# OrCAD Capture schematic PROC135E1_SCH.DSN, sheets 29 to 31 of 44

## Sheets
29 29. JTAG 20 PIN cTI CONNECTOR: size C; title: JTAG 20 PIN cTI CONNECTOR
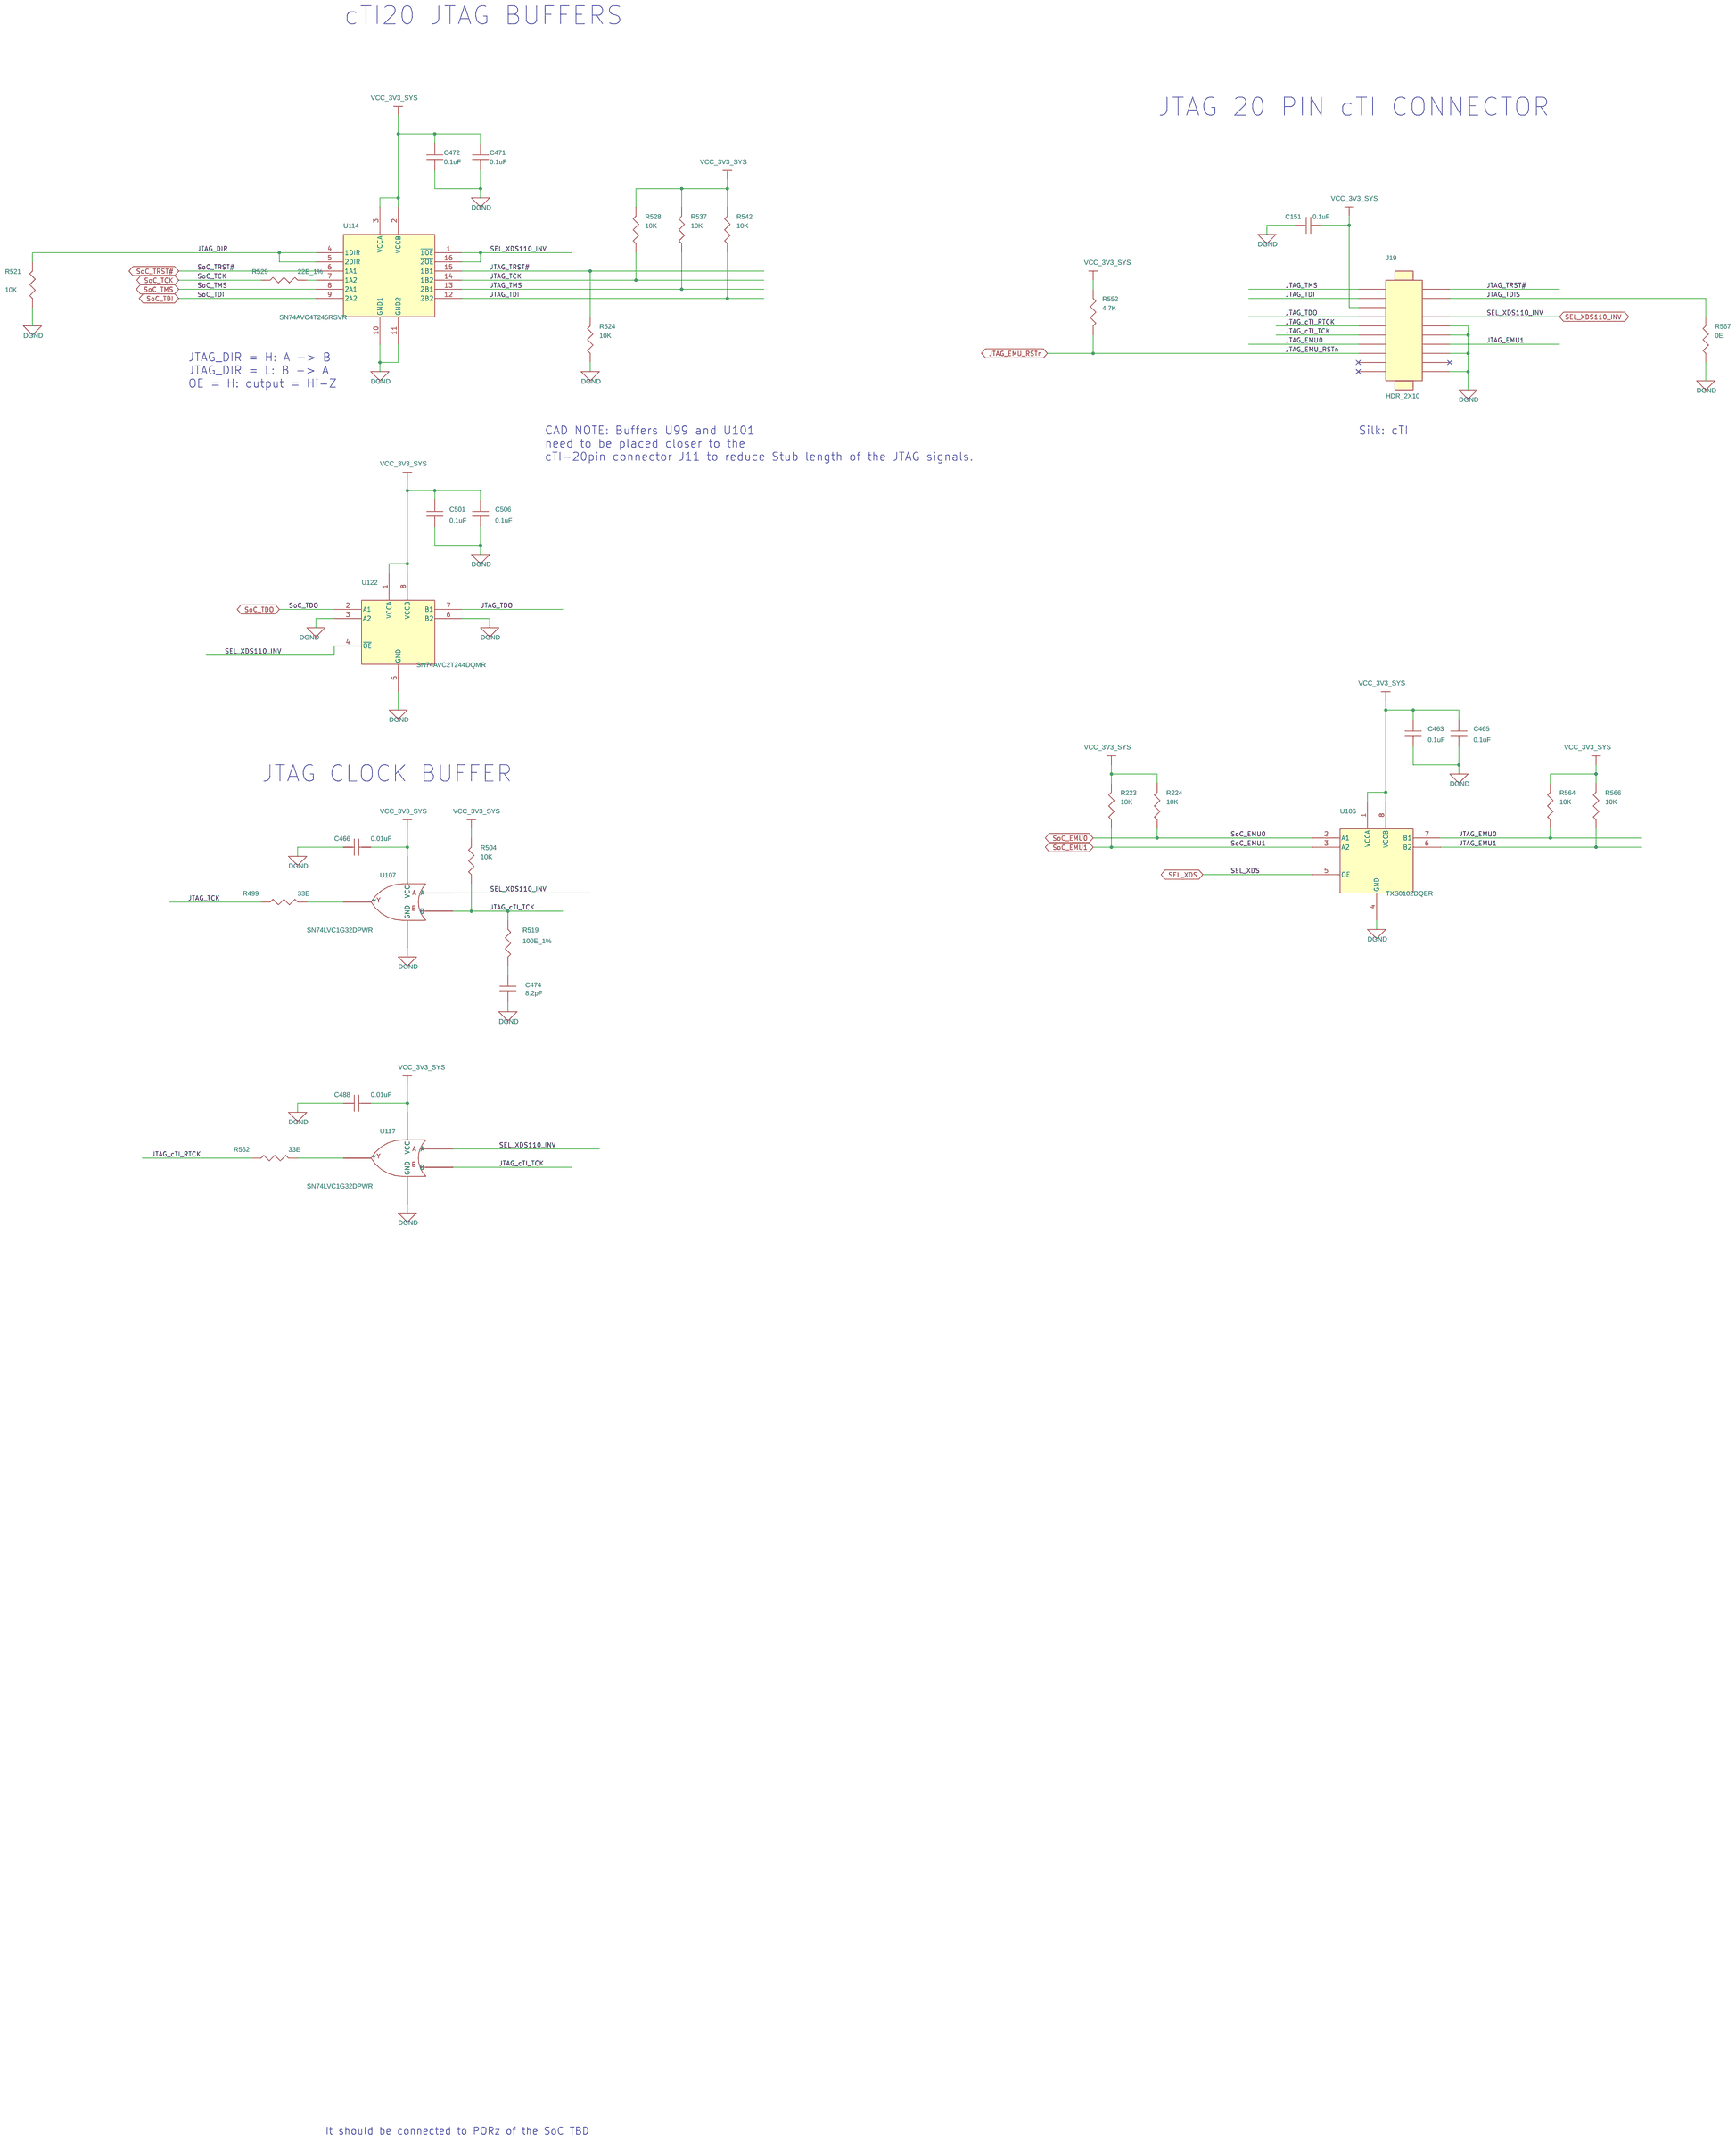
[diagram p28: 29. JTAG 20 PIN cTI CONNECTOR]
30 30. FT4232 UART TO USB BRIDGE: size C; title: FT4232 UART TO USB BRIDGE
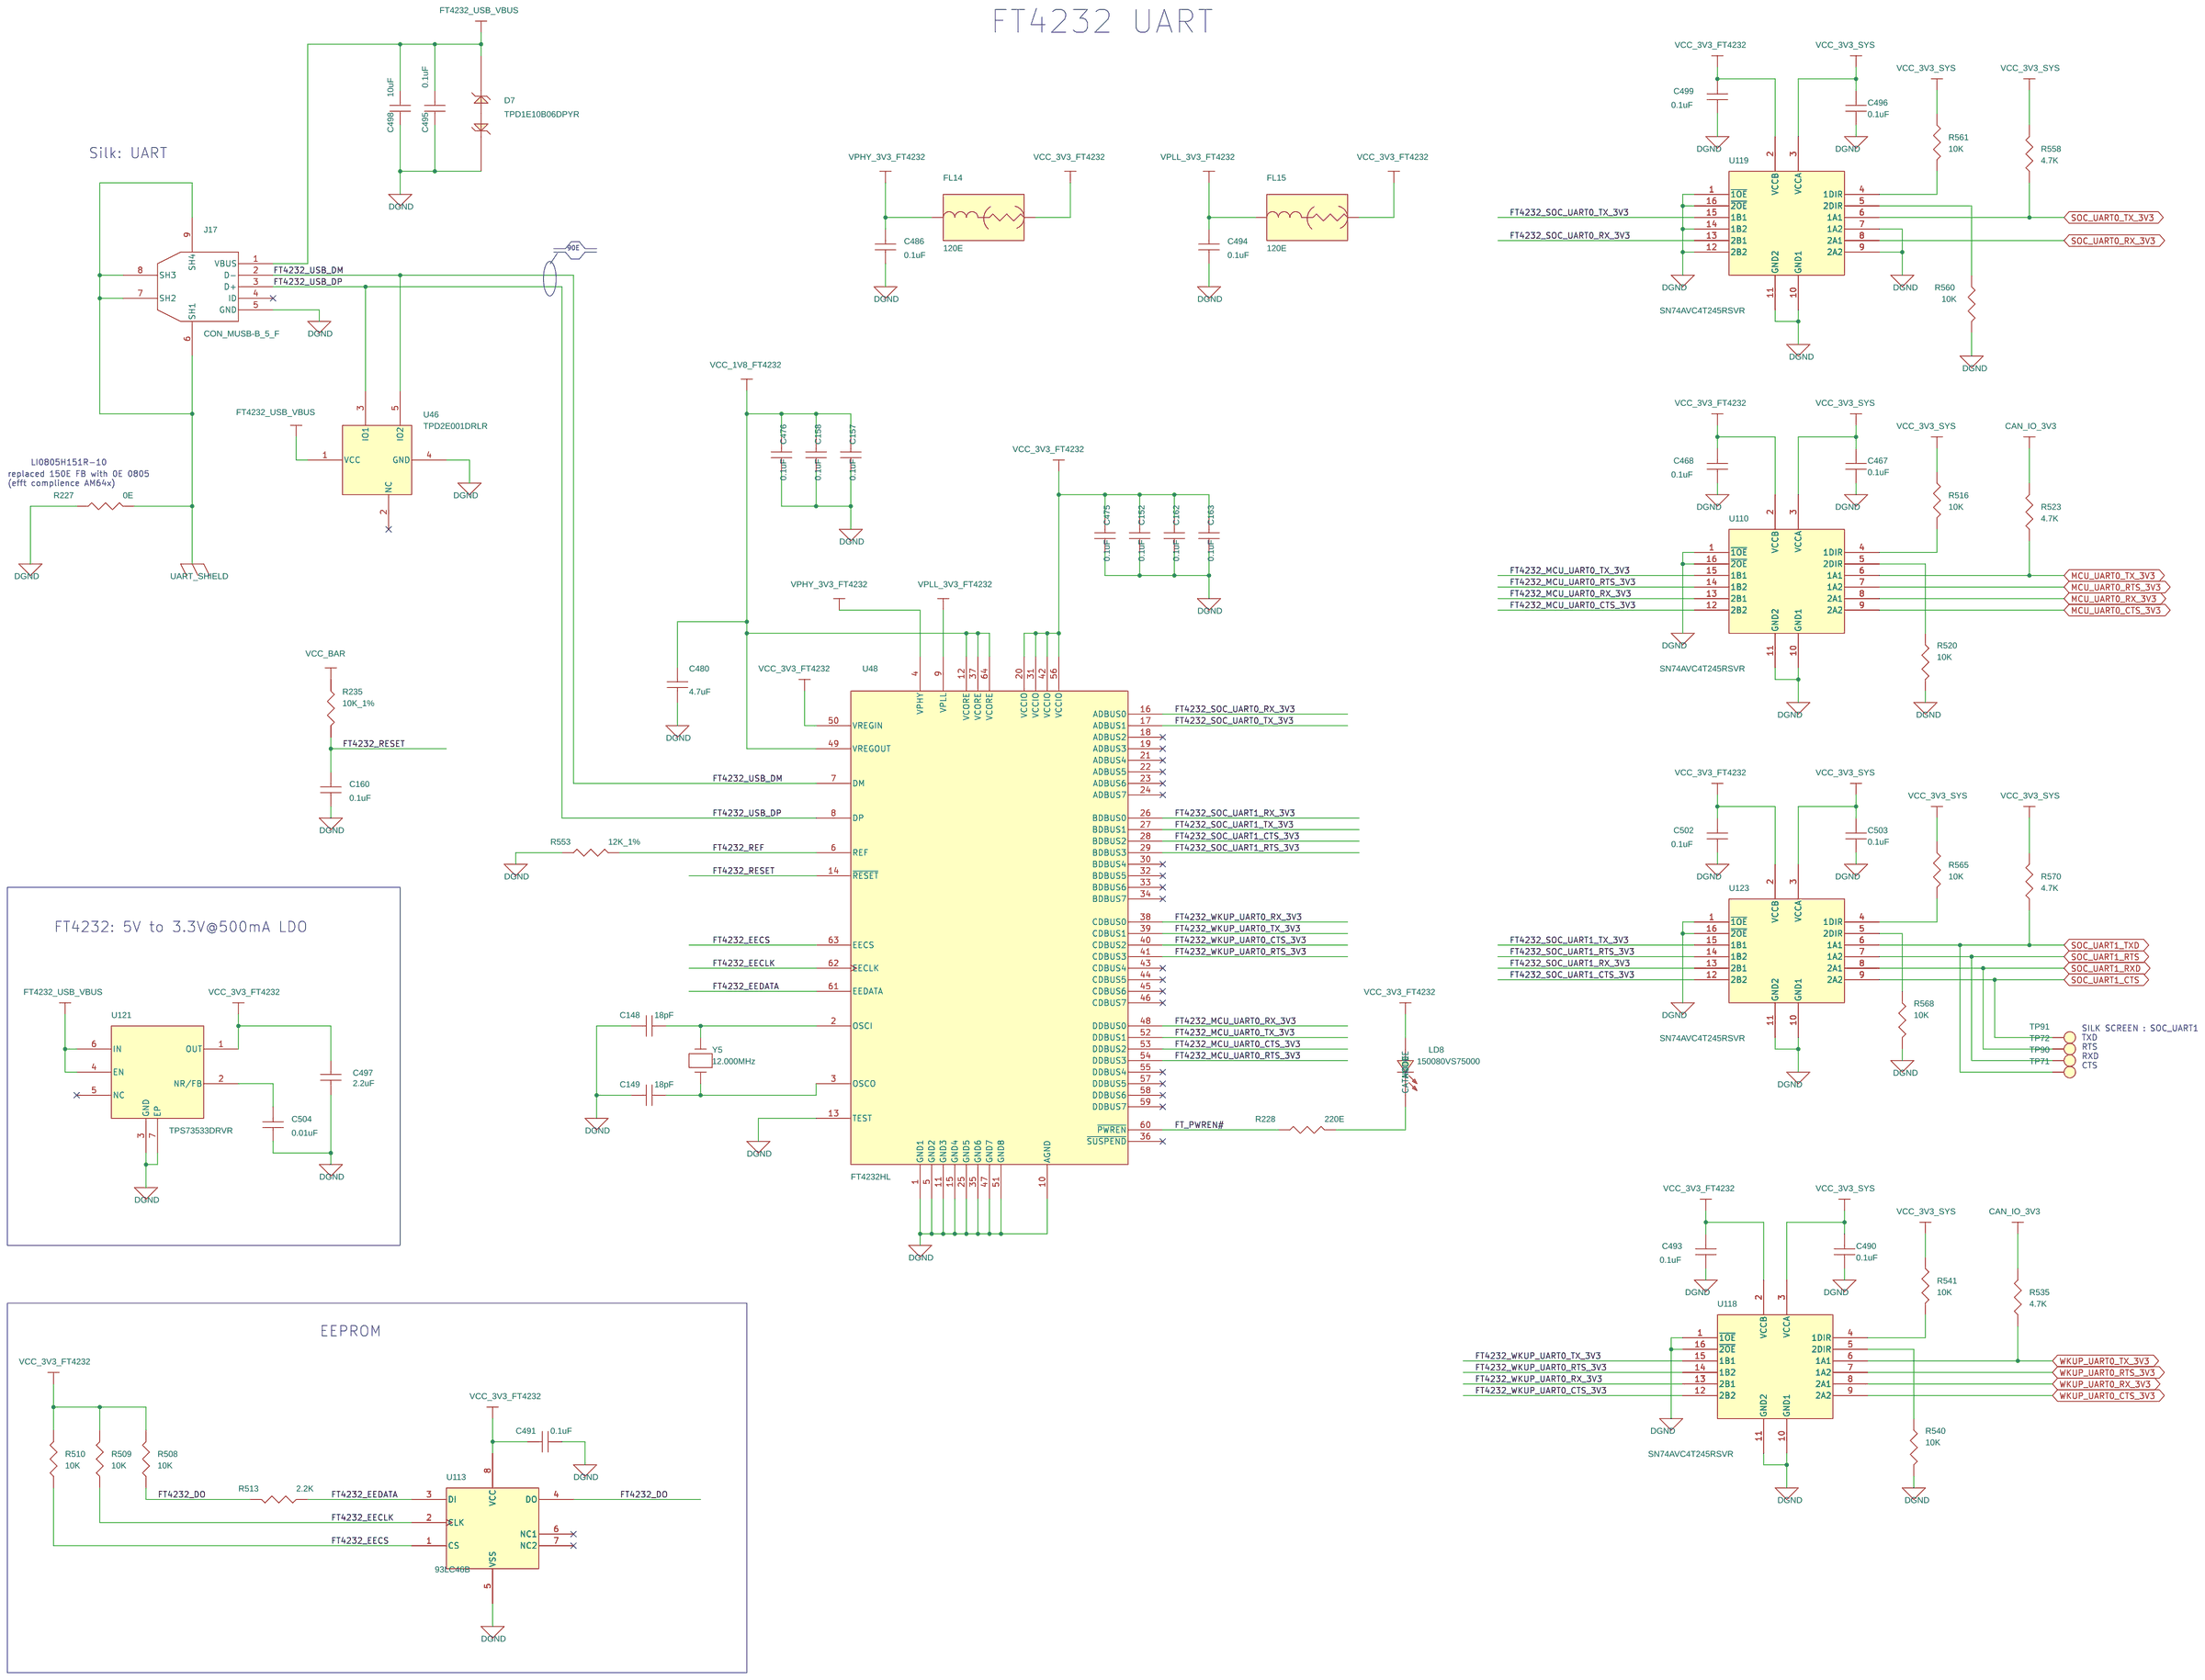
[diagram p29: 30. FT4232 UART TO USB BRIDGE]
31 31. SOC WKUP & GPMC: size C; title: SOC WKUP & GPMC

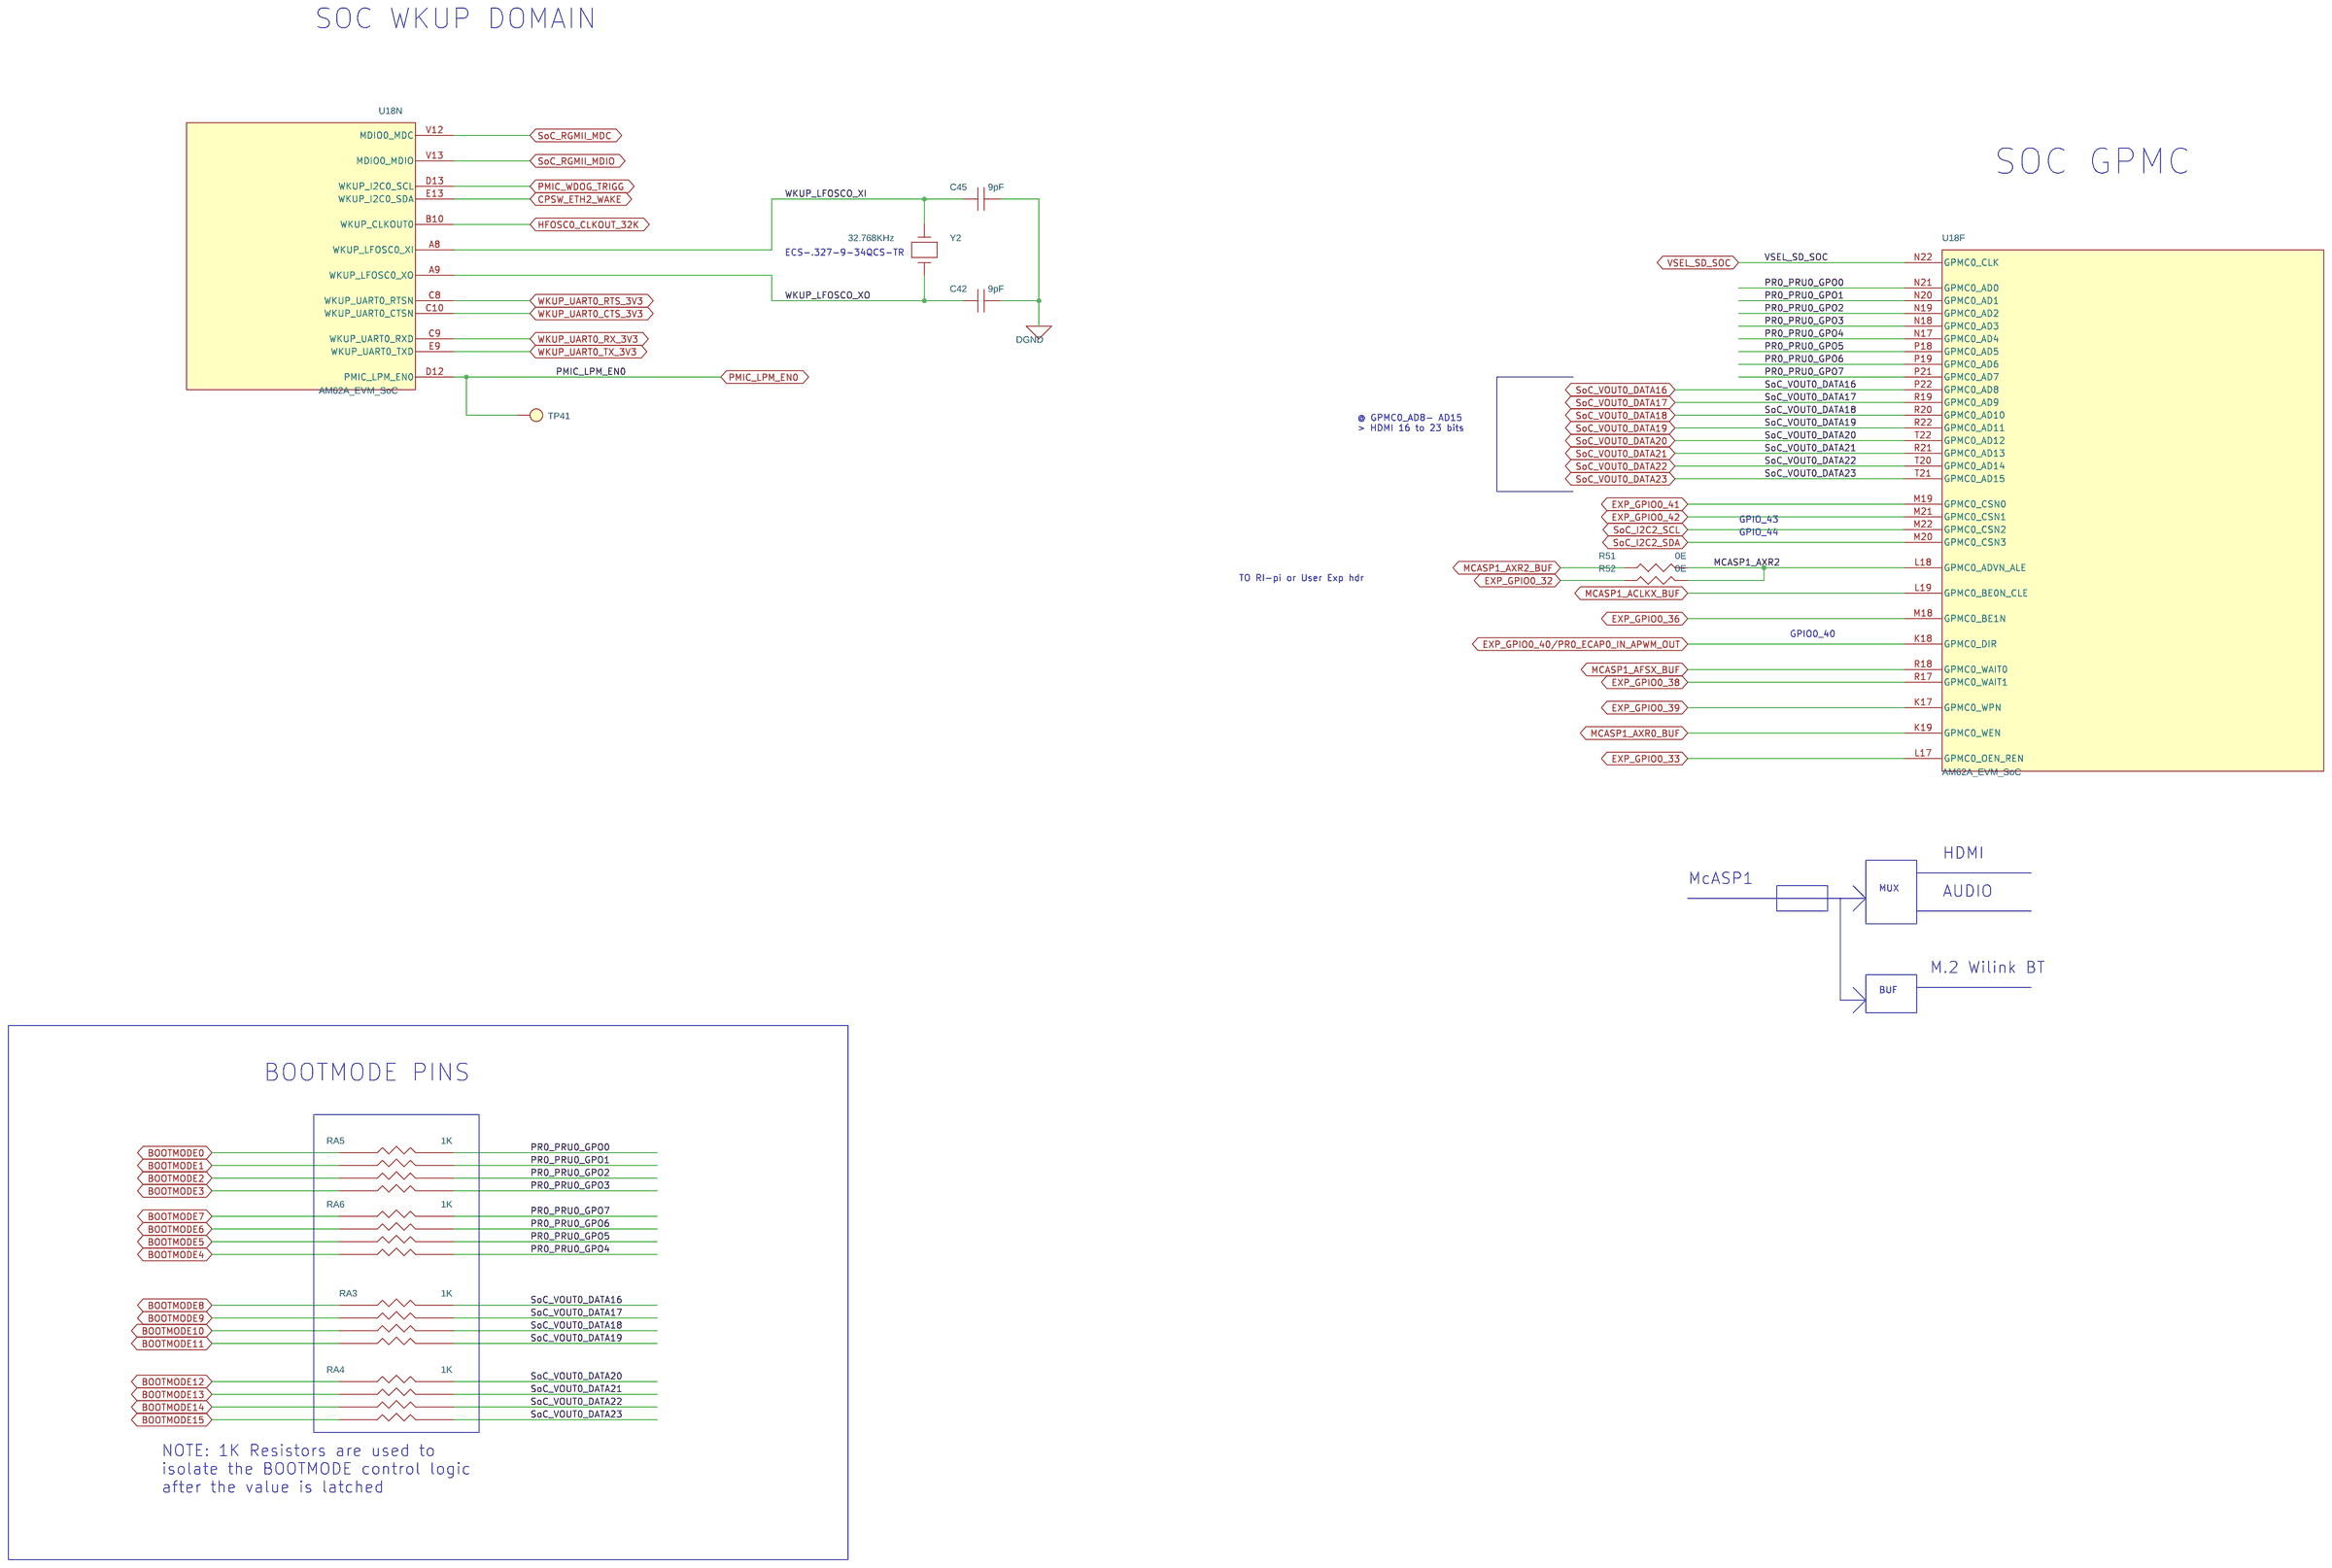
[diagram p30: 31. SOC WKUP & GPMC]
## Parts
sheet 29. JTAG 20 PIN cTI CONNECTOR
C151  0.1uF  [CAP0201_0-5]
C463  0.1uF  [CAP0201_0-5]
C465  0.1uF  [CAP0201_0-5]
C466  0.01uF  [CAP0201_0-5]
C471  0.1uF  [CAP0201_0-5]
C472  0.1uF  [CAP0201_0-5]
C474  8.2pF  [CAP0201_0-5]
C488  0.01uF  [CAP0201_0-5]
C501  0.1uF  [CAP0201_0-5]
C506  0.1uF  [CAP0201_0-5]
J19  HDR_2X10  [HDR_2X10_FTR-110-51-D-06_S_S_8-7]
R223  10K  [RES0201_0-5]
R224  10K  [RES0201_0-5]
R499  33E  [RES0201_0-5]
R504  10K  [RES0201_0-5]
R519  100E_1%  [RES0402_0-5]
R521  10K  [RES0201_0-5]
R524  10K  [RES0201_0-5]
R528  10K  [RES0201_0-5]
R529  22E_1%  [RES0201_0-5]
R537  10K  [RES0201_0-5]
R542  10K  [RES0201_0-5]
R552  4.7K  [RES0201_0-5]
R562  33E  [RES0201_0-5]
R564  10K  [RES0201_0-5]
R566  10K  [RES0201_0-5]
R567  0E  [RES0201_0-5]
U106  TXS0102DQER  [X2SON8_TXS0102_40X60_0-4]
U107  SN74LVC1G32DPWR  [X2SON5_TLV7021_30X30_0-4]
U114  SN74AVC4T245RSVR  [UQFN16_TMUX1574_70X100_0-6]
U117  SN74LVC1G32DPWR  [X2SON5_TLV7021_30X30_0-4]
U122  SN74AVC2T244DQMR  [X2SON8_15-74_70X50]
sheet 30. FT4232 UART TO USB BRIDGE
C148  18pF  [CAP0402_0-75]
C149  18pF  [CAP0402_0-75]
C152  0.1uF  [CAP0402_0-75]
C157  0.1uF  [CAP0402_0-75]
C158  0.1uF  [CAP0402_0-75]
C160  0.1uF  [CAP0201_0-5]
C162  0.1uF  [CAP0402_0-75]
C163  0.1uF  [CAP0402_0-75]
C467  0.1uF  [CAP0201_0-5]
C468  0.1uF  [CAP0201_0-5]
C475  0.1uF  [CAP0402_0-75]
C476  0.1uF  [CAP0402_0-75]
C480  4.7uF  [CAP0402_0-75]
C486  0.1uF  [CAP0402_0-75]
C490  0.1uF  [CAP0201_0-5]
C491  0.1uF  [CAP0402_0-75]
C493  0.1uF  [CAP0201_0-5]
C494  0.1uF  [CAP0402_0-75]
C495  0.1uF  [CAP0402_0-75]
C496  0.1uF  [CAP0201_0-5]
C497  2.2uF  [CAP0402_0-75]
C498  10uF  [CAP0402_0-75]
C499  0.1uF  [CAP0201_0-5]
C502  0.1uF  [CAP0201_0-5]
C503  0.1uF  [CAP0201_0-5]
C504  0.01uF  [CAP0201_0-5]
D7  TPD1E10B06DPYR  [DIO_DFN0402_0-5]
FL14  120E  [EMIFIL_BLM15A_0402_0-6]
FL15  120E  [EMIFIL_BLM15A_0402_0-6]
J17  CON_MUSB-B_5_F  [CON_MUSBB5_629105150521_S_R_S_2-7]
LD8  150080VS75000  [LED_150080VS75000_80X50_SMD_0-8]
R227  0E  [RES0805_0-75]
R228  220E  [RES0402_0-5]
R235  10K_1%  [RES0201_0-5]
R508  10K  [RES0201_0-5]
R509  10K  [RES0201_0-5]
R510  10K  [RES0201_0-5]
R513  2.2K  [RES0201_0-5]
R516  10K  [RES0201_0-5]
R520  10K  [RES0201_0-5]
R523  4.7K  [RES0201_0-5]
R535  4.7K  [RES0201_0-5]
R540  10K  [RES0201_0-5]
R541  10K  [RES0201_0-5]
R553  12K_1%  [RES0402_0-5]
R558  4.7K  [RES0201_0-5]
R560  10K  [RES0201_0-5]
R561  10K  [RES0201_0-5]
R565  10K  [RES0201_0-5]
R568  10K  [RES0201_0-5]
R570  4.7K  [RES0201_0-5]
TP71  TP20_SMD  [TP20_SMD]
TP72  TP20_SMD  [TP20_SMD]
TP90  TP20_SMD  [TP20_SMD]
TP91  TP20_SMD  [TP20_SMD]
U46  TPD2E001DRLR  [SOT553-5_0-6]
U48  FT4232HL  [LQFP64_19-68_390X390_1-6]
U110  SN74AVC4T245RSVR  [UQFN16_TMUX1574_70X100_0-6]
U113  93LC46B  [MSOP8_25-59_125X125_1-1]
U118  SN74AVC4T245RSVR  [UQFN16_TMUX1574_70X100_0-6]
U119  SN74AVC4T245RSVR  [UQFN16_TMUX1574_70X100_0-6]
U121  TPS73533DRVR  [SON6_25-59_85X85]
U123  SN74AVC4T245RSVR  [UQFN16_TMUX1574_70X100_0-6]
Y5  12.000MHz  [XTAL_ABM3_205X130_SMD_1-4]
sheet 31. SOC WKUP & GPMC
C42  9pF  [CAP0402_0-75]
C45  9pF  [CAP0402_0-75]
R51  0E  [RES0201_0-5]
R52  0E  [RES0201_0-5]
RA3  1K  [RESA_EXB_0201-4_0-5]
RA4  1K  [RESA_EXB_0201-4_0-5]
RA5  1K  [RESA_EXB_0201-4_0-5]
RA6  1K  [RESA_EXB_0201-4_0-5]
TP41  TP20_SMD  [TP20_SMD]
Y2  32.768KHz  [XTAL_ECS-32_130X60_SMD_0-9]
sheet 32. USER EXPANSION CONNECTOR
U18  AM62A_EVM_SoC  [FBGA484_31-49_710X710_2-7]  (sections A,B,C,D,E,F,G,H,I,J,K,L,M,N,O,P,Q)

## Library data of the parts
C151 C160 C463 C465 C467 C468 C471 C472 C490 C493 C496 C499 C501-C503 C506 = CAP: CAP CERAMIC 0.1uF 16V 10% X5R 0201; Alt_Mfr_name: YAGEO AMERICA; Alt_Mfr_part_number: CC0402KRX5R8BB104; Chkd/date: MANIRAJA/230118; Crtd /date: MANIRAJA/230118; Custom_Duty: 15%; Customs_HS_Code: 85322990; Distributor_name: DIGIKEY; Distributor_part_number: 490-14305-1-ND; Footprint Path: Y:\MIS_DATABASE\Library\ALTIUM_TOOL\PCB_FOOTPRINTS\Altium_Footprint_Lib.PcbLib; Height: 0.33MM; Library Path: Y:\MIS_DATABASE\Library\ALTIUM_TOOL\SCHEMATICS_PARTS\MS_DISCRETE_Library.schlib; Mfr_name: MURATA; Mfr_part_number: GRM033R61C104KE14D; Mistral Part No: 120009030072-R; Package: 0201; Part_type: CAPACITORS\CERAMIC; Project: TI_MAXIE_CPB; RoHS: RoHS; Temperature: -55°C+85°C; Tolerance: 10%; Voltage: 16V; Wattage: NA; Weight: 0.33mg; Datasheet: Y:\MIS_DATABASE\DATASHEETS\CAPACITORS\GRM033R61C104KE14.PDF
C466 C488 C504 = CAP: CAP CERAMIC 0.01uF 25V 10% X5R 0201; Chkd/date: MANIRAJA/230118; Crtd /date: MANIRAJA/230118; Custom_Duty: 15%; Customs_HS_Code: 85322990; Distributor_name: DIGIKEY; Distributor_part_number: GRM033R61E103KA12J-ND; Footprint Path: Y:\MIS_DATABASE\Library\ALTIUM_TOOL\PCB_FOOTPRINTS\Altium_Footprint_Lib.PcbLib; Height: 0.33MM; Library Path: Y:\MIS_DATABASE\Library\ALTIUM_TOOL\SCHEMATICS_PARTS\MS_DISCRETE_Library.schlib; Mfr_name: MURATA; Mfr_part_number: GRM033R61E103KA12J; Mistral Part No: 120018010007-R; Package: 0201; Part_type: CAPACITORS\CERAMIC; Project: TI_MAXIE_CPB; RoHS: RoHS; Temperature: -55°C+85°C; Tolerance: 10%; Voltage: 25V; Wattage: NA; Weight: 0.33mg; Datasheet: Y:\MIS_DATABASE\DATASHEETS\CAPACITORS\GRM033R61E103KA12.PDF
C474 = CAP: CAP CERAMIC 8.2pF 25V 0.5pF C0G(NP0) 0201; Chkd/date: MANIRAJA/121020; Crtd /date: ALVY/091020; Custom_Duty: 15%; Customs_HS_Code: 85322990; Distributor_name: DIGIKEY; Distributor_part_number: 490-3140-1-ND; Footprint Path: Y:\MIS_DATABASE\Library\ALTIUM_TOOL\PCB_FOOTPRINTS\Altium_Footprint_Lib.PcbLib; Height: 0.33MM; Library Path: Y:\MIS_DATABASE\Library\ALTIUM_TOOL\SCHEMATICS_PARTS\MS_DISCRETE_Library.schlib; Mfr_name: MURATA; Mfr_part_number: GRM0335C1E8R2DA01D; Mistral Part No: 120020100018-R; Package: 0201; Part_type: CAPACITORS\CERAMIC; Project: AM64X_SKEVM; RoHS: RoHS; Temperature: -55°C+125°C; Tolerance: 0.5pF%; Voltage: 25V; Wattage: NA; Weight: 0.33mg; Datasheet: Y:\MIS_DATABASE\DATASHEETS\CAPACITORS\GRM0335C1E8R2DA01.PDF
J19 = HEADER_10X2_FTR-06: CON HDR 2X10 1.27MM PITCH ST SMD; Chkd/date: MANIRAJA/031218; Crtd /date: CHAITHANYA/050811; Custom_Duty: 24%; Customs_HS_Code: 85369090; Distributor_name: DIGIKEY; Distributor_part_number: SAM8792-ND; Footprint Path: Y:\MIS_DATABASE\Library\ALTIUM_TOOL\PCB_FOOTPRINTS\Altium_Footprint_Lib.PcbLib; Height: 8.67MM; Library Path: Y:\MIS_DATABASE\Library\ALTIUM_TOOL\SCHEMATICS_PARTS\MS_CONNECTOR_Library.schlib; Mfr_name: SAMTEC; Mfr_part_number: FTR-110-51-S-D-06; Mistral Part No: 150011090001-R; Package: SMD; Part_type: CONNECTOR\HEADERS; Project: GEMYC; RoHS: RoHS; Temperature: -55°C+125°C; Tolerance: NA; Voltage: NA; Wattage: NA; Weight: NA; Datasheet: Y:\MIS_DATABASE\DATASHEETS\CONNECTORS\FTR-D-SER.PDF
R223 R224 R504 R508-R510 R516 R520 R521 R524 R528 R537 R540-R542 R560 R561 R564-R566 R568 = RESISTOR: RES 10K 1/20W 5% 0201; Chkd/date: MANIRAJA/050517; Crtd /date: MANIRAJA/050517; Custom_Duty: 15%; Customs_HS_Code: 85332119; Distributor_name: DIGIKEY; Distributor_part_number: 311-10KNCT-ND; Footprint Path: Y:\MIS_DATABASE\Library\ALTIUM_TOOL\PCB_FOOTPRINTS\Altium_Footprint_Lib.PcbLib; Height: 0.26MM; Library Path: Y:\MIS_DATABASE\Library\ALTIUM_TOOL\SCHEMATICS_PARTS\MS_DISCRETE_Library.schlib; Mfr_name: YAGEO AMERICA; Mfr_part_number: RC0201JR-0710KL; Mistral Part No: 110010070051-R; Package: 0201; Part_type: RESISTORS\FIXED; Project: GOLDEN-I LITE; RoHS: RoHS; Temperature: -55°C+125°C; Tolerance: 5%; Voltage: NA; Wattage: 1/20W; Weight: 0.17mg; Datasheet: Y:\MIS_DATABASE\DATASHEETS\RESISTORS\RCXXXXL-SER_MAR18.PDF
R499 R562 = RESISTOR: RES 33E 1/20W 5% 0201; Chkd/date: VASANTHA/061216; Crtd /date: MAZHAR/170505; Custom_Duty: 15%; Customs_HS_Code: 85332119; Distributor_name: DIGIKEY; Distributor_part_number: P33AGCT-ND; Footprint Path: Y:\MIS_DATABASE\Library\ALTIUM_TOOL\PCB_FOOTPRINTS\Altium_Footprint_Lib.PcbLib; Height: 0.26MM; Library Path: Y:\MIS_DATABASE\Library\ALTIUM_TOOL\SCHEMATICS_PARTS\MS_DISCRETE_Library.schlib; Mfr_name: PANASONIC-ECG; Mfr_part_number: ERJ-1GEJ330C; Mistral Part No: 110010070052-R; Package: 0201; Part_type: RESISTORS\FIXED; Project: G4SLIM; RoHS: RoHS; Temperature: -55°C+125°C; Tolerance: 5%; Voltage: NA; Wattage: 1/20W; Weight: 0.15mg; Datasheet: Y:\MIS_DATABASE\DATASHEETS\RESISTORS\PAN-ERJXGE-FEB06.PDF
R519 = RESISTOR: RES 100E 1/16W 1% 0402; Chkd/date: MANIRAJA/060318; Crtd /date: NAVEED/220714; Custom_Duty: 15%; Customs_HS_Code: 85332119; Distributor_name: DIGIKEY; Distributor_part_number: 311-100LRCT-ND; Footprint Path: Y:\MIS_DATABASE\Library\ALTIUM_TOOL\PCB_FOOTPRINTS\Altium_Footprint_Lib.PcbLib; Height: 0.40MM; Library Path: Y:\MIS_DATABASE\Library\ALTIUM_TOOL\SCHEMATICS_PARTS\MS_DISCRETE_Library.schlib; Mfr_name: YAGEO AMERICA; Mfr_part_number: RC0402FR-07100RL; Mistral Part No: 110014070015-R; Package: 0402; Part_type: RESISTORS\FIXED; Project: DLRU; RoHS: RoHS; Temperature: -55°C+155°C; Tolerance: 1%; Voltage: NA; Wattage: 1/16W; Weight: 0.65mg; Datasheet: Y:\MIS_DATABASE\DATASHEETS\RESISTORS\RCXXXXL-SER_MAR18.PDF
R529 = RESISTOR: RES 22E 1/20W 1% 0201; Chkd/date: MAZHAR/140709; Crtd /date: MAZHAR/220807; Custom_Duty: 15%; Customs_HS_Code: 85332119; Distributor_name: DIGIKEY; Distributor_part_number: P22.0ABCT-ND; Footprint Path: Y:\MIS_DATABASE\Library\ALTIUM_TOOL\PCB_FOOTPRINTS\Altium_Footprint_Lib.PcbLib; Height: 0.26MM; Library Path: Y:\MIS_DATABASE\Library\ALTIUM_TOOL\SCHEMATICS_PARTS\MS_DISCRETE_Library.schlib; Mfr_name: PANASONIC-ECG; Mfr_part_number: ERJ-1GEF22R0C; Mistral Part No: 110009030522-R; Package: 0201; Part_type: RESISTORS\FIXED; Project: V8TS; RoHS: RoHS; Temperature: -55°C+125°C; Tolerance: 1%; Voltage: NA; Wattage: 1/20W; Weight: 0.15mg; Datasheet: Y:\MIS_DATABASE\DATASHEETS\RESISTORS\PAN-ERJSER_NOV17.PDF
R523 R535 R552 R558 R570 = RESISTOR: RES 4.7K 1/20W 5% 0201; Chkd/date: MANIRAJA/200921; Crtd /date: ALVY/200921; Custom_Duty: 15%; Customs_HS_Code: 85332119; Distributor_name: DIGIKEY; Distributor_part_number: 311-4.7KNCT-ND; Footprint Path: Y:\MIS_DATABASE\Library\ALTIUM_TOOL\PCB_FOOTPRINTS\Altium_Footprint_Lib.PcbLib; Height: 0.26MM; Library Path: Y:\MIS_DATABASE\Library\ALTIUM_TOOL\SCHEMATICS_PARTS\MS_DISCRETE_Library.schlib; Mfr_name: YAGEO AMERICA; Mfr_part_number: RC0201JR-074K7L; Mistral Part No: 110021090007-R; Package: 0201; Part_type: RESISTORS\FIXED; Project: TI_AM62x SKEVM_BRD; RoHS: RoHS; Temperature: -55°C+125°C; Tolerance: 5%; Voltage: NA; Wattage: 1/20W; Weight: 0.17mg; Datasheet: Y:\MIS_DATABASE\DATASHEETS\RESISTORS\RCXXXXL-SER_MAR18.PDF
R51 R52 R567 = RESISTOR: RES 0E 1/20W 5% 0201; Chkd/date: NAVEED/301214; Crtd /date: MUDDU/120710; Custom_Duty: 15%; Customs_HS_Code: 85332119; Distributor_name: DIGIKEY; Distributor_part_number: 311-0.0NCT-ND; Footprint Path: Y:\MIS_DATABASE\Library\ALTIUM_TOOL\PCB_FOOTPRINTS\Altium_Footprint_Lib.PcbLib; Height: 0.26MM; Library Path: Y:\MIS_DATABASE\Library\ALTIUM_TOOL\SCHEMATICS_PARTS\MS_DISCRETE_Library.schlib; Mfr_name: YAGEO AMERICA; Mfr_part_number: RC0201JR-070RL; Mistral Part No: 110010070067-R; Package: 0201; Part_type: RESISTORS\FIXED; Project: PB_BUGBASE; RoHS: RoHS; Temperature: -55°C+125°C; Tolerance: 5%; Voltage: NA; Wattage: 1/20W; Weight: 0.17mg; Datasheet: Y:\MIS_DATABASE\DATASHEETS\RESISTORS\RCXXXXL-SER_MAR18.PDF
U106 = TXS0102DQX_SON8: IC 2-BIT BI-DIR VOLTAGE-LEVEL TRANSLATOR FOR OPEN-DRAIN AND PUSH-PULL X2SON8; Chkd/date: MANIRAJA/010719; Crtd /date: CHAITHANYA230512; Custom_Duty: 15%; Customs_HS_Code: 85423100; Distributor_name: DIGIKEY; Distributor_part_number: 296-28368-1-ND; Footprint Path: Y:\MIS_DATABASE\Library\ALTIUM_TOOL\PCB_FOOTPRINTS\Altium_Footprint_Lib.PcbLib; Height: 0.40MM; Library Path: Y:\MIS_DATABASE\Library\ALTIUM_TOOL\SCHEMATICS_PARTS\MS_MISCINTERFACE_Library.schlib; Mfr_name: TEXAS INSTRUMENTS; Mistral Part No: 141012050010-R; Package: X2SON8; Part_type: ICS\INTERFACE\LEVEL TRANSLATOR; Project: GEN_3-8_DB; RoHS: RoHS; Temperature: -40°C+85°C; Tolerance: NA; Voltage: NA; Wattage: NA; Weight: 1.2mg; Datasheet: Y:\MIS_DATABASE\DATASHEETS\ICS\INTERFACE\TXS0102-SER.PDF
U107 U117 = SN74LVC1G32_X2SON5: IC SINGLE 2-INPUT POSITIVE-OR GATE X2SON5; Chkd/date: MANIRAJA/141020; Crtd /date: ALVY/131020; Custom_Duty: 15%; Customs_HS_Code: 85423100; Distributor_name: DIGIKEY; Distributor_part_number: 296-SN74LVC1G32DPWRCT-ND; Footprint Path: Y:\MIS_DATABASE\Library\ALTIUM_TOOL\PCB_FOOTPRINTS\Altium_Footprint_Lib.PcbLib; Height: 0.40MM; Library Path: Y:\MIS_DATABASE\Library\ALTIUM_TOOL\SCHEMATICS_PARTS\MS_GATE_Library.schlib; Mfr_name: TEXAS INSTRUMENTS; Mistral Part No: 141020100011-R; Package: X2SON5; Part_type: ICS\DIGITAL\GATES; Project: AM64X_SKEVM; RoHS: RoHS; Temperature: -40°C+125°C; Tolerance: NA; Voltage: NA; Wattage: NA; Weight: 0.6mg; Datasheet: Y:\MIS_DATABASE\DATASHEETS\ICS\DIGITAL\GATES\SN74LVC1G32XX.PDF
U110 U114 U118 U119 U123 = SN74AVC4T245RSV_UQFN16: IC 2-BIT BUS TRANSCEIVER WITH CONFIGURABLE VOLTAGE TRANSLATION AND 3 STATE O/P UQFN16; Chkd/date: MANIRAJA/040520; Crtd /date: BAVISH/190411; Custom_Duty: 15%; Customs_HS_Code: 85423100; Distributor_name: DIGIKEY; Distributor_part_number: 296-24366-1-ND; Footprint Path: Y:\MIS_DATABASE\Library\ALTIUM_TOOL\PCB_FOOTPRINTS\Altium_Footprint_Lib.PcbLib; Height: 0.55MM; Library Path: Y:\MIS_DATABASE\Library\ALTIUM_TOOL\SCHEMATICS_PARTS\MS_BUSDRIVERTRANSCEIVER_Library.schlib; Mfr_name: TEXAS INSTRUMENTS; Mistral Part No: 141011040011-R; Package: UQFN16; Part_type: ICS\DIGITAL\BUSTRANSCEIVER; Project: HMC; RoHS: RoHS; Temperature: -40°C+85°C; Tolerance: NA; Voltage: NA; Wattage: NA; Weight: 41mg; Datasheet: Y:\MIS_DATABASE\DATASHEETS\ICS\DIGITAL\BUSTRANSCEIVER\SN74AVC4T245-SER.PDF
U122 = SN74AVC2T244DQMR_X2SON8: IC 2-BIT UNDIRECTIONAL VOLTAGE-LEVEL TRANSLATOR X2SON8; Chkd/date: VASANTHA/060516; Crtd /date: VASANTHA/030316; Customs_HS_Code: 15%; Distributor_name: DIGIKEY; Distributor_part_number: 296-29674-1-ND; Height: 0.40MM; Mfr_name: TEXAS INSTRUMENTS; Mistral Part No: 141016030002-R; Package: X2SON8; Part_type: ICS\INTERFACE\LEVEL TRANSLATOR; Pb-Free: 85423100; Project: OCTASIC_3600; RoHS: RoHS; Temperature: -40°C+85°C; Tolerance: NA; Voltage: NA; Wattage: NA; Weight: NA; Datasheet: Y:\MIS_DATABASE\DATASHEETS\ICS\INTERFACE\SN74AVC2T244.PDF
C148 C149 = CAP: CAP CERAMIC 18pF 50V 5% HI-Q C0G(NP0) 0402; Chkd/date: VASANTHA/030315; Crtd /date: NAVEED/271014; Custom_Duty: 15%; Customs_HS_Code: 85322990; Distributor_name: DIGIKEY; Distributor_part_number: 490-3119-1-ND; Footprint Path: Y:\MIS_DATABASE\Library\ALTIUM_TOOL\PCB_FOOTPRINTS\Altium_Footprint_Lib.PcbLib; Height: 0.55MM; Library Path: Y:\MIS_DATABASE\Library\ALTIUM_TOOL\SCHEMATICS_PARTS\MS_DISCRETE_Library.schlib; Mfr_name: MURATA; Mfr_part_number: GJM1555C1H180JB01D; Mistral Part No: 120014100019-R; Package: 0402; Part_type: CAPACITORS\CERAMIC; Project: DC_MIST_RDC; RoHS: RoHS; Temperature: -55°C+125°C; Tolerance: 5%; Voltage: 50V; Wattage: NA; Weight: 6mg; Datasheet: Y:\MIS_DATABASE\DATASHEETS\CAPACITORS\MURATA-GXX-SER_NOV17.PDF
C152 C157 C158 C162 C163 C475 C476 C486 C491 C494 C495 = CAP: CAP CERAMIC 0.1uF 50V 10% X7R 0402; Alt_Mfr_name: YAGEO AMERICA; Alt_Mfr_part_number: CC0402KRX5R8BB104; Chkd/date: MANIRAJA/261020; Crtd /date: ALVY/211020; Custom_Duty: 15%; Customs_HS_Code: 85322990; Distributor_name: DIGIKEY; Distributor_part_number: 490-10700-1-ND; Footprint Path: Y:\MIS_DATABASE\Library\ALTIUM_TOOL\PCB_FOOTPRINTS\Altium_Footprint_Lib.PcbLib; Height: 0.55MM; Library Path: Y:\MIS_DATABASE\Library\ALTIUM_TOOL\SCHEMATICS_PARTS\MS_DISCRETE_Library.schlib; Mfr_name: MURATA; Mfr_part_number: GRM155R71H104KE14D; Mistral Part No: 120011100014-R; Package: 0402; Part_type: CAPACITORS\CERAMIC; Project: J7_CP; RoHS: RoHS; Temperature: -55°C+125°C; Tolerance: 10%; Voltage: 50V; Wattage: NA; Weight: 3.1mg; Datasheet: Y:\MIS_DATABASE\DATASHEETS\CAPACITORS\GRM155R71H104KE14.PDF
C480 = CAP: CAP CERAMIC 4.7uF 10V 20% X5R 0402; Chkd/date: MANIRAJA/110718; Crtd /date: ALVY/110718; Custom_Duty: 15%; Customs_HS_Code: 85322990; Distributor_name: DIGIKEY; Distributor_part_number: 490-14306-1-ND; Footprint Path: Y:\MIS_DATABASE\Library\ALTIUM_TOOL\PCB_FOOTPRINTS\Altium_Footprint_Lib.PcbLib; Height: 0.65MM; Library Path: Y:\MIS_DATABASE\Library\ALTIUM_TOOL\SCHEMATICS_PARTS\MS_DISCRETE_Library.schlib; Mfr_name: MURATA; Mfr_part_number: GRM155R61A475MEAAD; Mistral Part No: 120012060002-R; Package: 0402; Part_type: CAPACITORS\CERAMIC; Project: TI_J7SVB_PCIE_ADD-ON-CARD; RoHS: RoHS; Temperature: -55°C+85°C; Tolerance: 20%; Voltage: 10V; Wattage: NA; Weight: 14mg; Datasheet: Y:\MIS_DATABASE\DATASHEETS\CAPACITORS\GRM155R61A475MEAAD.PDF
C497 = CAP: CAP CERAMIC 2.2uF 25V 10% X5R 0402; Chkd/date: ALVY/010721; Crtd /date: MANIRAJA/010721; Custom_Duty: 15%; Customs_HS_Code: 85322990; Distributor_name: DIGIKEY; Distributor_part_number: 490-12703-1-ND; Footprint Path: Y:\MIS_DATABASE\Library\ALTIUM_TOOL\PCB_FOOTPRINTS\Altium_Footprint_Lib.PcbLib; Height: 0.70MM; Library Path: Y:\MIS_DATABASE\Library\ALTIUM_TOOL\SCHEMATICS_PARTS\MS_DISCRETE_Library.schlib; Mfr_name: MURATA; Mfr_part_number: GRM155R61E225KE11D; Mistral Part No: 120015120001-R; Package: 0402; Part_type: CAPACITORS\CERAMIC; Project: TI_AM263X_CC; RoHS: RoHS; Temperature: -55°C+85°C; Tolerance: 10%; Voltage: 25V; Wattage: NA; Weight: 1.5mg; Datasheet: Y:\MIS_DATABASE\DATASHEETS\CAPACITORS\GRM155R61E225KE11.PDF
C498 = CAP: CAP CERAMIC 10uF 10V 20% X5R 0402; Chkd/date: MANIRAJA/300520; Crtd /date: ALVY/260520; Custom_Duty: 15%; Customs_HS_Code: 85322990; Distributor_name: DIGIKEY; Distributor_part_number: 490-GRM155R61A106ME11DTR-ND; Footprint Path: Y:\MIS_DATABASE\Library\ALTIUM_TOOL\PCB_FOOTPRINTS\Altium_Footprint_Lib.PcbLib; Height: 0.55MM; Library Path: Y:\MIS_DATABASE\Library\ALTIUM_TOOL\SCHEMATICS_PARTS\MS_DISCRETE_Library.schlib; Mfr_name: MURATA; Mfr_part_number: GRM155R61A106ME11D; Mistral Part No: 120013110019-R; Package: 0402; Part_type: CAPACITORS\CERAMIC; Project: QCS610_NANOSOM; RoHS: RoHS; Temperature: -55°C+85°C; Tolerance: 20%; Voltage: 10V; Wattage: NA; Weight: 3.1mg; Datasheet: Y:\MIS_DATABASE\DATASHEETS\CAPACITORS\MURATA-GXX-SER_NOV17.PDF
D7 = DIODE_SOD323: DIODE 1CH ESD PROTECTION X1SON2; Chkd/date: MANIRAJA/040420; Crtd /date: VASANTHA/181114; Custom_Duty: 15%; Customs_HS_Code: 85423100; Distributor_name: DIGIKEY; Distributor_part_number: 296-30406-1-ND; Footprint Path: Y:\MIS_DATABASE\Library\ALTIUM_TOOL\PCB_FOOTPRINTS\Altium_Footprint_Lib.PcbLib; Height: 0.45MM; Library Path: Y:\MIS_DATABASE\Library\ALTIUM_TOOL\SCHEMATICS_PARTS\MS_DISCRETE_Library.schlib; Mfr_name: TEXAS INSTRUMENTS; Mistral Part No: 130014110022-R; Package: X1SON2; Part_type: DIODE; Project: GALILEO_EVM; RoHS: RoHS; Temperature: -40°C+125°C; Tolerance: NA; Voltage: NA; Wattage: NA; Weight: 1mg; Datasheet: Y:\MIS_DATABASE\DATASHEETS\ICS\INTERFACE\TPD1E10B06-SER.PDF
FL14 FL15 = EMIFILTER_IND: IND FERRITE BEAD CHIP 120E 2A 0402; Chkd/date: NAVEED/241114; Crtd /date: USMAN/170613; Custom_Duty: 24%; Customs_HS_Code: 85369090; Distributor_name: DIGIKEY; Distributor_part_number: 490-9656-1-ND; Footprint Path: Y:\MIS_DATABASE\Library\ALTIUM_TOOL\PCB_FOOTPRINTS\Altium_Footprint_Lib.PcbLib; Height: 0.55MM; Library Path: Y:\MIS_DATABASE\Library\ALTIUM_TOOL\SCHEMATICS_PARTS\MS_FILTER_Library.schlib; Mfr_name: MURATA; Mfr_part_number: BLM15PX121SN1D; Mistral Part No: 130013060022-R; Package: 0402; Part_type: INDUCTOR; Project: GEN_3-8; RoHS: RoHS; Temperature: -55°C+125°C; Tolerance: 25%; Voltage: NA; Wattage: NA; Weight: 1mg; Datasheet: Y:\MIS_DATABASE\DATASHEETS\DISCRETES\INDUCTORS\BLM15-SN1-SER.PDF
J17 = CON_USB_MINI-B: CON MICRO USB TYPE B 5POS FEMALE RT SMD; Chkd/date: MANIRAJA/150519; Crtd /date: ALVY/150519; Custom_Duty: 24%; Customs_HS_Code: 85369090; Distributor_name: DIGIKEY; Distributor_part_number: 732-5960-1-ND; Footprint Path: Y:\MIS_DATABASE\Library\ALTIUM_TOOL\PCB_FOOTPRINTS\Altium_Footprint_Lib.PcbLib; Height: 2.66MM; Library Path: Y:\MIS_DATABASE\Library\ALTIUM_TOOL\SCHEMATICS_PARTS\MS_CONNECTOR_Library.schlib; Mfr_name: WURTH ELECTRONICS; Mfr_part_number: 629105150521; Mistral Part No: 150019050015-R; Package: SMD; Part_type: CONNECTOR\USB; Project: NEXTNAV_ALT-STATION_ATE_BRD; RoHS: RoHS; Temperature: -40°C+85°C; Tolerance: NA; Voltage: NA; Wattage: NA; Weight: 360mg; Datasheet: Y:\MIS_DATABASE\DATASHEETS\CONNECTORS\629105150521.PDF
LD8 = DIODE_LED: DIODE LED BRIGHT GREEN SMD; Chkd/date: MANIRAJA/180820; Crtd /date: ALVY/180820; Custom_Duty: 24%; Customs_HS_Code: 85439000; Distributor_name: DIGIKEY; Distributor_part_number: 732-4986-1-ND; Footprint Path: Y:\MIS_DATABASE\Library\ALTIUM_TOOL\PCB_FOOTPRINTS\Altium_Footprint_Lib.PcbLib; Height: 0.80MM; Library Path: Y:\MIS_DATABASE\Library\ALTIUM_TOOL\SCHEMATICS_PARTS\MS_OPTO_Library.schlib; Mfr_name: WURTH ELECTRONICS; Mistral Part No: 130020080012-R; Package: SMD; Part_type: OPTO\LED; Project: AM64x_EVM_BRD; RoHS: RoHS; Temperature: -40°C+85°C; Tolerance: NA; Voltage: NA; Wattage: NA; Weight: 10mg; Datasheet: Y:\MIS_DATABASE\DATASHEETS\DISCRETES\LEDS\150080VS75000.PDF
R227 = RESISTOR: RES 0E 1/8W 5% 0805; Chkd/date: VASANTHA/130416; Crtd /date: JEBRAN/020316; Custom_Duty: 15%; Customs_HS_Code: 85332119; Distributor_name: DIGIKEY; Distributor_part_number: 311-0.0ARCT-ND; Footprint Path: Y:\MIS_DATABASE\Library\ALTIUM_TOOL\PCB_FOOTPRINTS\Altium_Footprint_Lib.PcbLib; Height: 0.60MM; Library Path: Y:\MIS_DATABASE\Library\ALTIUM_TOOL\SCHEMATICS_PARTS\MS_DISCRETE_Library.schlib; Mfr_name: YAGEO AMERICA; Mfr_part_number: RC0805JR-070RL; Mistral Part No: 110009030074-R; Package: 0805; Part_type: RESISTORS\FIXED; Project: ZK_BIOMETRIC; RoHS: RoHS; Temperature: -55°C+155°C; Tolerance: 5%; Voltage: NA; Wattage: 1/8W; Weight: 5.5mg; Datasheet: Y:\MIS_DATABASE\DATASHEETS\RESISTORS\RCXXXXL-SER_MAR18.PDF
R228 = RESISTOR: RES 220E 1/10W 5% 0402; Chkd/date: VASANTHA/291216; Crtd /date: GEETHA/260406; Custom_Duty: 15%; Customs_HS_Code: 85332119; Distributor_name: DIGIKEY; Distributor_part_number: P220JCT-ND; Footprint Path: Y:\MIS_DATABASE\Library\ALTIUM_TOOL\PCB_FOOTPRINTS\Altium_Footprint_Lib.PcbLib; Height: 0.40MM; Library Path: Y:\MIS_DATABASE\Library\ALTIUM_TOOL\SCHEMATICS_PARTS\MS_DISCRETE_Library.schlib; Mfr_name: PANASONIC-ECG; Mfr_part_number: ERJ-2GEJ221X; Mistral Part No: 110009030506-R; Package: 0402; Part_type: RESISTORS\FIXED; Project: RED EYE; RoHS: RoHS; Temperature: -55°C+155°C; Tolerance: 5%; Voltage: NA; Wattage: 1/10W; Weight: 0.8mg; Datasheet: Y:\MIS_DATABASE\DATASHEETS\RESISTORS\PAN-ERJSER_NOV17.PDF
R235 = RESISTOR: RES 10K 1/20W 1% 0201; Chkd/date: VASANTHA/270117; Crtd /date: MANIRAJA/270117; Custom_Duty: 15%; Customs_HS_Code: 85332119; Distributor_name: DIGIKEY; Distributor_part_number: 311-10.0KMCT-ND; Footprint Path: Y:\MIS_DATABASE\Library\ALTIUM_TOOL\PCB_FOOTPRINTS\Altium_Footprint_Lib.PcbLib; Height: 0.26MM; Library Path: Y:\MIS_DATABASE\Library\ALTIUM_TOOL\SCHEMATICS_PARTS\MS_DISCRETE_Library.schlib; Mfr_name: YAGEO AMERICA; Mfr_part_number: RC0201FR-0710KL; Mistral Part No: 110011040018-R; Package: 0201; Part_type: RESISTORS\FIXED; Project: GOLDEN-I LITE; RoHS: RoHS; Temperature: -55°C+125°C; Tolerance: 1%; Voltage: NA; Wattage: 1/20W; Weight: 0.17mg; Datasheet: Y:\MIS_DATABASE\DATASHEETS\RESISTORS\RCXXXXL-SER_MAR18.PDF
R513 = RESISTOR: RES 2.2K 1/20W 5% 0201; Chkd/date: VASANTHA/010117; Crtd /date: MAZHAR/010605; Custom_Duty: 15%; Customs_HS_Code: 85332119; Distributor_name: DIGIKEY; Distributor_part_number: P2.2KAGCT-ND; Footprint Path: Y:\MIS_DATABASE\Library\ALTIUM_TOOL\PCB_FOOTPRINTS\Altium_Footprint_Lib.PcbLib; Height: 0.26MM; Library Path: Y:\MIS_DATABASE\Library\ALTIUM_TOOL\SCHEMATICS_PARTS\MS_DISCRETE_Library.schlib; Mfr_name: PANASONIC-ECG; Mfr_part_number: ERJ-1GEJ222C; Mistral Part No: 110009030427-R; Package: 0201; Part_type: RESISTORS\FIXED; Project: G4SLIM; RoHS: RoHS; Temperature: -55°C+125°C; Tolerance: 5%; Voltage: NA; Wattage: 1/20W; Weight: 0.15mg; Datasheet: Y:\MIS_DATABASE\DATASHEETS\RESISTORS\PAN-ERJXGE-FEB06.PDF
R553 = RESISTOR: RES 12K 1/10W 1% 0402; Chkd/date: VASANTHA/041215; Crtd /date: VASANTHA/041215; Custom_Duty: 15%; Customs_HS_Code: 85332119; Distributor_name: DIGIKEY; Distributor_part_number: P12.0KLCT-ND; Footprint Path: Y:\MIS_DATABASE\Library\ALTIUM_TOOL\PCB_FOOTPRINTS\Altium_Footprint_Lib.PcbLib; Height: 0.40MM; Library Path: Y:\MIS_DATABASE\Library\ALTIUM_TOOL\SCHEMATICS_PARTS\MS_DISCRETE_Library.schlib; Mfr_name: PANASONIC-ECG; Mfr_part_number: ERJ-2RKF1202X; Mistral Part No: 110019040053-R; Package: 0402; Part_type: RESISTORS\FIXED; Project: TI_C5545; RoHS: RoHS; Temperature: -55°C+155°C; Tolerance: 1%; Voltage: NA; Wattage: 1/10W; Weight: 0.8mg; Datasheet: Y:\MIS_DATABASE\DATASHEETS\RESISTORS\PAN-ERJSER_NOV17.PDF
TP41 TP71 TP72 TP90 TP91 = TESTPOINT: TESTPOINT CIR 20 SMD; Chkd/date: SHREESHAIL/171006; Crtd /date: MAZHAR/171006; Custom_Duty: NA; Customs_HS_Code: NA; Distributor_name: NA; Distributor_part_number: NA; Footprint Path: Y:\MIS_DATABASE\Library\ALTIUM_TOOL\PCB_FOOTPRINTS\Altium_Footprint_Lib.PcbLib; Height: NA; Library Path: Y:\MIS_DATABASE\Library\ALTIUM_TOOL\SCHEMATICS_PARTS\MS_DISCRETE_Library.schlib; MECHANICAL 3D STEP FILE: NA; Mfr_name: LOCAL; Mistral Part No: NA; Package: SMD; Project: BT MODULE_CSRBC04; RoHS: NA; Temperature: NA; Tolerance: NA; Voltage: NA; Wattage: NA; Weight: NA; Datasheet: NA
U46 = TPD2E001DRLR_SOT-5: IC ESD-PROTECTION DIODE ARRAYS SOT-5; Chkd/date: NAVEED/150714; Crtd /date: MUDDU/250510; Custom_Duty: 15%; Customs_HS_Code: 85423100; Distributor_name: DIGIKEY; Distributor_part_number: 296-21883-1-ND; Footprint Path: Y:\MIS_DATABASE\Library\ALTIUM_TOOL\PCB_FOOTPRINTS\Altium_Footprint_Lib.PcbLib; Height: 0.60MM; Library Path: Y:\MIS_DATABASE\Library\ALTIUM_TOOL\SCHEMATICS_PARTS\MS_FILTER_Library.schlib; Mfr_name: TEXAS INSTRUMENTS; Mistral Part No: 140110060007-R; Package: SOT-5; Part_type: ICS\ANALOG\ACTIVE FILTER; Project: CENTAURUS; RoHS: RoHS; Temperature: -40°C+85°C; Tolerance: NA; Voltage: NA; Wattage: NA; Weight: 2.8mg; Datasheet: Y:\MIS_DATABASE\DATASHEETS\ICS\MISC\TPD2E001DRLR.PDF
U48 = FT4232H_LQFP64: IC HIGH SPEED QUAD USB UART LQFP64; Chkd/date: MANIRAJA/110917; Crtd /date: VIJAYALAKSHMI/120813; Custom_Duty: 15%; Customs_HS_Code: 85423100; Distributor_name: DIGIKEY; Distributor_part_number: 768-1026-1-ND; Footprint Path: Y:\MIS_DATABASE\Library\ALTIUM_TOOL\PCB_FOOTPRINTS\Altium_Footprint_Lib.PcbLib; Height: 1.60MM; Library Path: Y:\MIS_DATABASE\Library\ALTIUM_TOOL\SCHEMATICS_PARTS\MS_COMBINATIONAL_Library.schlib; Mfr_name: FTDI; Mfr_part_number: FT4232HL-REEL; Mistral Part No: 141013080006-R; Package: LQFP64; Part_type: ICS\DIGITAL\PERIPHERAL; Project: DM37XX; RoHS: RoHS; Temperature: -40°C+85°C; Tolerance: NA; Voltage: NA; Wattage: NA; Weight: 342.7mg; Datasheet: Y:\MIS_DATABASE\DATASHEETS\ICS\DIGITAL\PERIPHERAL\FT4232HX.PDF
U113 = 93LC46B_MSOP8: IC 1K MICROWIRE COMPATIBLE SERIAL EEPROM MSOP8; Chkd/date: MANIRAJA/150218; Crtd /date: ALVY/150218; Custom_Duty: 15%; Customs_HS_Code: 85423100; Distributor_name: DIGIKEY; Distributor_part_number: 93LC46B-I/MS-ND; Footprint Path: Y:\MIS_DATABASE\Library\ALTIUM_TOOL\PCB_FOOTPRINTS\Altium_Footprint_Lib.PcbLib; Height: 1.10MM; Library Path: Y:\MIS_DATABASE\Library\ALTIUM_TOOL\SCHEMATICS_PARTS\MS_MISCMEMORY_Library.schlib; Mfr_name: MICROCHIP; Mfr_part_number: 93LC46B-I/MS; Mistral Part No: 141118020002-R; Package: MSOP8; Part_type: ICS\DIGITAL\MEMORY; Project: TI_MAXIE_CPB; RoHS: RoHS; Temperature: -40°C+85°C; Tolerance: NA; Voltage: NA; Wattage: NA; Weight: 140mg; Datasheet: Y:\MIS_DATABASE\DATASHEETS\ICS\MEMORY\93LC46B.PDF
U121 = TPS73501DRVR_SON6: IC 500mA LOW DROPOUT REGULATOR SON6; Chkd/date: VASANTHA/280915; Crtd /date: NAVEED/011014; Custom_Duty: 15%; Customs_HS_Code: 85423100; Distributor_name: DIGIKEY; Distributor_part_number: TPS73533DRVR-ND; Height: 0.80MM; Mfr_name: TEXAS INSTRUMENTS; Mistral Part No: 142014100001-R; Package: SON6; Part_type: ICS\POWER\VOLTAGE REGULATOR; Project: BLUETOOTH_WATCH; RoHS: RoHS; Temperature: -40°C+125°C; Tolerance: NA; Voltage: NA; Wattage: NA; Weight: NA; Datasheet: Y:\MIS_DATABASE\DATASHEETS\ICS\POWER\TPS735.PDF
Y5 = CRY: CRY 12.000MHz 18pF SMD; Chkd/date: MANIRAJA/310818; Crtd /date: MANIRAJA/310818; Custom_Duty: 24%; Customs_HS_Code: 85439000; Distributor_name: DIGIKEY; Distributor_part_number: CTX1170CT-ND; Footprint Path: Y:\MIS_DATABASE\Library\ALTIUM_TOOL\PCB_FOOTPRINTS\Altium_Footprint_Lib.PcbLib; Height: 1.35MM; Library Path: Y:\MIS_DATABASE\Library\ALTIUM_TOOL\SCHEMATICS_PARTS\MS_DISCRETE_Library.schlib; Mfr_name: CTS; Mfr_part_number: 445I23D12M00000; Mistral Part No: 130018080040-R; Package: SMD; Part_type: CRYSTAL; Project: TI_MAXIE_CPB; RoHS: RoHS; Temperature: -40°C+85°C; Tolerance: NA; Voltage: NA; Wattage: NA; Weight: 50mg; Datasheet: Y:\MIS_DATABASE\DATASHEETS\MISC\CRY_OSC\445.PDF
C42 C45 = CAP: CAP CERAMIC 9pF 50V 0.5pF HI-Q C0G(NP0) 0402; Chkd/date: MANIRAJA/160921; Crtd /date: ALVY/150921; Custom_Duty: 15%; Customs_HS_Code: 85322990; Distributor_name: DIGIKEY; Distributor_part_number: 490-14793-1-ND; Footprint Path: Y:\MIS_DATABASE\Library\ALTIUM_TOOL\PCB_FOOTPRINTS\Altium_Footprint_Lib.PcbLib; Height: 0.55MM; Library Path: Y:\MIS_DATABASE\Library\ALTIUM_TOOL\SCHEMATICS_PARTS\MS_DISCRETE_Library.schlib; Mfr_name: MURATA; Mfr_part_number: GJM1555C1H9R0DB01D; Mistral Part No: 120021090005-R; Package: 0402; Part_type: CAPACITORS\CERAMIC; Project: TI_AM62x SKEVM_BRD; RoHS: RoHS; Temperature: -55°C+125°C; Tolerance: 0.5pF%; Voltage: 50V; Wattage: NA; Weight: 1.5mg; Datasheet: Y:\MIS_DATABASE\DATASHEETS\CAPACITORS\GJM1555C1H9R0DB01.PDF
RA3-RA6 = RESARR_ISO4: RES ARRAY 1K 31mW 5% 0201-4; Chkd/date: NAVEED/110515; Crtd /date: VASANTHA/080515; Custom_Duty: 15%; Customs_HS_Code: 85332119; Distributor_name: DIGIKEY; Distributor_part_number: Y6102CT-ND; Footprint Path: Y:\MIS_DATABASE\Library\ALTIUM_TOOL\PCB_FOOTPRINTS\Altium_Footprint_Lib.PcbLib; Height: 0.45MM; Library Path: Y:\MIS_DATABASE\Library\ALTIUM_TOOL\SCHEMATICS_PARTS\MS_DISCRETE_Library.schlib; Mfr_name: PANASONIC-ECG; Mfr_part_number: EXB-18V102JX; Mistral Part No: 110015050003-R; Package: 0201-4; Part_type: RESISTORS\ARRAY; Project: FREE SCALE NANO; RoHS: RoHS; Temperature: -55°C+125°C; Tolerance: 5%; Voltage: NA; Wattage: 31mW; Weight: 1mg; Datasheet: Y:\MIS_DATABASE\DATASHEETS\RESISTORS\EXB-18V.PDF
Y2 = CRY: CRY 32.768KHz 9pF SMD; Chkd/date: VASANTHA/090419; Crtd /date: ALVY/090419; Custom_Duty: 24%; Customs_HS_Code: 85439000; Distributor_name: DIGIKEY; Distributor_part_number: XC2160CT-ND; Footprint Path: Y:\MIS_DATABASE\Library\ALTIUM_TOOL\PCB_FOOTPRINTS\Altium_Footprint_Lib.PcbLib; Height: 0.90MM; Library Path: Y:\MIS_DATABASE\Library\ALTIUM_TOOL\SCHEMATICS_PARTS\MS_DISCRETE_Library.schlib; Mfr_name: ECS INC; Mfr_part_number: ECS-.327-9-34QCS-TR; Mistral Part No: 130019040003-R; Package: SMD; Part_type: CRYSTAL; Project: J7ES_SOM_DUAL-LEO_PMIC; RoHS: RoHS; Temperature: -40°C+125°C; Tolerance: NA; Voltage: NA; Wattage: NA; Weight: 16mg; Datasheet: Y:\MIS_DATABASE\DATASHEETS\MISC\CRY_OSC\ECS-34Q.PDF
U18 = AM62A-EVM_SOC_FCBGA484: IC AM62A SK EVM SoC MICROPROCESSOR FCBGA484; Chkd/date: ALVY/060422; Crtd /date: ALVY/060422; Custom_Duty: 15%; Customs_HS_Code: 85423100; Distributor_name: NA; Distributor_part_number: NA; Footprint Path: Y:\MIS_DATABASE\Library\ALTIUM_TOOL\PCB_FOOTPRINTS\Altium_Footprint_Lib.PcbLib; Height: 2.65MM; Library Ref: AM62A-EVM_SoC_FCBGA484; Mfr_name: TEXAS INSTRUMENTS; Mfr_part_number: AM62A_SK_EVM_SoC; Mistral Part No: 141222040002; Package: FCBGA484; Part_type: ICS\DIGITAL\MICROPROCESSOR; Project: TI_AM62A_SK_EVM; RoHS: NA; Temperature: NA; Tolerance: NA; Voltage: NA; Wattage: NA; Weight: NA; Datasheet: Y:\MIS_DATABASE\DATASHEETS\ICS\DIGITAL\MICROCONTROLLER\AM62A_SK_EVM.PDF

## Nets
DGND: C42.2 C45.2 C148.2 C149.2 C151.2 C152.1 C157.1 C158.1 C160.1 C162.1 C163.1 C463.1 C465.1 C466.1 C467.1 C468.1 C471.1 C472.1 C474.2 C475.1 C476.1 C480.2 C486.1 C488.1 C490.1 C491.1 C493.1 C494.1 C495.1 C496.1 C497.2 C498.1 C499.1 C501.1 C502.1 C503.1 C504.1 C506.1 D7.1 J17.5(GND) J19.10 J19.12 J19.16 J19.20 R227.1 R520.1 R521.1 R524.1 R540.1 R553.1 R560.1 R567.1 R568.1 U46.4(GND) U48.1(GND1) U48.5(GND2) U48.10(AGND) U48.11(GND3) U48.13(TEST) U48.15(GND4) U48.25(GND5) U48.35(GND6) U48.47(GND7) U48.51(GND8) U106.4(GND) U107.3(GND) U110.1(~{1OE}) U110.10(GND1) U110.11(GND2) U110.16(~{2OE}) U113.5(VSS) U114.10(GND1) U114.11(GND2) U117.3(GND) U118.1(~{1OE}) U118.10(GND1) U118.11(GND2) U118.16(~{2OE}) U119.1(~{1OE}) U119.7(1A2) U119.9(2A2) U119.10(GND1) U119.11(GND2) U119.12(2B2) U119.14(1B2) U119.16(~{2OE}) U121.3(GND) U121.7(EP) U122.3(A2) U122.5(GND) U122.6(B2) U123.1(~{1OE}) U123.10(GND1) U123.11(GND2) U123.16(~{2OE}) ; also on sheet 9 10 11 12 13 14 15 16 17 18 19 20 21 22 23 24 25 26 27 28 32 33 34 35 36 37 38 39 40 41 42 43
VCC_1V8_FT4232: C157.2 C158.2 C476.2 C480.1 U48.12(VCORE) U48.37(VCORE) U48.49(VREGOUT) U48.64(VCORE)
VCC_3V3_FT4232: C152.2 C162.2 C163.2 C468.2 C475.2 C491.2 C493.2 C497.1 C499.2 C502.2 FL14.2 FL15.2 LD8.2(ANODE) R508.2 R509.2 R510.2 U48.20(VCCIO) U48.31(VCCIO) U48.42(VCCIO) U48.50(VREGIN) U48.56(VCCIO) U110.2(VCCB) U113.8(VCC) U118.2(VCCB) U119.2(VCCB) U121.1(OUT) U123.2(VCCB)
VCC_3V3_SYS: C151.1 C463.2 C465.2 C466.2 C467.2 C471.2 C472.2 C488.2 C490.2 C496.2 C501.2 C503.2 C506.2 J19.5 R223.1 R224.1 R504.2 R516.2 R528.2 R537.2 R541.2 R542.2 R552.1 R558.1 R561.2 R564.1 R565.2 R566.1 R570.1 U106.1(VCCA) U106.8(VCCB) U107.5(VCC) U110.3(VCCA) U114.2(VCCB) U114.3(VCCA) U117.5(VCC) U118.3(VCCA) U119.3(VCCA) U122.1(VCCA) U122.8(VCCB) U123.3(VCCA) ; also on sheet 9 10 12 13 17 18 19 21 22 23 25 26 28 32 33 34 35 36 37 38 39 40 41 42
BOOTMODE0: RA5.1 ; also on sheet 26
BOOTMODE1: RA5.2 ; also on sheet 26
BOOTMODE2: RA5.3 ; also on sheet 26
BOOTMODE3: RA5.4 ; also on sheet 26
BOOTMODE4: RA6.4 ; also on sheet 26
BOOTMODE5: RA6.3 ; also on sheet 26
BOOTMODE6: RA6.2 ; also on sheet 26
BOOTMODE7: RA6.1 ; also on sheet 26
BOOTMODE8: RA3.1 ; also on sheet 26
BOOTMODE9: RA3.2 ; also on sheet 26
BOOTMODE10: RA3.3 ; also on sheet 26
BOOTMODE11: RA3.4 ; also on sheet 26
BOOTMODE12: RA4.1 ; also on sheet 26
BOOTMODE13: RA4.2 ; also on sheet 26
BOOTMODE14: RA4.3 ; also on sheet 26
BOOTMODE15: RA4.4 ; also on sheet 26
CAN_IO_3V3: R523.1 R535.1 ; also on sheet 12 14 33 43
CPSW_ETH2_WAKE: U18.E13(WKUP_I2C0_SDA) ; also on sheet 23
EXP_GPIO0_32: R52.1 ; also on sheet 32
EXP_GPIO0_33: U18.L17(GPMC0_OEN_REN) ; also on sheet 32
EXP_GPIO0_36: U18.M18(GPMC0_BE1N) ; also on sheet 32
EXP_GPIO0_38: U18.R17(GPMC0_WAIT1) ; also on sheet 32
EXP_GPIO0_39: U18.K17(GPMC0_WPN) ; also on sheet 32
EXP_GPIO0_40/PR0_ECAP0_IN_APWM_OUT: U18.K18(GPMC0_DIR) ; also on sheet 32
EXP_GPIO0_41: U18.M19(GPMC0_CSN0) ; also on sheet 32
EXP_GPIO0_42: U18.M21(GPMC0_CSN1) ; also on sheet 32
FT4232_DO: R508.1 R513.2 U113.4(DO)
FT4232_EECLK: R509.1 U48.62(EECLK) U113.2(CLK)
FT4232_EECS: R510.1 U48.63(EECS) U113.1(CS)
FT4232_EEDATA: R513.1 U48.61(EEDATA) U113.3(DI)
FT4232_MCU_UART0_CTS_3V3: U48.53(DDBUS2) U110.12(2B2)
FT4232_MCU_UART0_RTS_3V3: U48.54(DDBUS3) U110.14(1B2)
FT4232_MCU_UART0_RX_3V3: U48.48(DDBUS0) U110.13(2B1)
FT4232_MCU_UART0_TX_3V3: U48.52(DDBUS1) U110.15(1B1)
FT4232_REF: R553.2 U48.6(REF)
FT4232_RESET: C160.2 R235.1 U48.14(~{RESET})
FT4232_SOC_UART0_RX_3V3: U48.16(ADBUS0) U119.13(2B1)
FT4232_SOC_UART0_TX_3V3: U48.17(ADBUS1) U119.15(1B1)
FT4232_SOC_UART1_CTS_3V3: U48.28(BDBUS2) U123.12(2B2)
FT4232_SOC_UART1_RTS_3V3: U48.29(BDBUS3) U123.14(1B2)
FT4232_SOC_UART1_RX_3V3: U48.26(BDBUS0) U123.13(2B1)
FT4232_SOC_UART1_TX_3V3: U48.27(BDBUS1) U123.15(1B1)
FT4232_USB_DM: J17.2(D-) U46.5(IO2) U48.7(DM)
FT4232_USB_DP: J17.3(D+) U46.3(IO1) U48.8(DP)
FT4232_USB_VBUS: C495.2 C498.2 D7.2 J17.1(VBUS) U46.1(VCC) U121.4(EN) U121.6(IN)
FT4232_WKUP_UART0_CTS_3V3: U48.40(CDBUS2) U118.12(2B2)
FT4232_WKUP_UART0_RTS_3V3: U48.41(CDBUS3) U118.14(1B2)
FT4232_WKUP_UART0_RX_3V3: U48.38(CDBUS0) U118.13(2B1)
FT4232_WKUP_UART0_TX_3V3: U48.39(CDBUS1) U118.15(1B1)
FT_PWREN#: R228.1 U48.60(~{PWREN})
HFOSC0_CLKOUT_32K: U18.B10(WKUP_CLKOUT0) ; also on sheet 17
JTAG_cTI_RTCK: J19.9 R562.1
JTAG_cTI_TCK: J19.11 R504.1 R519.1 U107.1(B) U117.1(B)
JTAG_DIR: R521.2 U114.4(1DIR) U114.5(2DIR)
JTAG_EMU0: J19.13 R564.2 U106.7(B1)
JTAG_EMU1: J19.14 R566.2 U106.6(B2)
JTAG_EMU_RSTn: J19.15 R552.2 ; also on sheet 41
JTAG_TCK: R499.1 R528.1 U114.14(1B2)
JTAG_TDI: J19.3 R542.1 U114.12(2B2)
JTAG_TDIS: J19.4 R567.2
JTAG_TDO: J19.7 U122.7(B1)
JTAG_TMS: J19.1 R537.1 U114.13(2B1)
JTAG_TRST#: J19.2 R524.2 U114.15(1B1)
MCASP1_ACLKX_BUF: U18.L19(GPMC0_BE0N_CLE) ; also on sheet 39
MCASP1_AFSX_BUF: U18.R18(GPMC0_WAIT0) ; also on sheet 39
MCASP1_AXR0_BUF: U18.K19(GPMC0_WEN) ; also on sheet 39
MCASP1_AXR2: R51.2 R52.2 U18.L18(GPMC0_ADVN_ALE)
MCASP1_AXR2_BUF: R51.1 ; also on sheet 39
MCU_UART0_CTS_3V3: U110.9(2A2) ; also on sheet 33
MCU_UART0_RTS_3V3: U110.7(1A2) ; also on sheet 33
MCU_UART0_RX_3V3: U110.8(2A1) ; also on sheet 33
MCU_UART0_TX_3V3: R523.2 U110.6(1A1) ; also on sheet 33
PMIC_LPM_EN0: TP41.1(TP) U18.D12(PMIC_LPM_EN0) ; also on sheet 12
PMIC_WDOG_TRIGG: U18.D13(WKUP_I2C0_SCL) ; also on sheet 12
PR0_PRU0_GPO0: RA5.8 U18.N21(GPMC0_AD0)
PR0_PRU0_GPO1: RA5.7 U18.N20(GPMC0_AD1)
PR0_PRU0_GPO2: RA5.6 U18.N19(GPMC0_AD2)
PR0_PRU0_GPO3: RA5.5 U18.N18(GPMC0_AD3)
PR0_PRU0_GPO4: RA6.5 U18.N17(GPMC0_AD4)
PR0_PRU0_GPO5: RA6.6 U18.P18(GPMC0_AD5)
PR0_PRU0_GPO6: RA6.7 U18.P19(GPMC0_AD6)
PR0_PRU0_GPO7: RA6.8 U18.P21(GPMC0_AD7)
SEL_XDS: U106.5(OE) ; also on sheet 28
SEL_XDS110_INV: J19.8 U107.2(A) U114.1(~{1OE}) U114.16(~{2OE}) U117.2(A) U122.4(~{OE}) ; also on sheet 28
SoC_EMU0: R224.2 U106.2(A1) ; also on sheet 28
SoC_EMU1: R223.2 U106.3(A2) ; also on sheet 28
SoC_I2C2_SCL: U18.M22(GPMC0_CSN2) ; also on sheet 37
SoC_I2C2_SDA: U18.M20(GPMC0_CSN3) ; also on sheet 37
SoC_RGMII_MDC: U18.V12(MDIO0_MDC) ; also on sheet 22 23
SoC_RGMII_MDIO: U18.V13(MDIO0_MDIO) ; also on sheet 22 23
SoC_TCK: R529.1 ; also on sheet 28
SoC_TDI: U114.9(2A2) ; also on sheet 28
SoC_TDO: U122.2(A1) ; also on sheet 28
SoC_TMS: U114.8(2A1) ; also on sheet 28
SoC_TRST#: U114.6(1A1) ; also on sheet 28
SOC_UART0_RX_3V3: U119.8(2A1) ; also on sheet 41
SOC_UART0_TX_3V3: R558.2 U119.6(1A1) ; also on sheet 41
SOC_UART1_CTS: TP91.1(TP) U123.9(2A2) ; also on sheet 36
SOC_UART1_RTS: TP90.1(TP) U123.7(1A2) ; also on sheet 36
SOC_UART1_RXD: TP72.1(TP) U123.8(2A1) ; also on sheet 36
SOC_UART1_TXD: R570.2 TP71.1(TP) U123.6(1A1) ; also on sheet 36
SoC_VOUT0_DATA16: RA3.8 U18.P22(GPMC0_AD8) ; also on sheet 40
SoC_VOUT0_DATA17: RA3.7 U18.R19(GPMC0_AD9) ; also on sheet 40
SoC_VOUT0_DATA18: RA3.6 U18.R20(GPMC0_AD10) ; also on sheet 40
SoC_VOUT0_DATA19: RA3.5 U18.R22(GPMC0_AD11) ; also on sheet 40
SoC_VOUT0_DATA20: RA4.8 U18.T22(GPMC0_AD12) ; also on sheet 40
SoC_VOUT0_DATA21: RA4.7 U18.R21(GPMC0_AD13) ; also on sheet 40
SoC_VOUT0_DATA22: RA4.6 U18.T20(GPMC0_AD14) ; also on sheet 40
SoC_VOUT0_DATA23: RA4.5 U18.T21(GPMC0_AD15) ; also on sheet 40
UART_SHIELD: J17.6(SH1) J17.7(SH2) J17.8(SH3) J17.9(SH4) R227.2
VPHY_3V3_FT4232: C486.2 FL14.1 U48.4(VPHY)
VPLL_3V3_FT4232: C494.2 FL15.1 R235.2 U48.9(VPLL)
VSEL_SD_SOC: U18.N22(GPMC0_CLK) ; also on sheet 12
WKUP_LFOSCO_XI: C45.1 U18.A8(WKUP_LFOSC0_XI) Y2.1
WKUP_LFOSCO_XO: C42.1 U18.A9(WKUP_LFOSC0_XO) Y2.2
WKUP_UART0_CTS_3V3: U18.C10(WKUP_UART0_CTSN) U118.9(2A2)
WKUP_UART0_RTS_3V3: U18.C8(WKUP_UART0_RTSN) U118.7(1A2)
WKUP_UART0_RX_3V3: U18.C9(WKUP_UART0_RXD) U118.8(2A1)
WKUP_UART0_TX_3V3: R535.2 U18.E9(WKUP_UART0_TXD) U118.6(1A1)
N16856152: C149.1 U48.3(OSCO) Y5.2
N16856224: C148.1 U48.2(OSCI) Y5.1
N16857368: C504.2 U121.2(NR/FB)
N16878333: R560.2 U119.5(2DIR)
N16878339: R561.1 U119.4(1DIR)
N16893179: R520.2 U110.5(2DIR)
N16893185: R516.1 U110.4(1DIR)
N16894003: R540.2 U118.5(2DIR)
N16894009: R541.1 U118.4(1DIR)
N16994873: R499.2 U107.4(Y)
N16994875: R562.2 U117.4(Y)
N16995245: C474.1 R519.2
N17378539: LD8.1(CATHODE) R228.2
N18571509: R568.2 U123.5(2DIR)
N18571515: R565.1 U123.4(1DIR)
N19806973: R529.2 U114.7(1A2)

Not connected (* = marked no-connect by the designer): J17 4(ID)*; J19 17* 18* 19*; U46 2(NC)*; U48 18(ADBUS2)* 19(ADBUS3)* 21(ADBUS4)* 22(ADBUS5)* 23(ADBUS6)* 24(ADBUS7)* 30(BDBUS4)* 32(BDBUS5)* 33(BDBUS6)* 34(BDBUS7)* 36(~{SUSPEND})* 43(CDBUS4)* 44(CDBUS5)* 45(CDBUS6)* 46(CDBUS7)* 55(DDBUS4)* 57(DDBUS5)* 58(DDBUS6)* 59(DDBUS7)*; U113 6(NC1)* 7(NC2)*; U121 5(NC)*

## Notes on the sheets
sheet 29
- cTI20 JTAG BUFFERS
- JTAG 20 PIN cTI CONNECTOR
- JTAG_DIR = H: A -> B
  JTAG_DIR = L: B -> A
  OE = H: output = Hi-Z
- CAD NOTE: Buffers U99 and U101
  need to be placed closer to the
  cTI-20pin connector J11 to reduce Stub length of the JTAG signals.
- Silk: cTI
- JTAG CLOCK BUFFER
- It should be connected to PORz of the SoC TBD
sheet 30
- FT4232 UART
- Silk: UART
- 90E
- LI0805H151R-10
- replaced 150E FB with 0E 0805
  (efft complience AM64x)
- FT4232: 5V to 3.3V@500mA LDO
- SILK SCREEN : SOC_UART1
  TXD
  RTS
  RXD
  CTS
- EEPROM
sheet 31
- SOC WKUP DOMAIN
- SOC GPMC
- ECS-.327-9-34QCS-TR
- @ GPMC0_AD8- AD15
  > HDMI 16 to 23 bits
- GPIO_43
- GPIO_44
- TO RI-pi or User Exp hdr
- GPIO0_40
- HDMI
- McASP1
- MUX
- AUDIO
- M.2 Wilink BT
- BUF
- BOOTMODE PINS
- NOTE: 1K Resistors are used to
  isolate the BOOTMODE control logic
  after the value is latched
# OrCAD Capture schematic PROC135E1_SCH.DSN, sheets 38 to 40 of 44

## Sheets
38 38. AUDIO CODEC: size C; title: AUDIO CODEC
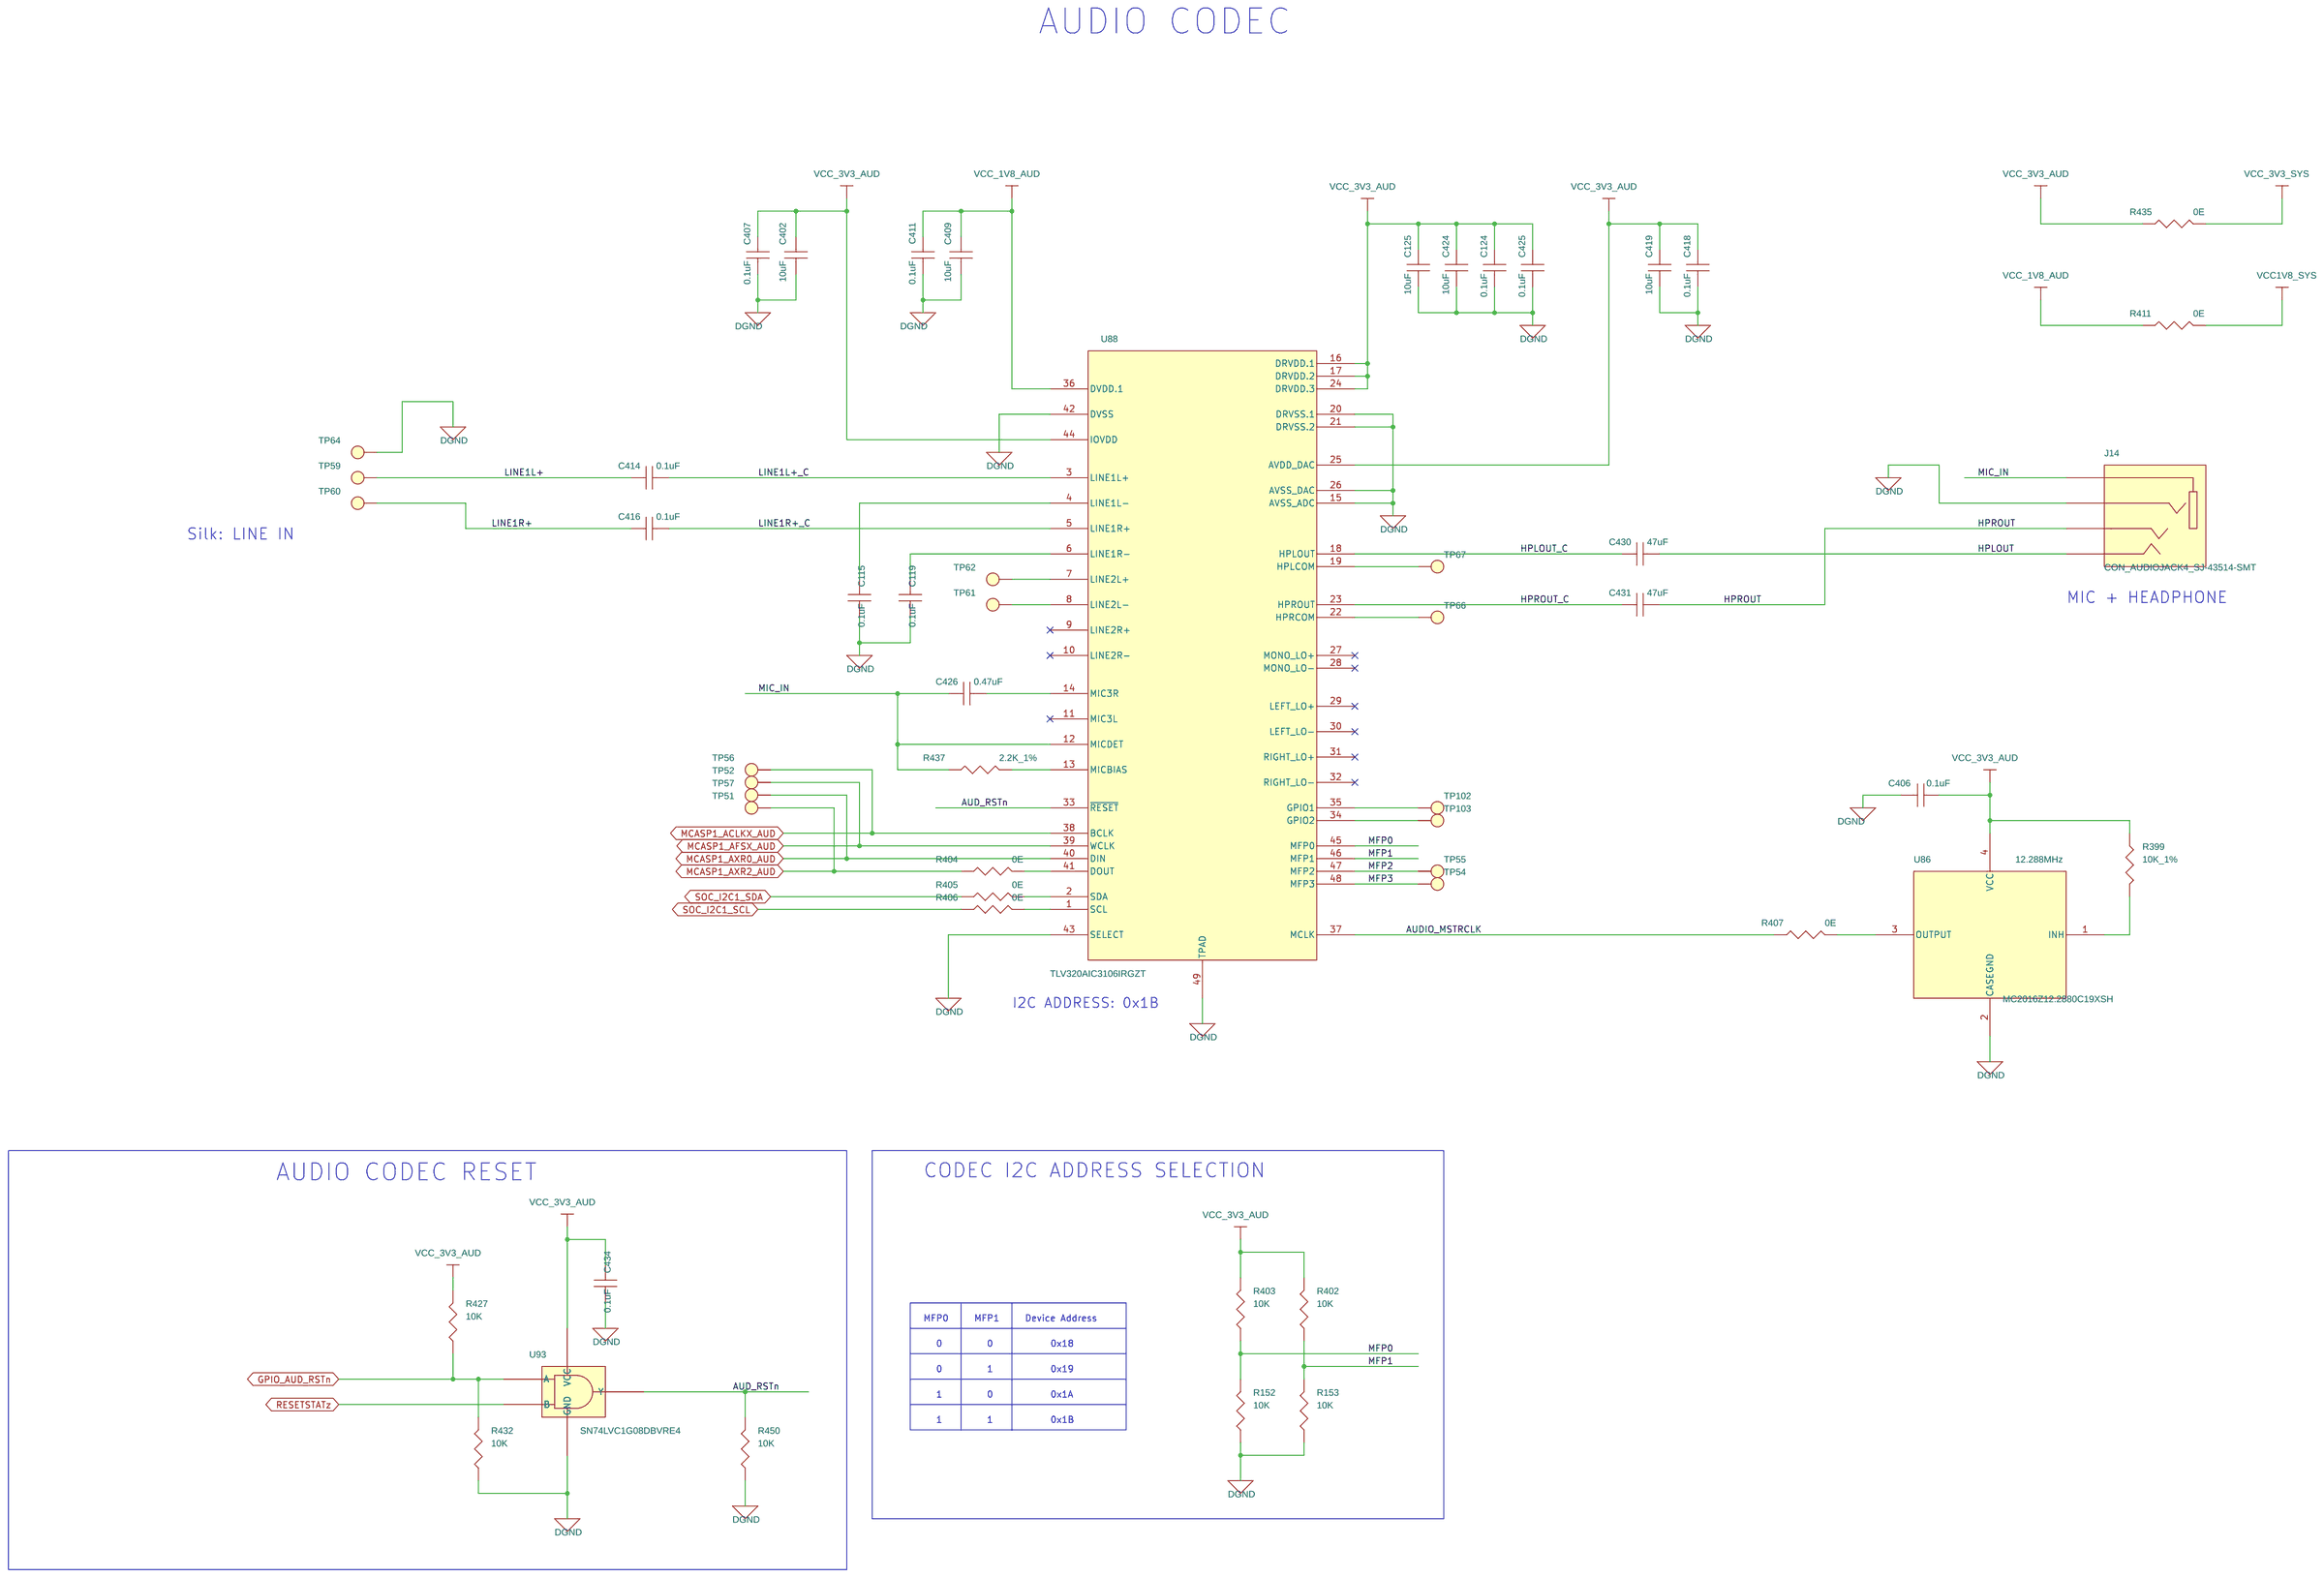
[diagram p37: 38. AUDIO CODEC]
39 39. IO EXPANDER: size C; title: IO EXPANDER
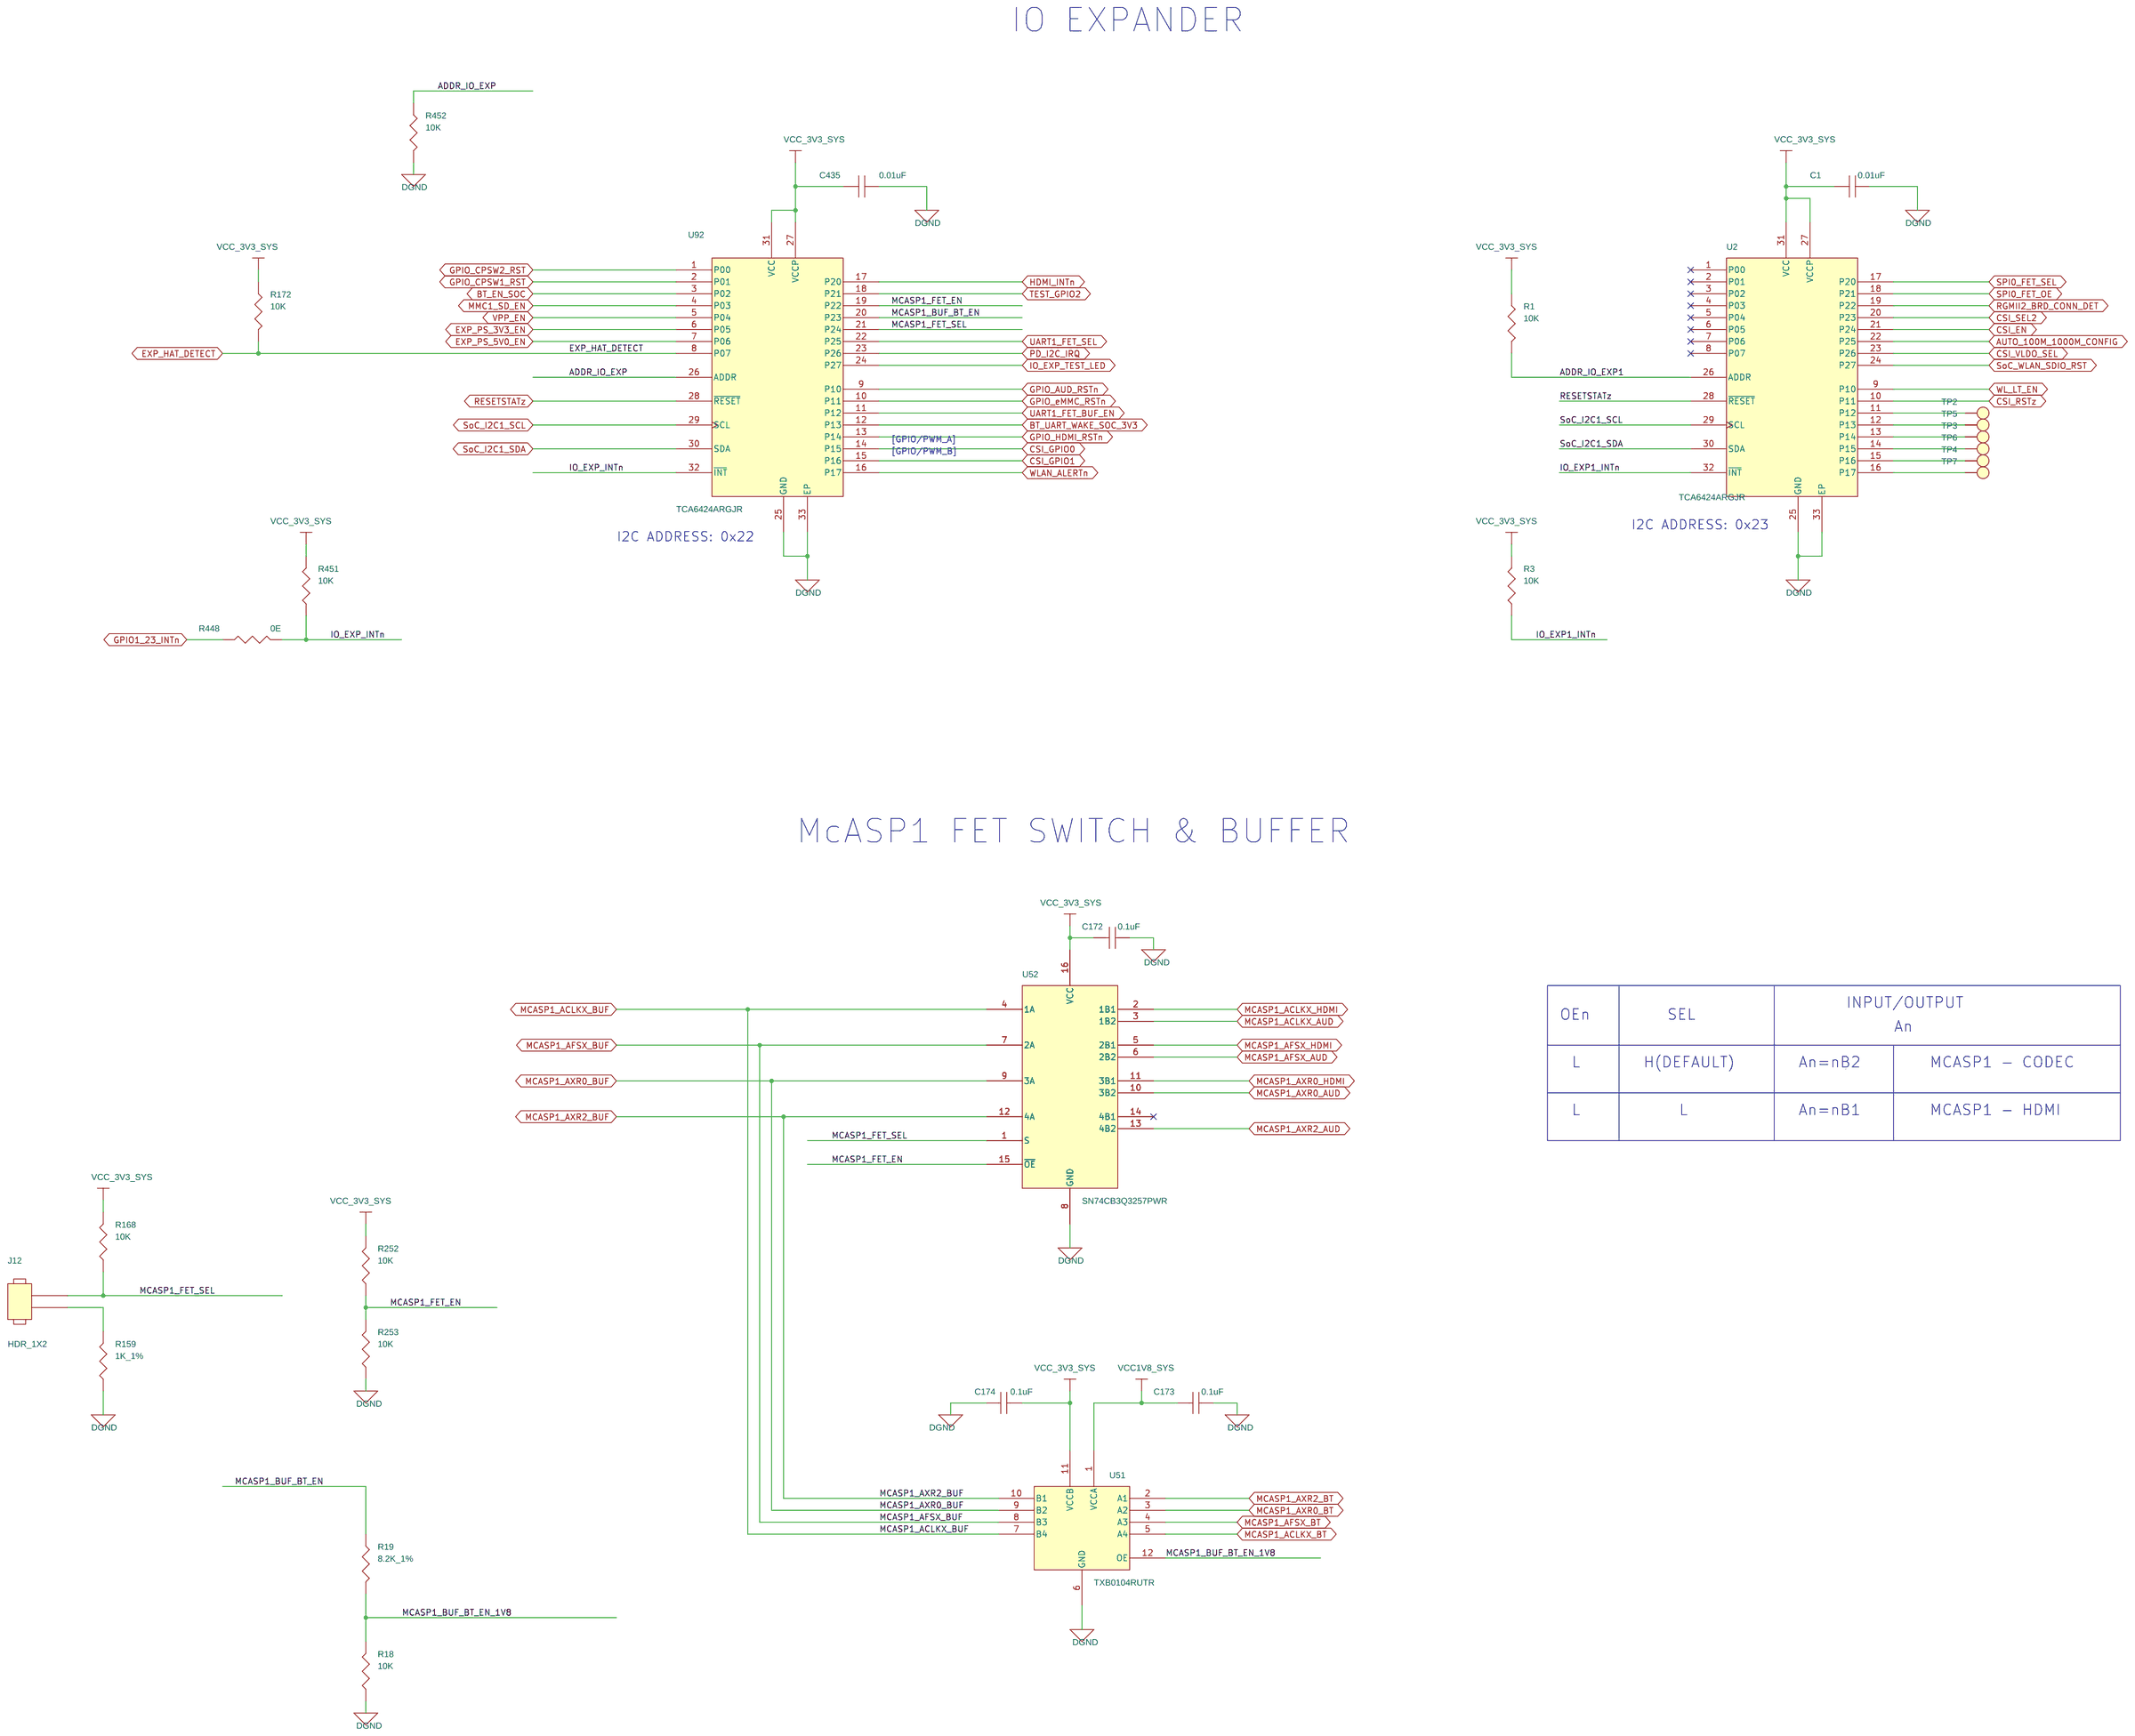
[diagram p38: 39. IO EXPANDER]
40 40. HDMI INTERFACE: size C; title: HDMI INTERFACE

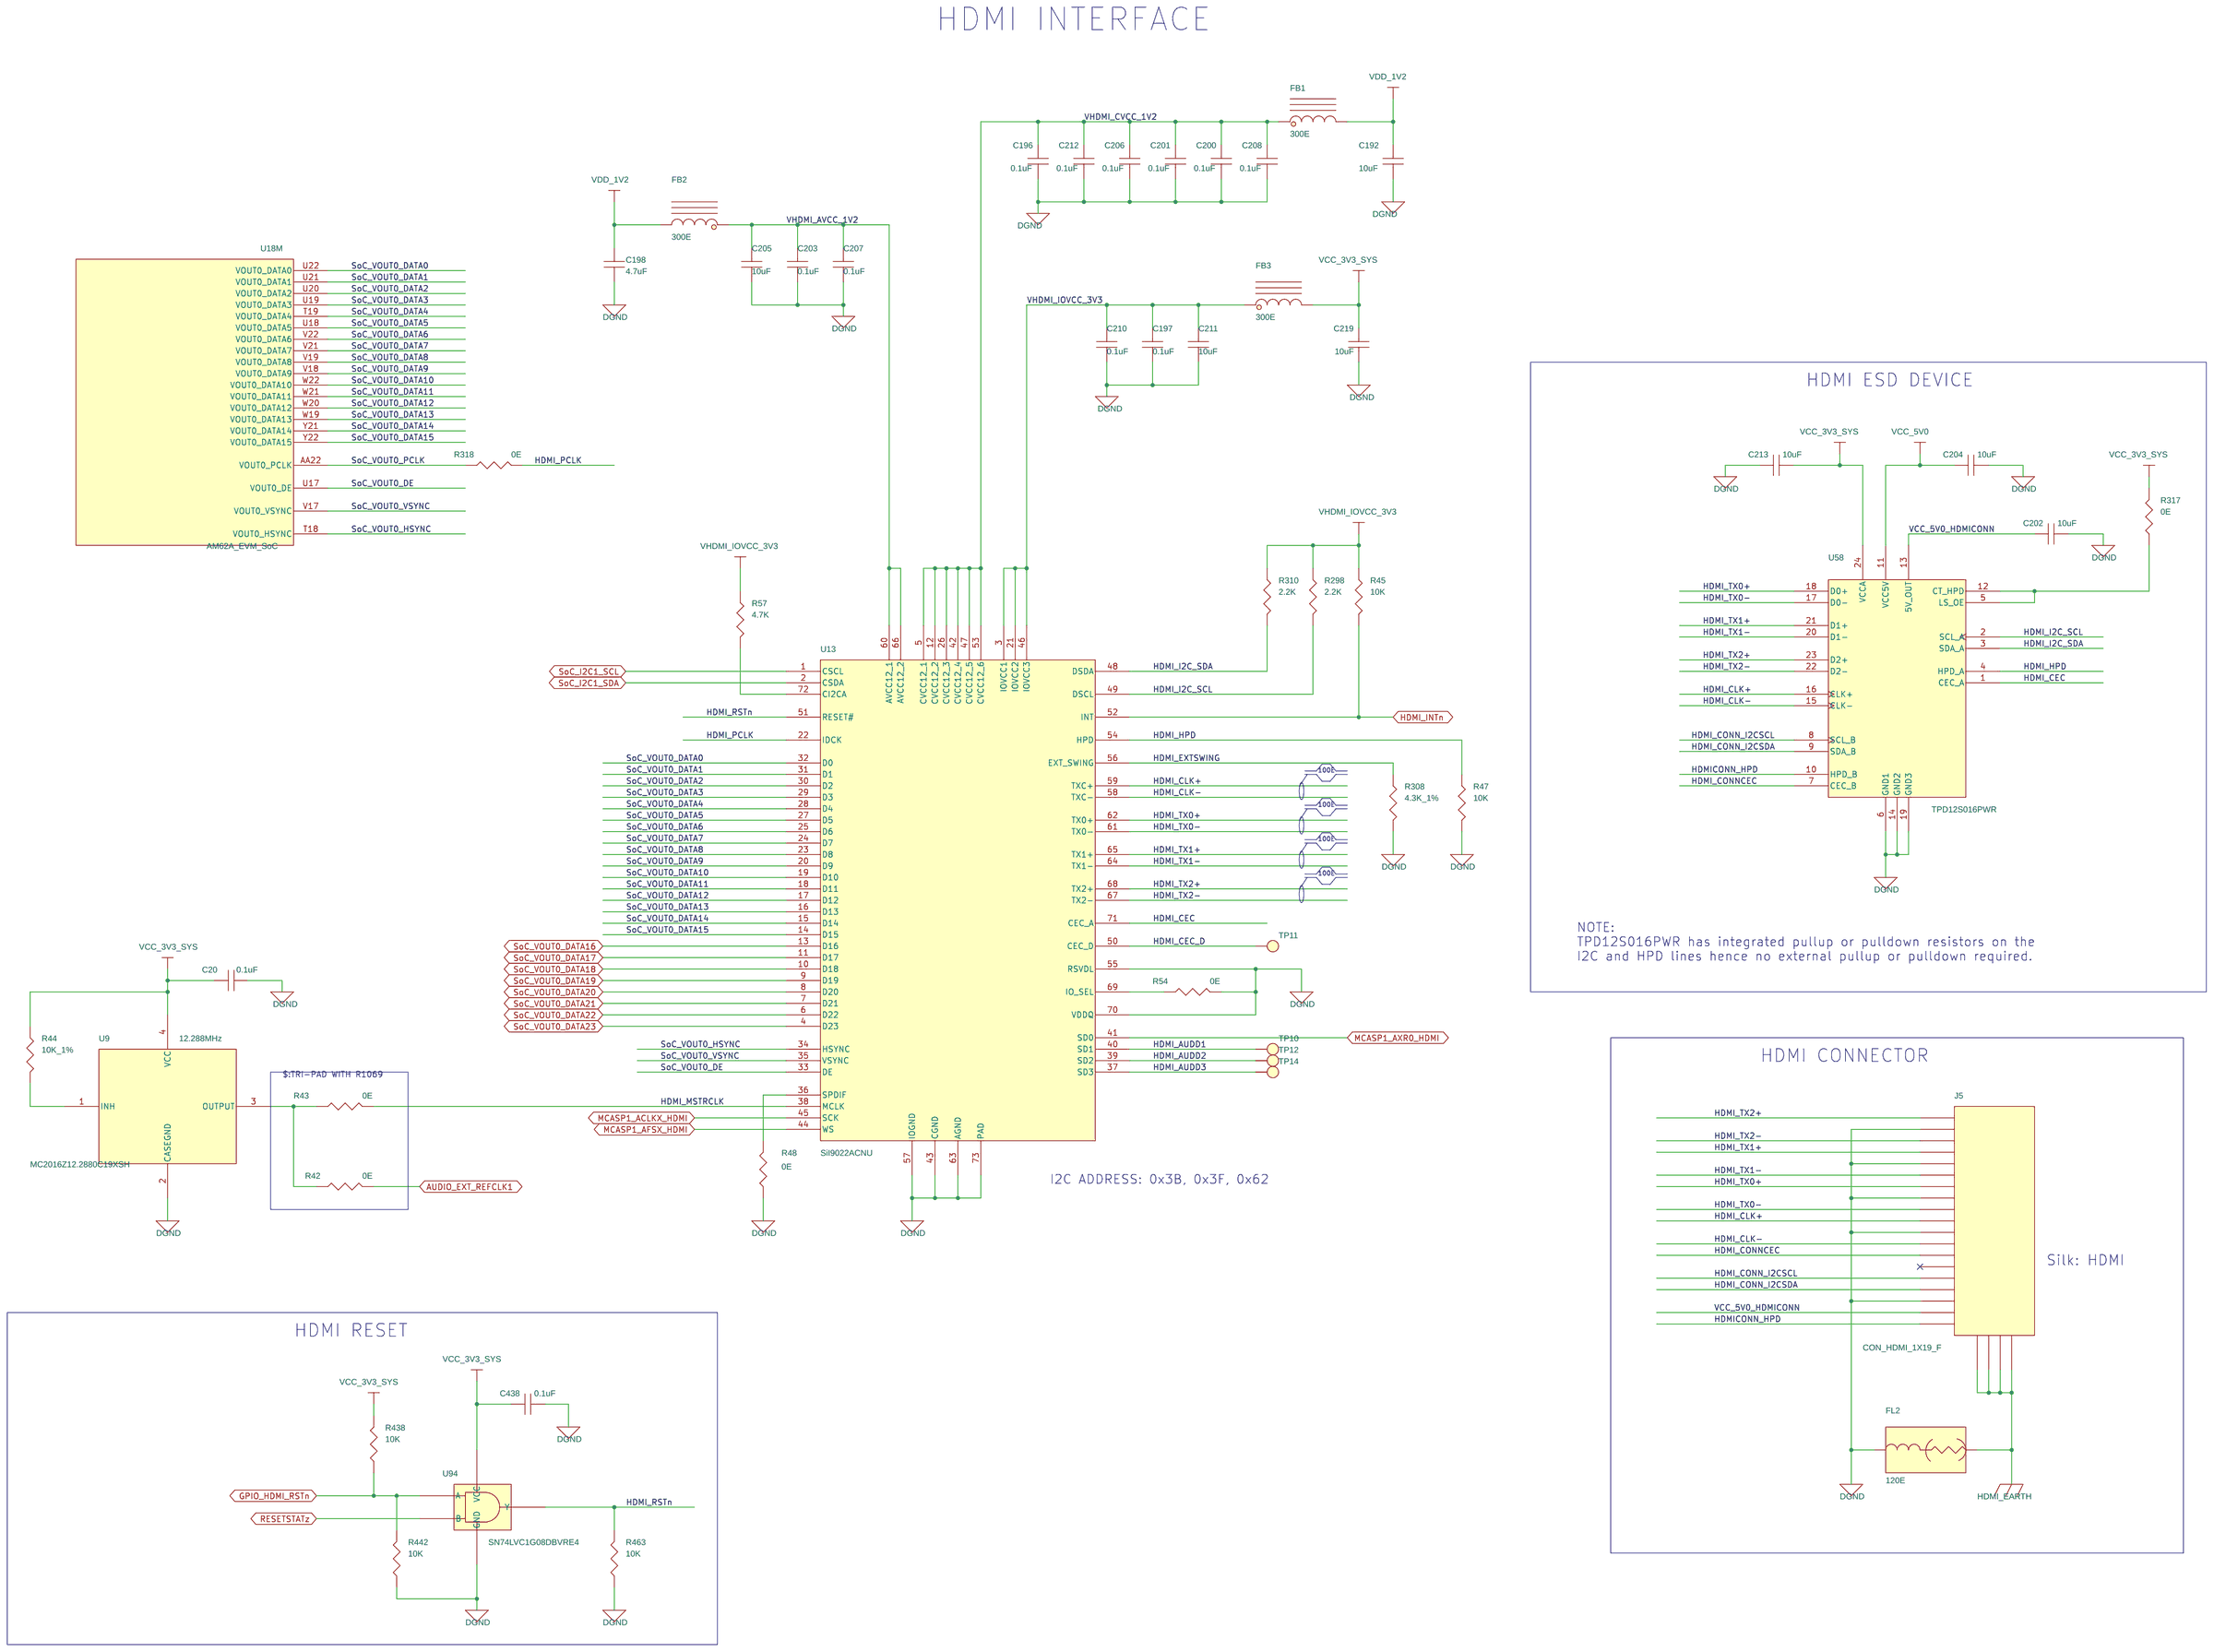
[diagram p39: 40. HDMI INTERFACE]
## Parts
sheet 32. USER EXPANSION CONNECTOR
U18  AM62A_EVM_SoC  [FBGA484_31-49_710X710_2-7]  (sections A,B,C,D,E,F,G,H,I,J,K,L,M,N,O,P,Q)
sheet 38. AUDIO CODEC
C115  0.1uF  [CAP0201_0-5]
C119  0.1uF  [CAP0201_0-5]
C124  0.1uF  [CAP0201_0-5]
C125  10uF  [CAP0402_0-75]
C402  10uF  [CAP0402_0-75]
C406  0.1uF  [CAP0201_0-5]
C407  0.1uF  [CAP0201_0-5]
C409  10uF  [CAP0402_0-75]
C411  0.1uF  [CAP0201_0-5]
C414  0.1uF  [CAP0402_0-75]
C416  0.1uF  [CAP0402_0-75]
C418  0.1uF  [CAP0201_0-5]
C419  10uF  [CAP0402_0-75]
C424  10uF  [CAP0402_0-75]
C425  0.1uF  [CAP0201_0-5]
C426  0.47uF  [CAP0402_0-75]
C430  47uF  [CAP1206_2]
C431  47uF  [CAP1206_2]
C434  0.1uF  [CAP0402_0-75]
J14  CON_AUDIOJACK4_SJ-43514-SMT  [CON_AV4_SJ-43514-SMT_S_R_S_5-1]
R152  10K  [RES0201_0-5]
R153  10K  [RES0201_0-5]
R399  10K_1%  [RES0201_0-5]
R402  10K  [RES0201_0-5]
R403  10K  [RES0201_0-5]
R404  0E  [RES0201_0-5]
R405  0E  [RES0201_0-5]
R406  0E  [RES0201_0-5]
R407  0E  [RES0201_0-5]
R411  0E  [RES0402_0-5]
R427  10K  [RES0201_0-5]
R432  10K  [RES0201_0-5]
R435  0E  [RES0402_0-5]
R437  2.2K_1%  [RES0201_0-5]
R450  10K  [RES0201_0-5]
TP51  TP20_SMD  [TP20_SMD]
TP52  TP20_SMD  [TP20_SMD]
TP54  TP20_SMD  [TP20_SMD]
TP55  TP20_SMD  [TP20_SMD]
TP56  TP20_SMD  [TP20_SMD]
TP57  TP20_SMD  [TP20_SMD]
TP59  THRU HOLE  [TP_40X65]
TP60  THRU HOLE  [TP_40X65]
TP61  TP20_SMD  [TP20_SMD]
TP62  TP20_SMD  [TP20_SMD]
TP64  THRU HOLE  [TP_40X65]
TP66  TP20_SMD  [TP20_SMD]
TP67  TP20_SMD  [TP20_SMD]
TP102  TP20_SMD  [TP20_SMD]
TP103  TP20_SMD  [TP20_SMD]
U86  12.288MHz  [OSC4_KC2016K_80X60_SMD_0-8]
U88  TLV320AIC3106IRGZT  [VQFN48_19-68_285X285]
U93  SN74LVC1G08DBVRE4  [SOT23-5]
sheet 39. IO EXPANDER
C1  0.01uF  [CAP0201_0-5]
C172  0.1uF  [CAP0201_0-5]
C173  0.1uF  [CAP0201_0-5]
C174  0.1uF  [CAP0201_0-5]
C435  0.01uF  [CAP0201_0-5]
J12  HDR_1X2  [HDR_1X2_90120-0122_S_T_5-6]
R1  10K  [RES0201_0-5]
R3  10K  [RES0201_0-5]
R18  10K  [RES0201_0-5]
R19  8.2K_1%  [RES0201_0-5]
R159  1K_1%  [RES0402_0-5]
R168  10K  [RES0201_0-5]
R172  10K  [RES0201_0-5]
R252  10K  [RES0201_0-5]
R253  10K  [RES0201_0-5]
R448  0E  [RES0201_0-5]
R451  10K  [RES0201_0-5]
R452  10K  [RES0201_0-5]
TP2  TP20_SMD  [TP20_SMD]
TP3  TP20_SMD  [TP20_SMD]
TP4  TP20_SMD  [TP20_SMD]
TP5  TP20_SMD  [TP20_SMD]
TP6  TP20_SMD  [TP20_SMD]
TP7  TP20_SMD  [TP20_SMD]
U2  TCA6424ARGJR  [QFN32_19-68_200X200]
U51  TXB0104RUTR  [UQFN12_TXB0104RUT_70X80_0-6]
U52  SN74CB3Q3257PWR  [TSSOP16_25-59_205X180]
U92  TCA6424ARGJR  [QFN32_19-68_200X200]
sheet 40. HDMI INTERFACE
C20  0.1uF  [CAP0201_0-5]
C192  10uF  [CAP0402_0-75]
C196  0.1uF  [CAP0201_0-5]
C197  0.1uF  [CAP0201_0-5]
C198  4.7uF  [CAP0402_0-75]
C200  0.1uF  [CAP0201_0-5]
C201  0.1uF  [CAP0201_0-5]
C202  10uF  [CAP0402_0-75]
C203  0.1uF  [CAP0201_0-5]
C204  10uF  [CAP0402_0-75]
C205  10uF  [CAP0402_0-75]
C206  0.1uF  [CAP0201_0-5]
C207  0.1uF  [CAP0201_0-5]
C208  0.1uF  [CAP0201_0-5]
C210  0.1uF  [CAP0201_0-5]
C211  10uF  [CAP0402_0-75]
C212  0.1uF  [CAP0201_0-5]
C213  10uF  [CAP0402_0-75]
C219  10uF  [CAP0402_0-75]
C438  0.1uF  [CAP0402_0-75]
FB1  300E  [IND0603]
FB2  300E  [IND0603]
FB3  300E  [IND0603]
FL2  120E  [EMIFIL_BLM15A_0402_0-6]
J5  CON_HDMI_1X19_F  [CON_19X1_10029449-001RLF_S_R_S_6-3]
R42  0E  [RES0201_0-5]
R43  0E  [RES0201_0-5]
R44  10K_1%  [RES0201_0-5]
R45  10K  [RES0201_0-5]
R47  10K  [RES0201_0-5]
R48  0E  [RES0201_0-5]
R54  0E  [RES0201_0-5]
R57  4.7K  [RES0201_0-5]
R298  2.2K  [RES0402_0-5]
R308  4.3K_1%  [RES0402_0-5]
R310  2.2K  [RES0402_0-5]
R317  0E  [RES0201_0-5]
R318  0E  [RES0201_0-5]
R438  10K  [RES0201_0-5]
R442  10K  [RES0201_0-5]
R463  10K  [RES0201_0-5]
TP10  TP20_SMD  [TP20_SMD]
TP11  TP20_SMD  [TP20_SMD]
TP12  TP20_SMD  [TP20_SMD]
TP14  TP20_SMD  [TP20_SMD]
U9  12.288MHz  [OSC4_KC2016K_80X60_SMD_0-8]
U13  SiI9022ACNU  [QFN72_19-68_390X390_0-9]
U58  TPD12S016PWR  [TSSOP24_25-59_315X180_1-2]
U94  SN74LVC1G08DBVRE4  [SOT23-5]

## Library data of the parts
U18 = AM62A-EVM_SOC_FCBGA484: IC AM62A SK EVM SoC MICROPROCESSOR FCBGA484; Chkd/date: ALVY/060422; Crtd /date: ALVY/060422; Custom_Duty: 15%; Customs_HS_Code: 85423100; Distributor_name: NA; Distributor_part_number: NA; Footprint Path: Y:\MIS_DATABASE\Library\ALTIUM_TOOL\PCB_FOOTPRINTS\Altium_Footprint_Lib.PcbLib; Height: 2.65MM; Library Ref: AM62A-EVM_SoC_FCBGA484; Mfr_name: TEXAS INSTRUMENTS; Mfr_part_number: AM62A_SK_EVM_SoC; Mistral Part No: 141222040002; Package: FCBGA484; Part_type: ICS\DIGITAL\MICROPROCESSOR; Project: TI_AM62A_SK_EVM; RoHS: NA; Temperature: NA; Tolerance: NA; Voltage: NA; Wattage: NA; Weight: NA; Datasheet: Y:\MIS_DATABASE\DATASHEETS\ICS\DIGITAL\MICROCONTROLLER\AM62A_SK_EVM.PDF
C115 C119 C124 C196 C197 C200 C201 C203 C206-C208 C210 C212 C406 C407 C411 C418 C425 = CAP: CAP CERAMIC 0.1uF 16V 10% X5R 0201; Chkd/date: MANIRAJA/230118; Crtd /date: MANIRAJA/230118; Custom_Duty: 15%; Customs_HS_Code: 85322990; Distributor_name: DIGIKEY; Distributor_part_number: 490-14305-1-ND; Footprint Path: Y:\MIS_DATABASE\Library\ALTIUM_TOOL\PCB_FOOTPRINTS\Altium_Footprint_Lib.PcbLib; Height: 0.33MM; Library Path: Y:\MIS_DATABASE\Library\ALTIUM_TOOL\SCHEMATICS_PARTS\MS_DISCRETE_Library.schlib; Mfr_name: MURATA; Mfr_part_number: GRM033R61C104KE14D; Mistral Part No: 120009030072-R; Package: 0201; Part_type: CAPACITORS\CERAMIC; Project: TI_MAXIE_CPB; RoHS: RoHS; Temperature: -55°C+85°C; Tolerance: 10%; Voltage: 16V; Wattage: NA; Weight: 0.33mg; Datasheet: Y:\MIS_DATABASE\DATASHEETS\CAPACITORS\GRM033R61C104KE14.PDF
C125 C192 C202 C204 C205 C211 C213 C219 C402 C409 C419 C424 = CAP: CAP CERAMIC 10uF 10V 20% X5R 0402; Chkd/date: MANIRAJA/300520; Crtd /date: ALVY/260520; Custom_Duty: 15%; Customs_HS_Code: 85322990; Distributor_name: DIGIKEY; Distributor_part_number: 490-GRM155R61A106ME11DTR-ND; Footprint Path: Y:\MIS_DATABASE\Library\ALTIUM_TOOL\PCB_FOOTPRINTS\Altium_Footprint_Lib.PcbLib; Height: 0.55MM; Library Path: Y:\MIS_DATABASE\Library\ALTIUM_TOOL\SCHEMATICS_PARTS\MS_DISCRETE_Library.schlib; Mfr_name: MURATA; Mfr_part_number: GRM155R61A106ME11D; Mistral Part No: 120013110019-R; Package: 0402; Part_type: CAPACITORS\CERAMIC; Project: QCS610_NANOSOM; RoHS: RoHS; Temperature: -55°C+85°C; Tolerance: 20%; Voltage: 10V; Wattage: NA; Weight: 3.1mg; Datasheet: Y:\MIS_DATABASE\DATASHEETS\CAPACITORS\MURATA-GXX-SER_NOV17.PDF
C414 C416 C434 = CAP: CAP CERAMIC 0.1uF 50V 10% X7R 0402; Chkd/date: MANIRAJA/261020; Crtd /date: ALVY/211020; Custom_Duty: 15%; Customs_HS_Code: 85322990; Distributor_name: DIGIKEY; Distributor_part_number: 490-10700-1-ND; Footprint Path: Y:\MIS_DATABASE\Library\ALTIUM_TOOL\PCB_FOOTPRINTS\Altium_Footprint_Lib.PcbLib; Height: 0.55MM; Library Path: Y:\MIS_DATABASE\Library\ALTIUM_TOOL\SCHEMATICS_PARTS\MS_DISCRETE_Library.schlib; Mfr_name: MURATA; Mfr_part_number: GRM155R71H104KE14D; Mistral Part No: 120011100014-R; Package: 0402; Part_type: CAPACITORS\CERAMIC; Project: J7_CP; RoHS: RoHS; Temperature: -55°C+125°C; Tolerance: 10%; Voltage: 50V; Wattage: NA; Weight: 3.1mg; Datasheet: Y:\MIS_DATABASE\DATASHEETS\CAPACITORS\GRM155R71H104KE14.PDF
C426 = CAP: CAP CERAMIC 0.47uF 10V 10% X7R 0402; Chkd/date: MANIRAJA/310821; Crtd /date: ALVY/310821; Custom_Duty: 15%; Customs_HS_Code: 85322990; Distributor_name: DIGIKEY; Distributor_part_number: 490-14366-1-ND; Footprint Path: Y:\MIS_DATABASE\Library\ALTIUM_TOOL\PCB_FOOTPRINTS\Altium_Footprint_Lib.PcbLib; Height: 0.55MM; Library Path: Y:\MIS_DATABASE\Library\ALTIUM_TOOL\SCHEMATICS_PARTS\MS_DISCRETE_Library.schlib; Mfr_name: MURATA; Mfr_part_number: GRM155R71A474KE01D; Mistral Part No: 120021060019-R; Package: 0402; Part_type: CAPACITORS\CERAMIC; Project: TI_AM335x SK_BRD; RoHS: RoHS; Temperature: -55°C+125°C; Tolerance: 10%; Voltage: 10V; Wattage: NA; Weight: 1.5mg; Datasheet: Y:\MIS_DATABASE\DATASHEETS\CAPACITORS\GRM155R71A474KE01.PDF
C430 C431 = CAP: CAP CERAMIC 47uF 10V 20% X5R 1206; Chkd/date: USMAN/121213; Crtd /date: USMAN/121213; Custom_Duty: 15%; Customs_HS_Code: 85322990; Distributor_name: DIGIKEY; Distributor_part_number: 490-5528-1-ND; Footprint Path: Y:\MIS_DATABASE\Library\ALTIUM_TOOL\PCB_FOOTPRINTS\Altium_Footprint_Lib.PcbLib; Height: 1.80MM; Library Path: Y:\MIS_DATABASE\Library\ALTIUM_TOOL\SCHEMATICS_PARTS\MS_DISCRETE_Library.schlib; Mfr_name: MURATA; Mfr_part_number: GRM31CR61A476ME15L; Mistral Part No: 120013120015-R; Package: 1206; Part_type: CAPACITORS\CERAMIC; Project: DMP; RoHS: RoHS; Temperature: -55°C+85°C; Tolerance: 20%; Voltage: 10V; Wattage: NA; Weight: 40mg; Datasheet: Y:\MIS_DATABASE\DATASHEETS\CAPACITORS\MURATA-GXX-SER_NOV17.PDF
J14 = CON_AUDIOJACK4_SJ-43514-SMT: CON AUDIO JACK 4POS FEMALE RT SMD; Chkd/date: MAZHAR/230211; Crtd /date: MUDDU/300610; Custom_Duty: 24%; Customs_HS_Code: 85369090; Distributor_name: DIGIKEY; Distributor_part_number: CP-43514SJCT-ND; Footprint Path: Y:\MIS_DATABASE\Library\ALTIUM_TOOL\PCB_FOOTPRINTS\Altium_Footprint_Lib.PcbLib; Height: 5.10MM; Library Path: Y:\MIS_DATABASE\Library\ALTIUM_TOOL\SCHEMATICS_PARTS\MS_CONNECTOR_Library.schlib; Mfr_name: CUI INC; Mfr_part_number: SJ-43514-SMT-TR; Mistral Part No: 150010060028-R; Package: SMD; Part_type: CONNECTOR\JACK; Project: PB_BUGBASE; RoHS: RoHS; Temperature: -25°C+85°C; Tolerance: NA; Voltage: NA; Wattage: NA; Weight: 1100mg; Datasheet: Y:\MIS_DATABASE\DATASHEETS\CONNECTORS\SJ-4351X-SMT.PDF
R1 R3 R18 R45 R47 R152 R153 R168 R172 R252 R253 R402 R403 R427 R432 R438 R442 R450-R452 R463 = RESISTOR: RES 10K 1/20W 5% 0201; Chkd/date: MANIRAJA/050517; Crtd /date: MANIRAJA/050517; Custom_Duty: 15%; Customs_HS_Code: 85332119; Distributor_name: DIGIKEY; Distributor_part_number: 311-10KNCT-ND; Footprint Path: Y:\MIS_DATABASE\Library\ALTIUM_TOOL\PCB_FOOTPRINTS\Altium_Footprint_Lib.PcbLib; Height: 0.26MM; Library Path: Y:\MIS_DATABASE\Library\ALTIUM_TOOL\SCHEMATICS_PARTS\MS_DISCRETE_Library.schlib; Mfr_name: YAGEO AMERICA; Mfr_part_number: RC0201JR-0710KL; Mistral Part No: 110010070051-R; Package: 0201; Part_type: RESISTORS\FIXED; Project: GOLDEN-I LITE; RoHS: RoHS; Temperature: -55°C+125°C; Tolerance: 5%; Voltage: NA; Wattage: 1/20W; Weight: 0.17mg; Datasheet: Y:\MIS_DATABASE\DATASHEETS\RESISTORS\RCXXXXL-SER_MAR18.PDF
R44 R399 = RESISTOR: RES 10K 1/20W 1% 0201; Chkd/date: VASANTHA/270117; Crtd /date: MANIRAJA/270117; Custom_Duty: 15%; Customs_HS_Code: 85332119; Distributor_name: DIGIKEY; Distributor_part_number: 311-10.0KMCT-ND; Footprint Path: Y:\MIS_DATABASE\Library\ALTIUM_TOOL\PCB_FOOTPRINTS\Altium_Footprint_Lib.PcbLib; Height: 0.26MM; Library Path: Y:\MIS_DATABASE\Library\ALTIUM_TOOL\SCHEMATICS_PARTS\MS_DISCRETE_Library.schlib; Mfr_name: YAGEO AMERICA; Mfr_part_number: RC0201FR-0710KL; Mistral Part No: 110011040018-R; Package: 0201; Part_type: RESISTORS\FIXED; Project: GOLDEN-I LITE; RoHS: RoHS; Temperature: -55°C+125°C; Tolerance: 1%; Voltage: NA; Wattage: 1/20W; Weight: 0.17mg; Datasheet: Y:\MIS_DATABASE\DATASHEETS\RESISTORS\RCXXXXL-SER_MAR18.PDF
R42 R43 R48 R54 R317 R404-R407 R448 = RESISTOR: RES 0E 1/20W 5% 0201; Chkd/date: NAVEED/301214; Crtd /date: MUDDU/120710; Custom_Duty: 15%; Customs_HS_Code: 85332119; Distributor_name: DIGIKEY; Distributor_part_number: 311-0.0NCT-ND; Footprint Path: Y:\MIS_DATABASE\Library\ALTIUM_TOOL\PCB_FOOTPRINTS\Altium_Footprint_Lib.PcbLib; Height: 0.26MM; Library Path: Y:\MIS_DATABASE\Library\ALTIUM_TOOL\SCHEMATICS_PARTS\MS_DISCRETE_Library.schlib; Mfr_name: YAGEO AMERICA; Mfr_part_number: RC0201JR-070RL; Mistral Part No: 110010070067-R; Package: 0201; Part_type: RESISTORS\FIXED; Project: PB_BUGBASE; RoHS: RoHS; Temperature: -55°C+125°C; Tolerance: 5%; Voltage: NA; Wattage: 1/20W; Weight: 0.17mg; Datasheet: Y:\MIS_DATABASE\DATASHEETS\RESISTORS\RCXXXXL-SER_MAR18.PDF
R411 R435 = RESISTOR: RES 0E 1/16W JUMPER 0402; Chkd/date: VASANTHA/201216; Crtd /date: MUDDU/190810; Custom_Duty: 15%; Customs_HS_Code: 85332119; Distributor_name: DIGIKEY; Distributor_part_number: 541-0.0JCT-ND; Footprint Path: Y:\MIS_DATABASE\Library\ALTIUM_TOOL\PCB_FOOTPRINTS\Altium_Footprint_Lib.PcbLib; Height: 0.40MM; Library Path: Y:\MIS_DATABASE\Library\ALTIUM_TOOL\SCHEMATICS_PARTS\MS_DISCRETE_Library.schlib; Mfr_name: VISHAY; Mfr_part_number: CRCW04020000Z0ED; Mistral Part No: 110010080019-R; Package: 0402; Part_type: RESISTORS\FIXED; Project: PB_BUGBASE; RoHS: RoHS; Temperature: -55°C+155°C; Tolerance: NA; Voltage: NA; Wattage: 1/16W; Weight: 0.65mg; Datasheet: Y:\MIS_DATABASE\DATASHEETS\RESISTORS\CRCW0603.PDF
R437 = RESISTOR: RES 2.2K 1/20W 1% 0201; Chkd/date: VASANTHA/270117; Crtd /date: MANIRAJA/270117; Custom_Duty: 15%; Customs_HS_Code: 85332119; Distributor_name: DIGIKEY; Distributor_part_number: YAG2572CT-ND; Footprint Path: Y:\MIS_DATABASE\Library\ALTIUM_TOOL\PCB_FOOTPRINTS\Altium_Footprint_Lib.PcbLib; Height: 0.26MM; Library Path: Y:\MIS_DATABASE\Library\ALTIUM_TOOL\SCHEMATICS_PARTS\MS_DISCRETE_Library.schlib; Mfr_name: YAGEO AMERICA; Mfr_part_number: RC0201FR-072K2L; Mistral Part No: 110017010016-R; Package: 0201; Part_type: RESISTORS\FIXED; Project: GOLDEN-I LITE; RoHS: RoHS; Temperature: -55°C+125°C; Tolerance: 1%; Voltage: NA; Wattage: 1/20W; Weight: 0.17mg; Datasheet: Y:\MIS_DATABASE\DATASHEETS\RESISTORS\RCXXXXL-SER_MAR18.PDF
TP10-TP12 TP14 TP51 TP52 TP54-TP57 TP61 TP62 TP66 TP67 TP102 TP103 = TESTPOINT: TESTPOINT CIR 20 SMD; Chkd/date: SHREESHAIL/171006; Crtd /date: MAZHAR/171006; Custom_Duty: NA; Customs_HS_Code: NA; Distributor_name: NA; Distributor_part_number: NA; Footprint Path: Y:\MIS_DATABASE\Library\ALTIUM_TOOL\PCB_FOOTPRINTS\Altium_Footprint_Lib.PcbLib; Height: NA; Library Path: Y:\MIS_DATABASE\Library\ALTIUM_TOOL\SCHEMATICS_PARTS\MS_DISCRETE_Library.schlib; MECHANICAL 3D STEP FILE: NA; Mfr_name: LOCAL; Mistral Part No: NA; Package: SMD; Project: BT MODULE_CSRBC04; RoHS: NA; Temperature: NA; Tolerance: NA; Voltage: NA; Wattage: NA; Weight: NA; Datasheet: NA
TP59 TP60 TP64 = TESTPOINT: TESTPOINT 1.0MM DRILL PTH; Chkd/date: MAZHAR/271211; Crtd /date: SHREESHAIL/041005; Distributor_name: NA; Distributor_part_number: NA; Height: NA; Mfr_name: LOCAL; Mistral Part No: 130009030938; Package: THRU-HOLE; Project: HSE; Datasheet: NA
U9 U86 = OSC4_KC7050K: OSC 12.288MHz CMOS AUTO SMD; Chkd/date: ALVY/310521; Crtd /date: TAMILARASU/310522; Custom_Duty: 24%; Customs_HS_Code: 85437099; Distributor_name: DIGIKEY; Distributor_part_number: 478-MC2016Z12.2880C19XSHCT-ND; Footprint Path: Y:\MIS_DATABASE\Library\ALTIUM_TOOL\PCB_FOOTPRINTS\Altium_Footprint_Lib.PcbLib; Height: 0.80MM; Library Path: Y:\MIS_DATABASE\Library\ALTIUM_TOOL\SCHEMATICS_PARTS\MS_DISCRETE_Library.schlib; Mfr_name: KYOCERA; Mfr_part_number: MC2016Z12.2880C19XSH; Mistral Part No: 130022050049-R; Package: SMD; Part_type: OSCILLATORS; Project: TI_AM62A_SK_EVM; RoHS: RoHS; Temperature: -40°C+125°C; Tolerance: NA; Voltage: NA; Wattage: NA; Weight: NA; Datasheet: Y:\MIS_DATABASE\DATASHEETS\MISC\CRY_OSC\MC-Z-SER.PDF
U88 = TLV320AIC3106IRGZT_VQFN48: IC LOW-POWER STEREO AUDIO CODEC VQFN48; Chkd/date: SUHAS/261010; Crtd /date: MUDDU/150610; Custom_Duty: 15%; Customs_HS_Code: 85423100; Distributor_name: DIGIKEY; Distributor_part_number: TLV320AIC3106IRGZT-ND; Height: 1.00MM; Mfr_name: TEXAS INSTRUMENTS; Mistral Part No: 143010060003-R; Package: VQFN48; Part_type: ICS\TELECOM\CODEC; Project: CENTAURUS; RoHS: Sb/ Br FREE; Temperature: -40°C+85°C; Weight: NA; Datasheet: Y:\MIS_DATABASE\DATASHEETS\ICS\TELECOM\TLV320AIC3106IRGZT.PDF
U93 U94 = SN74LVC1G08DBVRE4_SOT23-5: IC SINGLE 2-INPUT POSITIVE AND GATE SOT23-5; Chkd/date: SUHAS/221010; Crtd /date: USMAN/151008; Custom_Duty: 15%; Customs_HS_Code: 85423100; Distributor_name: DIGIKEY; Distributor_part_number: SN74LVC1G08DBVRE4-ND; Height: 1.45MM; Mfr_name: TEXAS INSTRUMENTS; Mistral Part No: 141009060026-R; Part_type: ICS\DIGITAL\GATES; Project: KHAN_MAIN; RoHS: Sb/ Br FREE; Temperature: -40°C+85°C; Datasheet: Y:\MIS_DATABASE\DATASHEETS\ICS\DIGITAL\GATES\SN74LVC1G08.PDF
C1 C435 = CAP: CAP CERAMIC 0.01uF 25V 10% X5R 0201; Chkd/date: MANIRAJA/230118; Crtd /date: MANIRAJA/230118; Custom_Duty: 15%; Customs_HS_Code: 85322990; Distributor_name: DIGIKEY; Distributor_part_number: GRM033R61E103KA12J-ND; Footprint Path: Y:\MIS_DATABASE\Library\ALTIUM_TOOL\PCB_FOOTPRINTS\Altium_Footprint_Lib.PcbLib; Height: 0.33MM; Library Path: Y:\MIS_DATABASE\Library\ALTIUM_TOOL\SCHEMATICS_PARTS\MS_DISCRETE_Library.schlib; Mfr_name: MURATA; Mfr_part_number: GRM033R61E103KA12J; Mistral Part No: 120018010007-R; Package: 0201; Part_type: CAPACITORS\CERAMIC; Project: TI_MAXIE_CPB; RoHS: RoHS; Temperature: -55°C+85°C; Tolerance: 10%; Voltage: 25V; Wattage: NA; Weight: 0.33mg; Datasheet: Y:\MIS_DATABASE\DATASHEETS\CAPACITORS\GRM033R61E103KA12.PDF
C20 C172-C174 = CAP: CAP CERAMIC 0.1uF 16V 10% X5R 0201; Alt_Mfr_name: YAGEO AMERICA; Alt_Mfr_part_number: CC0402KRX5R8BB104; Chkd/date: MANIRAJA/230118; Crtd /date: MANIRAJA/230118; Custom_Duty: 15%; Customs_HS_Code: 85322990; Distributor_name: DIGIKEY; Distributor_part_number: 490-14305-1-ND; Footprint Path: Y:\MIS_DATABASE\Library\ALTIUM_TOOL\PCB_FOOTPRINTS\Altium_Footprint_Lib.PcbLib; Height: 0.33MM; Library Path: Y:\MIS_DATABASE\Library\ALTIUM_TOOL\SCHEMATICS_PARTS\MS_DISCRETE_Library.schlib; Mfr_name: MURATA; Mfr_part_number: GRM033R61C104KE14D; Mistral Part No: 120009030072-R; Package: 0201; Part_type: CAPACITORS\CERAMIC; Project: TI_MAXIE_CPB; RoHS: RoHS; Temperature: -55°C+85°C; Tolerance: 10%; Voltage: 16V; Wattage: NA; Weight: 0.33mg; Datasheet: Y:\MIS_DATABASE\DATASHEETS\CAPACITORS\GRM033R61C104KE14.PDF
J12 = HEADER_2X1: CON HDR 1X2 2.54MM PITCH ST TH; Chkd/date: NAVEED/210714; Crtd /date: USMAN/031012; Custom_Duty: 24%; Customs_HS_Code: 85369090; Distributor_name: DIGIKEY; Distributor_part_number: WM8072-ND; Footprint Path: Y:\MIS_DATABASE\Library\ALTIUM_TOOL\PCB_FOOTPRINTS\Altium_Footprint_Lib.PcbLib; Height: 5.60MM; Library Path: Y:\MIS_DATABASE\Library\ALTIUM_TOOL\SCHEMATICS_PARTS\MS_CONNECTOR_Library.schlib; Mfr_name: MOLEX; Mfr_part_number: 90120-0122; Mistral Part No: 150012100005-R; Package: THRU-HOLE; Part_type: CONNECTOR\HEADERS; Project: NPOL_FEP; RoHS: RoHS; Temperature: -55°C+125°C; Tolerance: NA; Voltage: NA; Wattage: NA; Weight: 122mg; Datasheet: Y:\MIS_DATABASE\DATASHEETS\CONNECTORS\90120-XX.PDF
R19 = RESISTOR: RES 8.2K 1/20W 1% 0201; Chkd/date: SUHAS/230910; Crtd /date: MUDDU/060710; Custom_Duty: 15%; Customs_HS_Code: 85332119; Distributor_name: DIGIKEY; Distributor_part_number: 541-8.20KAABCT-ND; Footprint Path: Y:\MIS_DATABASE\Library\ALTIUM_TOOL\PCB_FOOTPRINTS\Altium_Footprint_Lib.PcbLib; Height: 0.28MM; Library Path: Y:\MIS_DATABASE\Library\ALTIUM_TOOL\SCHEMATICS_PARTS\MS_DISCRETE_Library.schlib; Mfr_name: VISHAY; Mfr_part_number: CRCW02018K20FKED; Mistral Part No: 110010070001-R; Package: 0201; Part_type: RESISTORS\FIXED; Project: PB_BUGBASE; RoHS: RoHS; Temperature: -55°C+155°C; Tolerance: 1%; Voltage: NA; Wattage: 1/20W; Weight: 0.17mg; Datasheet: Y:\MIS_DATABASE\DATASHEETS\RESISTORS\CRCW0201.PDF
R159 = RESISTOR: RES 1K 1/10W 1% 0402; Chkd/date: VASANTHA/281216; Crtd /date: MAZHAR/150506; Custom_Duty: 15%; Customs_HS_Code: 85332119; Distributor_name: DIGIKEY; Distributor_part_number: P1.00KLCT-ND; Footprint Path: Y:\MIS_DATABASE\Library\ALTIUM_TOOL\PCB_FOOTPRINTS\Altium_Footprint_Lib.PcbLib; Height: 0.40MM; Library Path: Y:\MIS_DATABASE\Library\ALTIUM_TOOL\SCHEMATICS_PARTS\MS_DISCRETE_Library.schlib; Mfr_name: PANASONIC-ECG; Mfr_part_number: ERJ-2RKF1001X; Mistral Part No: 110009030411-R; Package: 0402; Part_type: RESISTORS\FIXED; Project: VOCERA; RoHS: RoHS; Temperature: -55°C+155°C; Tolerance: 1%; Voltage: NA; Wattage: 1/10W; Weight: 0.8mg; Datasheet: Y:\MIS_DATABASE\DATASHEETS\RESISTORS\PAN-ERJSER_NOV17.PDF
TP2-TP7 = TESTPOINT: TESTPOINT CIR 20 SMD; Chkd/date: SHREESHAIL/171006; Crtd /date: MAZHAR/171006; Custom_Duty: NA; Customs_HS_Code: NA; Distributor_name: NA; Distributor_part_number: NA; Footprint Path: Y:\MIS_DATABASE\Library\ALTIUM_TOOL\PCB_FOOTPRINTS\Altium_Footprint_Lib.PcbLib; Height: NA; Library Path: Y:\MIS_DATABASE\Library\ALTIUM_TOOL\SCHEMATICS_PARTS\MS_DISCRETE_Library.schlib; MECHANICAL 3D STEP FILE: NA; Manufacturer: LOCAL; Mfr_name: LOCAL; Mistral Part No: NA; Package: SMD; Project: BT MODULE_CSRBC04; RoHS: NA; Temperature: NA; Tolerance: NA; Voltage: NA; Wattage: NA; Weight: NA; Datasheet: NA
U2 U92 = TCA6424ARGJR_QFN32: IC I2C I/O EXPANDER 24B UQFN32; Chkd/date: NAVEED/100715; Crtd /date: NAVEED/100914; Custom_Duty: 15%; Customs_HS_Code: 85423100; Distributor_name: DIGIKEY; Distributor_part_number: 296-27844-1-ND; Height: 0.60MM; Mfr_name: TEXAS INSTRUMENTS; Mistral Part No: 141014090009-R; Package: UQFN32; Part_type: ICS\DIGITAL\BUSTRANSCEIVER; Project: ZK_BIOMETRIC; RoHS: RoHS; Temperature: -40°C+85°C; Weight: NA; Datasheet: Y:\MIS_DATABASE\DATASHEETS\ICS\DIGITAL\BUSTRANSCEIVER\TCA6424AR.PDF
U51 = TXB0104RUTR_UQFN12: IC 4-BIT BIDIRECTIONAL VOLTAGE-LEVEL TRANSLATOR UQFN12; Chkd/date: MANIRAJA/281117; Crtd /date: ALVY/271117; Custom_Duty: 15%; Customs_HS_Code: 85423100; Distributor_name: DIGIKEY; Distributor_part_number: 296-25888-1-ND; Height: 0.55MM; Manufacturer: TEXAS INSTRUMENTS; Mfr_name: TEXAS INSTRUMENTS; Mistral Part No: 141017110007-R; Package: UQFN12; Part_type: ICS\INTERFACE\LEVEL TRANSLATOR; Project: RSAPR_TYPE-II_3U-SBC; RoHS: RoHS; Temperature: -40°C+85°C; Tolerance: NA; Voltage: NA; Wattage: NA; Weight: 4.70mg; Datasheet: Y:\MIS_DATABASE\DATASHEETS\ICS\INTERFACE\TXB0104.PDF
U52 = SN74CB3Q3257PWR_TSSOP16: IC 4BIT 1-OF-2 FET MULTIPLEXER/DEMULTIPLEXER TSSOP16; Chkd/date: SUHAS/251010; Crtd /date: USMAN/060109; Custom_Duty: 15%; Customs_HS_Code: 85423100; Distributor_name: DIGIKEY; Distributor_part_number: 296-19138-1-ND; Height: 1.20MM; Manufacturer: TEXAS INSTRUMENTS; Mfr_name: TEXAS INSTRUMENTS; Mistral Part No: 141009030117-R; Package: TSSOP16; Part_type: ICS\DIGITAL\COMBINATIONAL; Project: OMAP_EVM; RoHS: Sb/ Br FREE; Temperature: -40°C+85°C; Datasheet: Y:\MIS_DATABASE\DATASHEETS\ICS\DIGITAL\COMBINATIONAL\SN74CB3Q3257.PDF
C198 = CAP: CAP CERAMIC 4.7uF 10V 20% X5R 0402; Chkd/date: MANIRAJA/110718; Crtd /date: ALVY/110718; Custom_Duty: 15%; Customs_HS_Code: 85322990; Distributor_name: DIGIKEY; Distributor_part_number: 490-14306-1-ND; Footprint Path: Y:\MIS_DATABASE\Library\ALTIUM_TOOL\PCB_FOOTPRINTS\Altium_Footprint_Lib.PcbLib; Height: 0.65MM; Library Path: Y:\MIS_DATABASE\Library\ALTIUM_TOOL\SCHEMATICS_PARTS\MS_DISCRETE_Library.schlib; Mfr_name: MURATA; Mfr_part_number: GRM155R61A475MEAAD; Mistral Part No: 120012060002-R; Package: 0402; Part_type: CAPACITORS\CERAMIC; Project: TI_J7SVB_PCIE_ADD-ON-CARD; RoHS: RoHS; Temperature: -55°C+85°C; Tolerance: 20%; Voltage: 10V; Wattage: NA; Weight: 14mg; Datasheet: Y:\MIS_DATABASE\DATASHEETS\CAPACITORS\GRM155R61A475MEAAD.PDF
C438 = CAP: CAP CERAMIC 0.1uF 50V 10% X7R 0402; Alt_Mfr_name: YAGEO AMERICA; Alt_Mfr_part_number: CC0402KRX5R8BB104; Chkd/date: MANIRAJA/261020; Crtd /date: ALVY/211020; Custom_Duty: 15%; Customs_HS_Code: 85322990; Distributor_name: DIGIKEY; Distributor_part_number: 490-10700-1-ND; Footprint Path: Y:\MIS_DATABASE\Library\ALTIUM_TOOL\PCB_FOOTPRINTS\Altium_Footprint_Lib.PcbLib; Height: 0.55MM; Library Path: Y:\MIS_DATABASE\Library\ALTIUM_TOOL\SCHEMATICS_PARTS\MS_DISCRETE_Library.schlib; Mfr_name: MURATA; Mfr_part_number: GRM155R71H104KE14D; Mistral Part No: 120011100014-R; Package: 0402; Part_type: CAPACITORS\CERAMIC; Project: J7_CP; RoHS: RoHS; Temperature: -55°C+125°C; Tolerance: 10%; Voltage: 50V; Wattage: NA; Weight: 3.1mg; Datasheet: Y:\MIS_DATABASE\DATASHEETS\CAPACITORS\GRM155R71H104KE14.PDF
FB1-FB3 = INDUCTOR_FERRITE: IND FERRITE CHIP 300E 500mA 0603; Alternate_mfr_name_A: TDK CORPORATION; Alternate_mfr_part_number_A: MMZ1608R301ATA00; Chkd/date: VASANTHA/190614; Crtd /date: NAVEED/160614; Custom_Duty: 24%; Customs_HS_Code: 85437099; Distributor_name: DIGIKEY; Distributor_name_A: DIGIKEY; Distributor_part_number: 445-2171-1-ND; Distributor_part_number_A: 445-2171-1-ND; Height: 0.75MM; Mfr_name: TDK CORPORATION; Mfr_part_number: MMZ1608R301A; Mistral Part No: 130014060028-R; Package: 0603; Part_type: INDUCTOR; Project: AEGIS_POM; RoHS: RoHS; Temperature: -55°C+125°C; Tolerance: NA; Voltage: NA; Wattage: NA; Weight: NA; Datasheet: Y:\MIS_DATABASE\DATASHEETS\DISCRETES\INDUCTORS\MMZSER.PDF
FL2 = EMIFILTER_IND: IND FERRITE BEAD CHIP 120E 2A 0402; Chkd/date: NAVEED/241114; Crtd /date: USMAN/170613; Custom_Duty: 24%; Customs_HS_Code: 85369090; Distributor_name: DIGIKEY; Distributor_part_number: 490-9656-1-ND; Footprint Path: Y:\MIS_DATABASE\Library\ALTIUM_TOOL\PCB_FOOTPRINTS\Altium_Footprint_Lib.PcbLib; Height: 0.55MM; Library Path: Y:\MIS_DATABASE\Library\ALTIUM_TOOL\SCHEMATICS_PARTS\MS_FILTER_Library.schlib; Mfr_name: MURATA; Mfr_part_number: BLM15PX121SN1D; Mistral Part No: 130013060022-R; Package: 0402; Part_type: INDUCTOR; Project: GEN_3-8; RoHS: RoHS; Temperature: -55°C+125°C; Tolerance: 25%; Voltage: NA; Wattage: NA; Weight: 1mg; Datasheet: Y:\MIS_DATABASE\DATASHEETS\DISCRETES\INDUCTORS\BLM15-SN1-SER.PDF
J5 = CON_HDMI_19X1: CON HDMI-A TYPE 1X19 0.50MM PITCH FEMALE RT SMD; Chkd/date: VASANTHA/060117; Crtd /date: MUDDU/060510; Custom_Duty: 24%; Customs_HS_Code: 85369090; Distributor_name: DIGIKEY; Distributor_part_number: 609-1010-1-ND; Footprint Path: Y:\MIS_DATABASE\Library\ALTIUM_TOOL\PCB_FOOTPRINTS\Altium_Footprint_Lib.PcbLib; Height: 6.30MM; Library Path: Y:\MIS_DATABASE\Library\ALTIUM_TOOL\SCHEMATICS_PARTS\MS_CONNECTOR_Library.schlib; Mfr_name: FCI; Mfr_part_number: 10029449-001RLF; Mistral Part No: 150010050001-R; Package: SMD; Part_type: CONNECTOR\HDMI; Project: SHIVA; RoHS: RoHS; Temperature: -20°C+85°C; Tolerance: NA; Voltage: NA; Wattage: NA; Weight: 2700mg; Datasheet: Y:\MIS_DATABASE\DATASHEETS\CONNECTORS\10029449-001RLF.PDF
R57 = RESISTOR: RES 4.7K 1/20W 5% 0201; Chkd/date: MANIRAJA/200921; Crtd /date: ALVY/200921; Custom_Duty: 15%; Customs_HS_Code: 85332119; Distributor_name: DIGIKEY; Distributor_part_number: 311-4.7KNCT-ND; Footprint Path: Y:\MIS_DATABASE\Library\ALTIUM_TOOL\PCB_FOOTPRINTS\Altium_Footprint_Lib.PcbLib; Height: 0.26MM; Library Path: Y:\MIS_DATABASE\Library\ALTIUM_TOOL\SCHEMATICS_PARTS\MS_DISCRETE_Library.schlib; Mfr_name: YAGEO AMERICA; Mfr_part_number: RC0201JR-074K7L; Mistral Part No: 110021090007-R; Package: 0201; Part_type: RESISTORS\FIXED; Project: TI_AM62x SKEVM_BRD; RoHS: RoHS; Temperature: -55°C+125°C; Tolerance: 5%; Voltage: NA; Wattage: 1/20W; Weight: 0.17mg; Datasheet: Y:\MIS_DATABASE\DATASHEETS\RESISTORS\RCXXXXL-SER_MAR18.PDF
R298 R310 = RESISTOR: RES 2.2K 1/16W 5% 0402; Chkd/date: VASANTHA/061216; Crtd /date: BAVISH/021210; Custom_Duty: 15%; Customs_HS_Code: 85332119; Distributor_name: DIGIKEY; Distributor_part_number: 311-2.2KJRCT-ND; Footprint Path: Y:\MIS_DATABASE\Library\ALTIUM_TOOL\PCB_FOOTPRINTS\Altium_Footprint_Lib.PcbLib; Height: 0.40MM; Library Path: Y:\MIS_DATABASE\Library\ALTIUM_TOOL\SCHEMATICS_PARTS\MS_DISCRETE_Library.schlib; Mfr_name: YAGEO AMERICA; Mfr_part_number: RC0402JR-072K2L; Mistral Part No: 110010120018-R; Package: 0402; Part_type: RESISTORS\FIXED; Project: TE4; RoHS: RoHS; Temperature: -55°C+155°C; Tolerance: 5%; Voltage: NA; Wattage: 1/16W; Weight: 0.65mg; Datasheet: Y:\MIS_DATABASE\DATASHEETS\RESISTORS\RCXXXXL-SER_MAR18.PDF
R308 = RESISTOR: RES 4.3K 1/16W 1% 0402; Chkd/date: VASANTHA/140616; Crtd /date: VASANTHA/140616; Custom_Duty: 15%; Customs_HS_Code: 85332119; Distributor_name: DIGIKEY; Distributor_part_number: 311-4.30KLRCT-ND; Footprint Path: Y:\MIS_DATABASE\Library\ALTIUM_TOOL\PCB_FOOTPRINTS\Altium_Footprint_Lib.PcbLib; Height: 0.40MM; Library Path: Y:\MIS_DATABASE\Library\ALTIUM_TOOL\SCHEMATICS_PARTS\MS_DISCRETE_Library.schlib; Mfr_name: YAGEO AMERICA; Mfr_part_number: RC0402FR-074K3L; Mistral Part No: 110016060004-R; Package: 0402; Part_type: RESISTORS\FIXED; Project: TMDXCSKCC; RoHS: RoHS; Temperature: -55°C+155°C; Tolerance: 1%; Voltage: NA; Wattage: 1/16W; Weight: 0.65mg; Datasheet: Y:\MIS_DATABASE\DATASHEETS\RESISTORS\RCXXXXL-SER_MAR18.PDF
R318 = RESISTOR: RES 0E 1/20W 5% 0201; Chkd/date: NAVEED/301214; Crtd /date: MUDDU/120710; Custom_Duty: 15%; Customs_HS_Code: 85332119; Distributor_name: DIGIKEY; Distributor_part_number: 311-0.0NCT-ND; Footprint Path: Y:\MIS_DATABASE\Library\ALTIUM_TOOL\PCB_FOOTPRINTS\Altium_Footprint_Lib.PcbLib; Height: 0.26MM; Library Path: Y:\MIS_DATABASE\Library\ALTIUM_TOOL\SCHEMATICS_PARTS\MS_DISCRETE_Library.schlib; Mfr_name: YAGEO AMERICA; Mfr_part_number: RC0201JR-070RL; Mistral Part No: 110010070067-R; Package: 0201; Part_type: RESISTORS\FIXED; Project: PB_BUGBASE; RoHS: RoHS; SIGNAL_MODEL: RESISTOR_RES0201_0-5_0E_0E; Temperature: -55°C+125°C; Tolerance: 5%; Voltage: NA; Wattage: 1/20W; Weight: 0.17mg; Datasheet: Y:\MIS_DATABASE\DATASHEETS\RESISTORS\RCXXXXL-SER_MAR18.PDF
U13 = SII9022ACNU_QFN72: IC HDMI TRANSMITTER QFN72; Chkd/date: MANIRAJA/270818; Crtd /date: MUDDU/310510; Custom_Duty: 15%; Customs_HS_Code: 85423100; Distributor_name: NA; Distributor_part_number: NA; Footprint Path: Y:\MIS_DATABASE\Library\ALTIUM_TOOL\PCB_FOOTPRINTS\Altium_Footprint_Lib.PcbLib; Height: 0.90MM; Library Path: Y:\MIS_DATABASE\Library\ALTIUM_TOOL\SCHEMATICS_PARTS\MS_COMBINATIONAL_Library.schlib; Library Ref: SiI9022ACNU_QFN72; Mfr_name: SILICON IMAGE; Mistral Part No: 141010060001; Package: QFN72; Part_type: ICS\DIGITAL\PERIPHERAL; Project: CENTAURUS; RoHS: NA; Temperature: -20°C+85°C; Tolerance: NA; Voltage: NA; Wattage: NA; Weight: NA; Datasheet: Y:\MIS_DATABASE\DATASHEETS\ICS\DIGITAL\PERIPHERAL\SiI9022.PDF
U58 = TPD12S016PW_TSSOP24: IC HDMI COMPANION CHIP WITH I2C LEVEL SHIFTING,12-CH ESD TSSOP24; Chkd/date: MANIRAJA/110917; Crtd /date: BAVISH/180811; Custom_Duty: 15%; Customs_HS_Code: 85423100; Distributor_name: DIGIKEY; Distributor_part_number: 296-29690-1-ND; Height: 1.20MM; Mfr_name: TEXAS INSTRUMENTS; Mistral Part No: 141011080021-R; Package: TSSOP24; Part_type: ICS\INTERFACE; Project: DM385EVM_BASE-BOARD; RoHS: RoHS; Temperature: -40°C+85°C; Tolerance: NA; Voltage: NA; Wattage: NA; Weight: 212mg; Datasheet: Y:\MIS_DATABASE\DATASHEETS\ICS\INTERFACE\TPD12S016.PDF

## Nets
DGND: C1.1 C20.1 C115.2 C119.2 C124.2 C125.2 C172.1 C173.1 C174.1 C192.2 C196.2 C197.2 C198.2 C200.2 C201.2 C202.2 C203.2 C204.2 C205.2 C206.2 C207.2 C208.2 C210.2 C211.2 C212.2 C213.1 C219.2 C402.2 C406.2 C407.2 C409.2 C411.2 C418.2 C419.2 C424.2 C425.2 C434.2 C435.1 C438.2 FL2.1 J5.2 J5.5 J5.8 J5.11 J5.17 J14.4 R18.1 R47.2 R48.1 R54.2 R152.2 R153.2 R159.1 R253.1 R308.2 R432.1 R442.1 R450.1 R452.1 R463.1 TP64.1(TP) U2.25(GND) U2.33(EP) U9.2(CASEGND) U13.43(CGND) U13.55(RSVDL) U13.57(IOGND) U13.63(AGND) U13.70(VDDQ) U13.73(PAD) U51.6(GND) U52.8(GND) U58.6(GND1) U58.14(GND2) U58.19(GND3) U86.2(CASEGND) U88.15(AVSS_ADC) U88.20(DRVSS.1) U88.21(DRVSS.2) U88.26(AVSS_DAC) U88.42(DVSS) U88.43(SELECT) U88.49(TPAD) U92.25(GND) U92.33(EP) U93.3(GND) U94.3(GND) ; also on sheet 9 10 11 12 13 14 15 16 17 18 19 20 21 22 23 24 25 26 27 28 29 30 31 32 33 34 35 36 37 41 42 43
VCC1V8_SYS: C173.2 R411.2 U51.1(VCCA) ; also on sheet 12 13 17 18 20 24 33 36 41
VCC_1V8_AUD: C409.1 C411.1 R411.1 U88.36(DVDD.1)
VCC_3V3_AUD: C124.1 C125.1 C402.1 C406.1 C407.1 C418.1 C419.1 C424.1 C425.1 C434.1 R399.1 R402.1 R403.1 R427.2 R435.1 U86.4(VCC) U88.16(DRVDD.1) U88.17(DRVDD.2) U88.24(DRVDD.3) U88.25(AVDD_DAC) U88.44(IOVDD) U93.5(VCC)
VCC_3V3_SYS: C1.2 C20.2 C172.2 C174.2 C213.2 C219.1 C435.2 C438.1 FB3.2 R1.2 R3.2 R44.2 R168.2 R172.2 R252.2 R317.2 R435.2 R438.2 R451.2 U2.27(VCCP) U2.31(VCC) U9.4(VCC) U51.11(VCCB) U52.16(VCC) U58.24(VCCA) U92.27(VCCP) U92.31(VCC) U94.5(VCC) ; also on sheet 9 10 12 13 17 18 19 21 22 23 25 26 28 29 30 32 33 34 35 36 37 41 42
VCC_5V0: C204.1 U58.11(VCC5V) ; also on sheet 9 10 23 32 34 37
VCC_5V0_HDMICONN: C202.1 J5.18 U58.13(5V_OUT)
VDD_1V2: C192.1 C198.1 FB1.2 FB2.2 ; also on sheet 10
ADDR_IO_EXP: R452.2 U92.26(ADDR)
ADDR_IO_EXP1: R1.1 U2.26(ADDR)
AUD_RSTn: R450.2 U88.33(~{RESET}) U93.4(Y)
AUDIO_EXT_REFCLK1: R42.2 ; also on sheet 32
AUDIO_MSTRCLK: R407.1 U88.37(MCLK)
AUTO_100M_1000M_CONFIG: U2.22(P25) ; also on sheet 23
BT_EN_SOC: U92.3(P02) ; also on sheet 17
BT_UART_WAKE_SOC_3V3: U92.12(P13) ; also on sheet 17
CSI_EN: U2.21(P24) ; also on sheet 37
CSI_GPIO0: U92.14(P15) ; also on sheet 36 37
CSI_GPIO1: U92.15(P16) ; also on sheet 36 37
CSI_RSTz: U2.10(P11) ; also on sheet 36
CSI_SEL2: U2.20(P23) ; also on sheet 37
CSI_VLDO_SEL: U2.23(P26) ; also on sheet 37
EXP_HAT_DETECT: R172.1 U92.8(P07) ; also on sheet 32
EXP_PS_3V3_EN: U92.6(P05) ; also on sheet 32
EXP_PS_5V0_EN: U92.7(P06) ; also on sheet 32
GPIO1_23_INTn: R448.1 ; also on sheet 41 42
GPIO_AUD_RSTn: R427.1 R432.2 U92.9(P10) U93.1(A)
GPIO_CPSW1_RST: U92.2(P01) ; also on sheet 22
GPIO_CPSW2_RST: U92.1(P00) ; also on sheet 23
GPIO_eMMC_RSTn: U92.10(P11) ; also on sheet 18
GPIO_HDMI_RSTn: R438.1 R442.2 U92.13(P14) U94.1(A)
HDMI_AUDD1: TP10.1(TP) U13.40(SD1)
HDMI_AUDD2: TP12.1(TP) U13.39(SD2)
HDMI_AUDD3: TP14.1(TP) U13.37(SD3)
HDMI_CEC: U13.71(CEC_A) U58.1(CEC_A)
HDMI_CEC_D: TP11.1(TP) U13.50(CEC_D)
HDMI_CLK+: J5.10 U13.59(TXC+) U58.16(CLK+)
HDMI_CLK-: J5.12 U13.58(TXC-) U58.15(CLK-)
HDMI_CONN_I2CSCL: J5.15 U58.8(SCL_B)
HDMI_CONN_I2CSDA: J5.16 U58.9(SDA_B)
HDMI_CONNCEC: J5.13 U58.7(CEC_B)
HDMI_EARTH: FL2.2 J5.20 J5.21 J5.22 J5.23
HDMI_EXTSWING: R308.1 U13.56(EXT_SWING)
HDMI_HPD: R47.1 U13.54(HPD) U58.4(HPD_A)
HDMI_I2C_SCL: R298.2 U13.49(DSCL) U58.2(SCL_A)
HDMI_I2C_SDA: R310.2 U13.48(DSDA) U58.3(SDA_A)
HDMI_INTn: R45.2 U13.52(INT) U92.17(P20)
HDMI_MSTRCLK: R43.2 U13.38(MCLK)
HDMI_PCLK: R318.2 U13.22(IDCK)
HDMI_RSTn: R463.2 U13.51(RESET#) U94.4(Y)
HDMI_TX0+: J5.7 U13.62(TX0+) U58.18(D0+)
HDMI_TX0-: J5.9 U13.61(TX0-) U58.17(D0-)
HDMI_TX1+: J5.4 U13.65(TX1+) U58.21(D1+)
HDMI_TX1-: J5.6 U13.64(TX1-) U58.20(D1-)
HDMI_TX2+: J5.1 U13.68(TX2+) U58.23(D2+)
HDMI_TX2-: J5.3 U13.67(TX2-) U58.22(D2-)
HDMICONN_HPD: J5.19 U58.10(HPD_B)
HPLOUT: C430.2 J14.2
HPLOUT_C: C430.1 U88.18(HPLOUT)
HPROUT: C431.2 J14.3
HPROUT_C: C431.1 U88.23(HPROUT)
IO_EXP1_INTn: R3.1 U2.32(~{INT})
IO_EXP_INTn: R448.2 R451.1 U92.32(~{INT})
IO_EXP_TEST_LED: U92.24(P27) ; also on sheet 35
LINE1L+: C414.1 TP59.1(TP)
LINE1L+_C: C414.2 U88.3(LINE1L+)
LINE1R+: C416.1 TP60.1(TP)
LINE1R+_C: C416.2 U88.5(LINE1R+)
MCASP1_ACLKX_AUD: TP56.1(TP) U52.3(1B2) U88.38(BCLK)
MCASP1_ACLKX_BT: U51.5(A4) ; also on sheet 17
MCASP1_ACLKX_BUF: U51.7(B4) U52.4(1A) ; also on sheet 31
MCASP1_ACLKX_HDMI: U13.45(SCK) U52.2(1B1)
MCASP1_AFSX_AUD: TP52.1(TP) U52.6(2B2) U88.39(WCLK)
MCASP1_AFSX_BT: U51.4(A3) ; also on sheet 17
MCASP1_AFSX_BUF: U51.8(B3) U52.7(2A) ; also on sheet 31
MCASP1_AFSX_HDMI: U13.44(WS) U52.5(2B1)
MCASP1_AXR0_AUD: TP57.1(TP) U52.10(3B2) U88.40(DIN)
MCASP1_AXR0_BT: U51.3(A2) ; also on sheet 17
MCASP1_AXR0_BUF: U51.9(B2) U52.9(3A) ; also on sheet 31
MCASP1_AXR0_HDMI: U13.41(SD0) U52.11(3B1)
MCASP1_AXR2_AUD: R404.1 TP51.1(TP) U52.13(4B2)
MCASP1_AXR2_BT: U51.2(A1) ; also on sheet 17
MCASP1_AXR2_BUF: U51.10(B1) U52.12(4A) ; also on sheet 31
MCASP1_BUF_BT_EN: R19.1 U92.20(P23)
MCASP1_BUF_BT_EN_1V8: R18.2 R19.2 U51.12(OE)
MCASP1_FET_EN: R252.1 R253.2 U52.15(~{OE}) U92.19(P22)
MCASP1_FET_SEL: J12.1 R168.1 U52.1(S) U92.21(P24)
MFP0: R152.1 R403.2 U88.45(MFP0)
MFP1: R153.1 R402.2 U88.46(MFP1)
MFP2: TP55.1(TP) U88.47(MFP2)
MFP3: TP54.1(TP) U88.48(MFP3)
MIC_IN: C426.1 J14.1 R437.1 U88.12(MICDET)
MMC1_SD_EN: U92.4(P03) ; also on sheet 19
PD_I2C_IRQ: U92.23(P26) ; also on sheet 9
RESETSTATz: U2.28(~{RESET}) U92.28(~{RESET}) U93.2(B) U94.2(B) ; also on sheet 18 19 20 22 23 26 37 41
RGMII2_BRD_CONN_DET: U2.19(P22) ; also on sheet 23
SOC_I2C1_SCL: R406.1 U2.29(SCL) U13.1(CSCL) U92.29(SCL) ; also on sheet 13 21 25 41
SOC_I2C1_SDA: R405.1 U2.30(SDA) U13.2(CSDA) U92.30(SDA) ; also on sheet 13 21 25 41
SoC_VOUT0_DATA0: U13.32(D0) U18.U22(VOUT0_DATA0)
SoC_VOUT0_DATA1: U13.31(D1) U18.U21(VOUT0_DATA1)
SoC_VOUT0_DATA2: U13.30(D2) U18.U20(VOUT0_DATA2)
SoC_VOUT0_DATA3: U13.29(D3) U18.U19(VOUT0_DATA3)
SoC_VOUT0_DATA4: U13.28(D4) U18.T19(VOUT0_DATA4)
SoC_VOUT0_DATA5: U13.27(D5) U18.U18(VOUT0_DATA5)
SoC_VOUT0_DATA6: U13.25(D6) U18.V22(VOUT0_DATA6)
SoC_VOUT0_DATA7: U13.24(D7) U18.V21(VOUT0_DATA7)
SoC_VOUT0_DATA8: U13.23(D8) U18.V19(VOUT0_DATA8)
SoC_VOUT0_DATA9: U13.20(D9) U18.V18(VOUT0_DATA9)
SoC_VOUT0_DATA10: U13.19(D10) U18.W22(VOUT0_DATA10)
SoC_VOUT0_DATA11: U13.18(D11) U18.W21(VOUT0_DATA11)
SoC_VOUT0_DATA12: U13.17(D12) U18.W20(VOUT0_DATA12)
SoC_VOUT0_DATA13: U13.16(D13) U18.W19(VOUT0_DATA13)
SoC_VOUT0_DATA14: U13.15(D14) U18.Y21(VOUT0_DATA14)
SoC_VOUT0_DATA15: U13.14(D15) U18.Y22(VOUT0_DATA15)
SoC_VOUT0_DATA16: U13.13(D16) ; also on sheet 31
SoC_VOUT0_DATA17: U13.11(D17) ; also on sheet 31
SoC_VOUT0_DATA18: U13.10(D18) ; also on sheet 31
SoC_VOUT0_DATA19: U13.9(D19) ; also on sheet 31
SoC_VOUT0_DATA20: U13.8(D20) ; also on sheet 31
SoC_VOUT0_DATA21: U13.7(D21) ; also on sheet 31
SoC_VOUT0_DATA22: U13.6(D22) ; also on sheet 31
SoC_VOUT0_DATA23: U13.4(D23) ; also on sheet 31
SoC_VOUT0_DE: U13.33(DE) U18.U17(VOUT0_DE)
SoC_VOUT0_HSYNC: U13.34(HSYNC) U18.T18(VOUT0_HSYNC)
SoC_VOUT0_PCLK: R318.1 U18.AA22(VOUT0_PCLK)
SoC_VOUT0_VSYNC: U13.35(VSYNC) U18.V17(VOUT0_VSYNC)
SoC_WLAN_SDIO_RST: U2.24(P27) ; also on sheet 17
SPI0_FET_OE: U2.18(P21) ; also on sheet 41
SPI0_FET_SEL: U2.17(P20) ; also on sheet 41
TEST_GPIO2: U92.18(P21) ; also on sheet 25 27
UART1_FET_BUF_EN: U92.11(P12) ; also on sheet 36
UART1_FET_SEL: U92.22(P25) ; also on sheet 36
VHDMI_AVCC_1V2: C203.1 C205.1 C207.1 FB2.1 U13.60(AVCC12_1) U13.66(AVCC12_2)
VHDMI_CVCC_1V2: C196.1 C200.1 C201.1 C206.1 C208.1 C212.1 FB1.1 U13.5(CVCC12_1) U13.12(CVCC12_2) U13.26(CVCC12_3) U13.42(CVCC12_4) U13.47(CVCC12_5) U13.53(CVCC12_6)
VHDMI_IOVCC_3V3: C197.1 C210.1 C211.1 FB3.1 R45.1 R57.1 R298.1 R310.1 U13.3(IOVCC1) U13.21(IOVCC2) U13.46(IOVCC3)
VPP_EN: U92.5(P04) ; also on sheet 12
WL_LT_EN: U2.9(P10) ; also on sheet 17
WLAN_ALERTn: U92.16(P17) ; also on sheet 17
N16927060: R57.2 U13.72(CI2CA)
N16927228: R54.1 U13.69(IO_SEL)
N16927289: R48.2 U13.36(SPDIF)
N16929458: TP62.1(TP) U88.7(LINE2L+)
N16929460: TP61.1(TP) U88.8(LINE2L-)
N16929474: R404.2 U88.41(DOUT)
N16929699: C115.1 U88.4(LINE1L-)
N16929703: C119.1 U88.6(LINE1R-)
N16929744: TP67.1(TP) U88.19(HPLCOM)
N16929747: TP66.1(TP) U88.22(HPRCOM)
N16929749: TP102.1(TP) U88.35(GPIO1)
N16929751: TP103.1(TP) U88.34(GPIO2)
N17275147: R407.2 U86.3(OUTPUT)
N17285208: R317.1 U58.5(LS_OE) U58.12(CT_HPD)
N17498937: R405.2 U88.2(SDA)
N17498940: R406.2 U88.1(SCL)
N18736007: C426.2 U88.14(MIC3R)
N18736028: R437.2 U88.13(MICBIAS)
N19082749: R42.1 R43.1 U9.3(OUTPUT)
N20936712: J12.2 R159.2
N21197992: TP7.1(TP) U2.16(P17)
N21197993: TP4.1(TP) U2.15(P16)
N21197994: TP3.1(TP) U2.13(P14)
N21197995: TP6.1(TP) U2.14(P15)
N21197996: TP5.1(TP) U2.12(P13)
N21198784: TP2.1(TP) U2.11(P12)
N23413104: R44.1 U9.1(INH)
N23415089: R399.2 U86.1(INH)

Not connected (* = marked no-connect by the designer): J5 14*; U2 1(P00)* 2(P01)* 3(P02)* 4(P03)* 5(P04)* 6(P05)* 7(P06)* 8(P07)*; U52 14(4B1)*; U88 9(LINE2R+)* 10(LINE2R-)* 11(MIC3L)* 27(MONO_LO+)* 28(MONO_LO-)* 29(LEFT_LO+)* 30(LEFT_LO-)* 31(RIGHT_LO+)* 32(RIGHT_LO-)*

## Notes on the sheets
sheet 38
- AUDIO CODEC
- Silk: LINE IN
- MIC + HEADPHONE
- I2C ADDRESS: 0x1B
- AUDIO CODEC RESET
- CODEC I2C ADDRESS SELECTION
- MFP0
- MFP1
- Device Address
- 0
- 0
- 0x18
- 0
- 1
- 0x19
- 1
- 0
- 0x1A
- 1
- 1
- 0x1B
sheet 39
- IO EXPANDER
- [GPIO/PWM_A]
- [GPIO/PWM_B]
- I2C ADDRESS: 0x23
- I2C ADDRESS: 0x22
- McASP1 FET SWITCH & BUFFER
- INPUT/OUTPUT
- OEn
- SEL
- An
- L
- H(DEFAULT)
- An=nB2
- MCASP1 - CODEC
- L
- L
- An=nB1
- MCASP1 - HDMI
sheet 40
- HDMI INTERFACE
- HDMI ESD DEVICE
- 100E
- 100E
- 100E
- 100E
- NOTE:
  TPD12S016PWR has integrated pullup or pulldown resistors on the
  I2C and HPD lines hence no external pullup or pulldown required.
- HDMI CONNECTOR
- $:TRI-PAD WITH R1069
- I2C ADDRESS: 0x3B, 0x3F, 0x62
- Silk: HDMI
- HDMI RESET
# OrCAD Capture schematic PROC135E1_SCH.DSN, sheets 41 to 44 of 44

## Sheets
41 41. OSCILLATOR: size C; title: OSCILLATOR
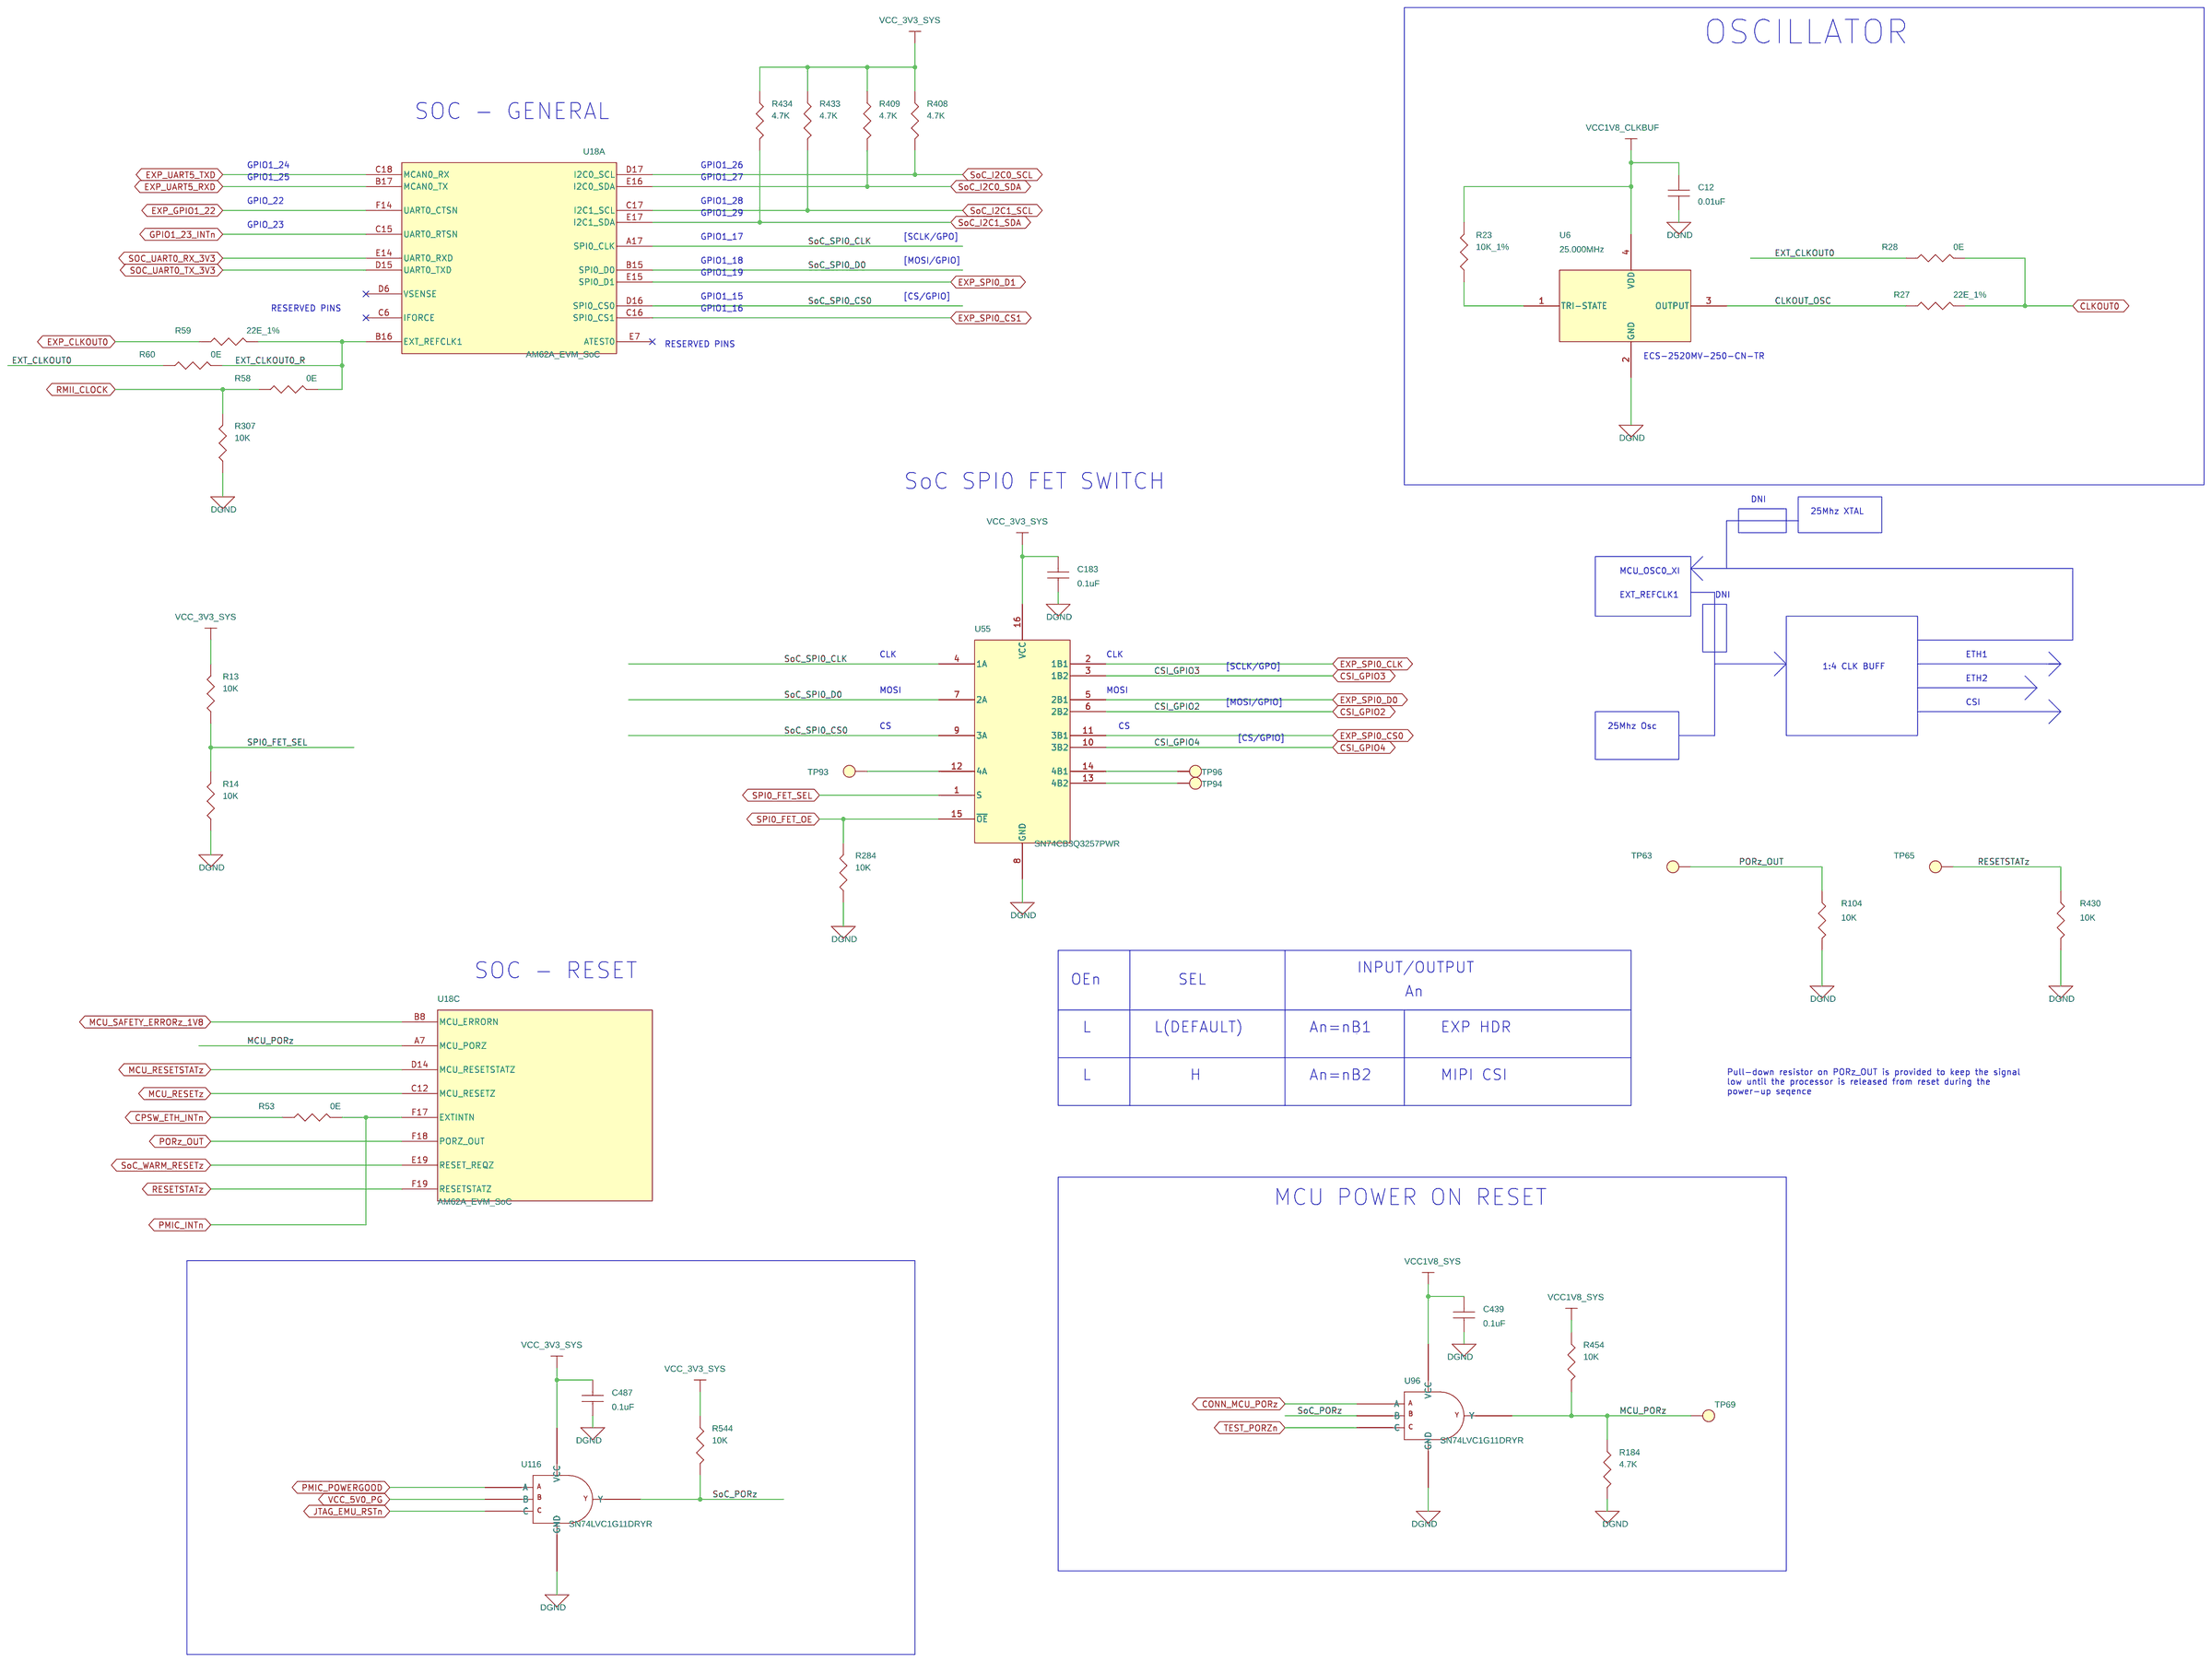
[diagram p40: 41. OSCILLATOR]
42 42. RESET: size C; title: RESET
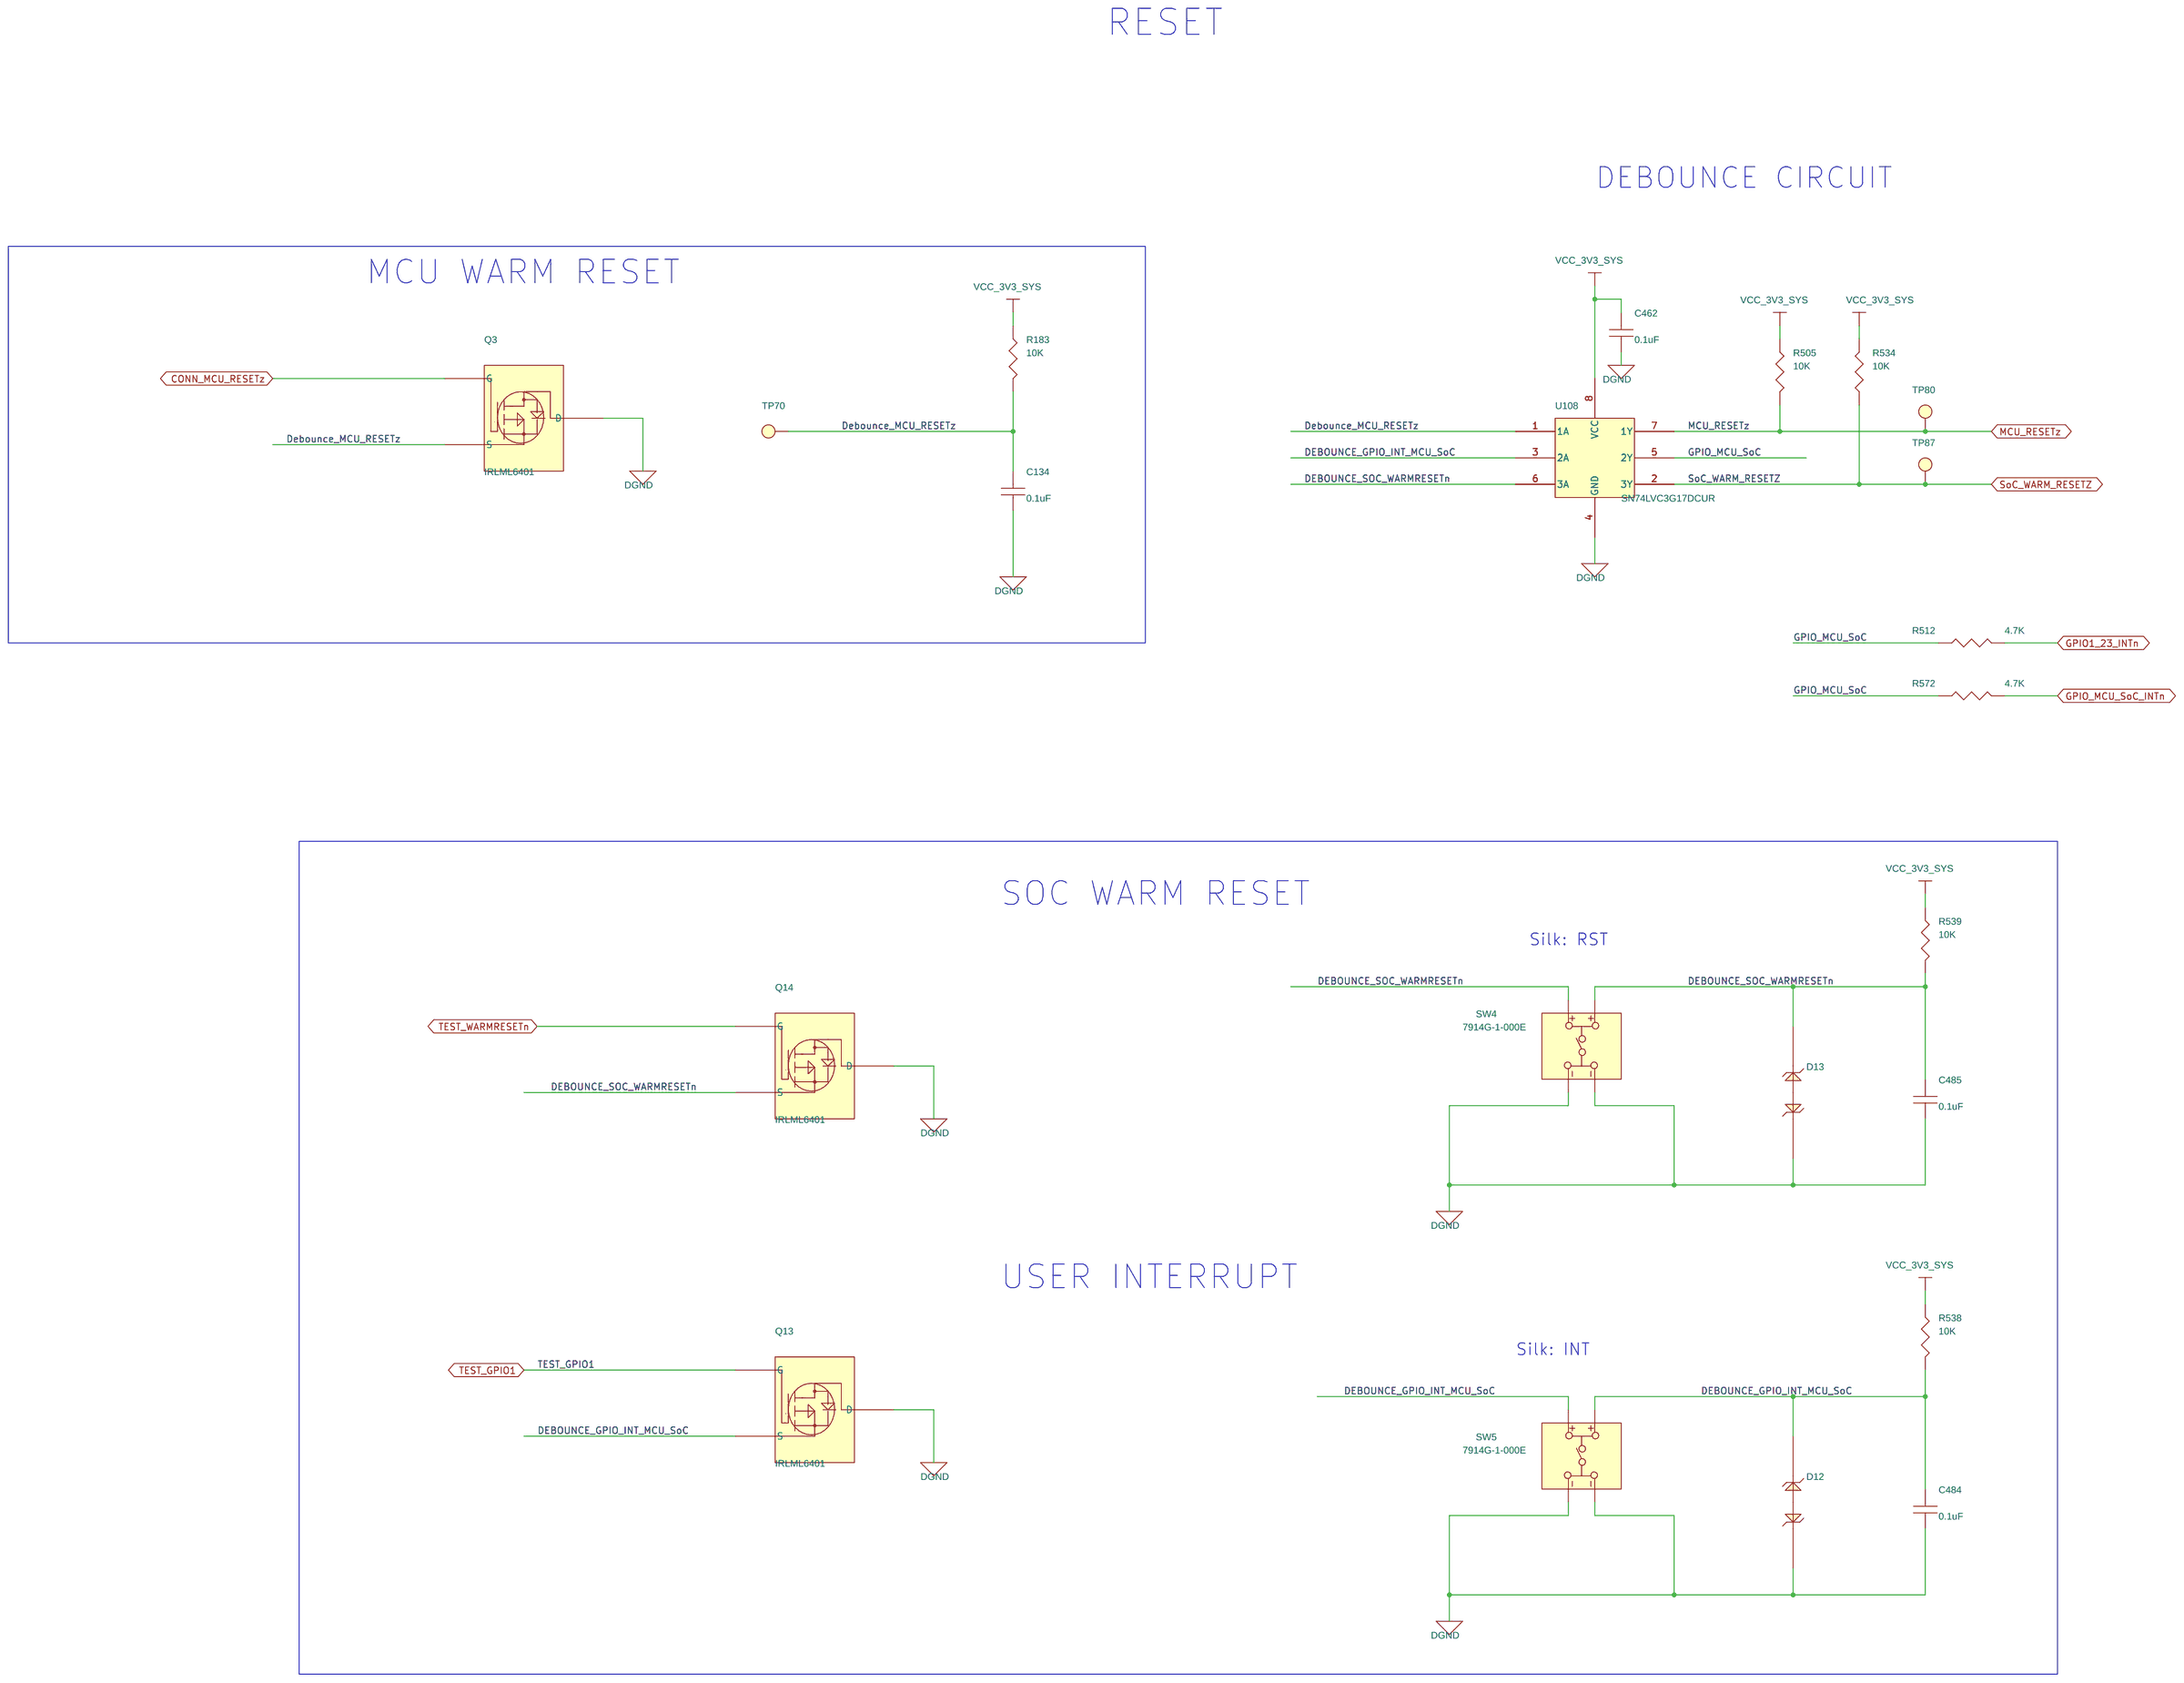
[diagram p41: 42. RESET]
43 43. CAN_FD_WKUP_SW: size C; title: CAN FD WKUP SW
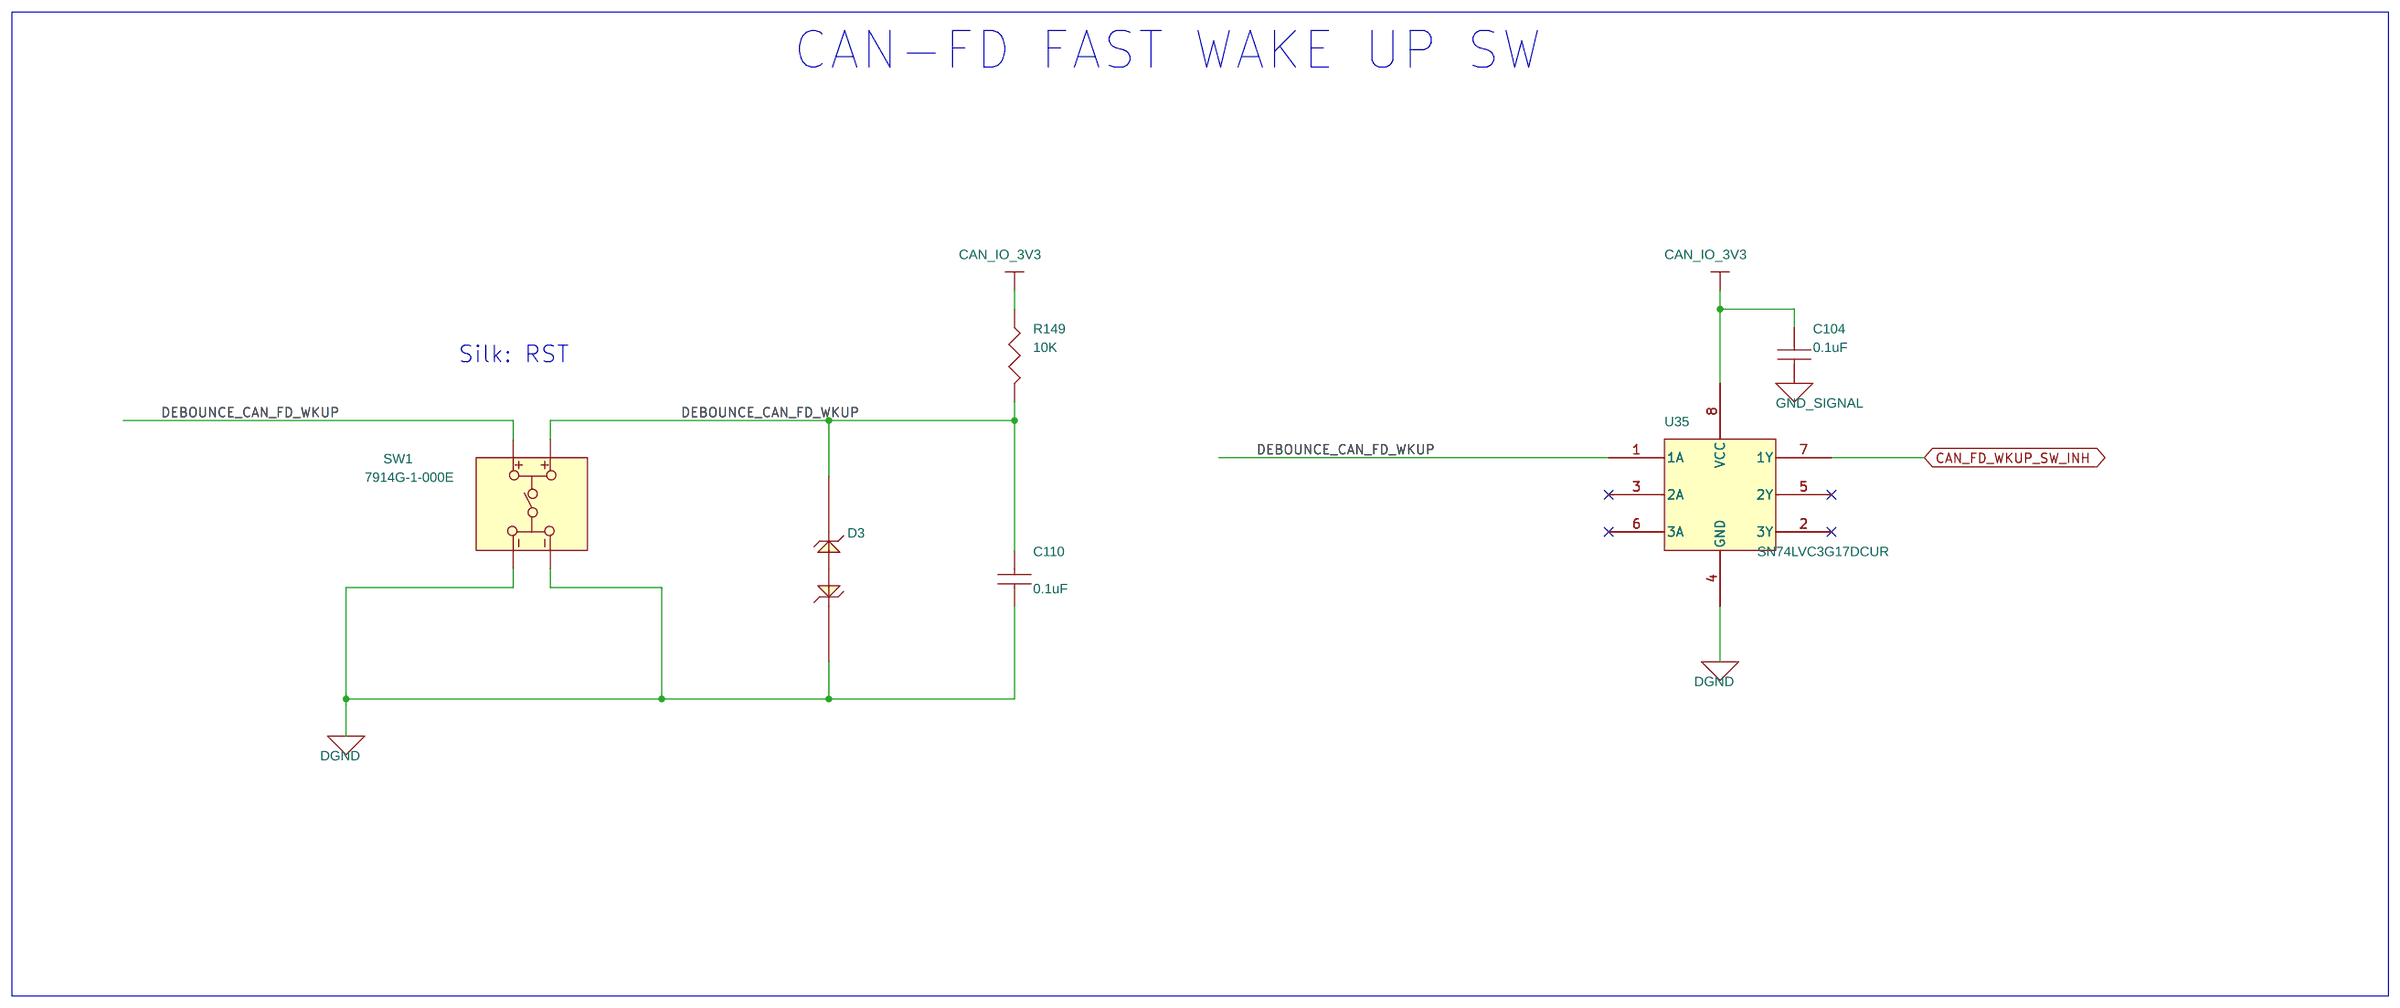
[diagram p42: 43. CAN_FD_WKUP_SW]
44 44. ACCESSORIES: title: HARDWARE SCHEMATICS

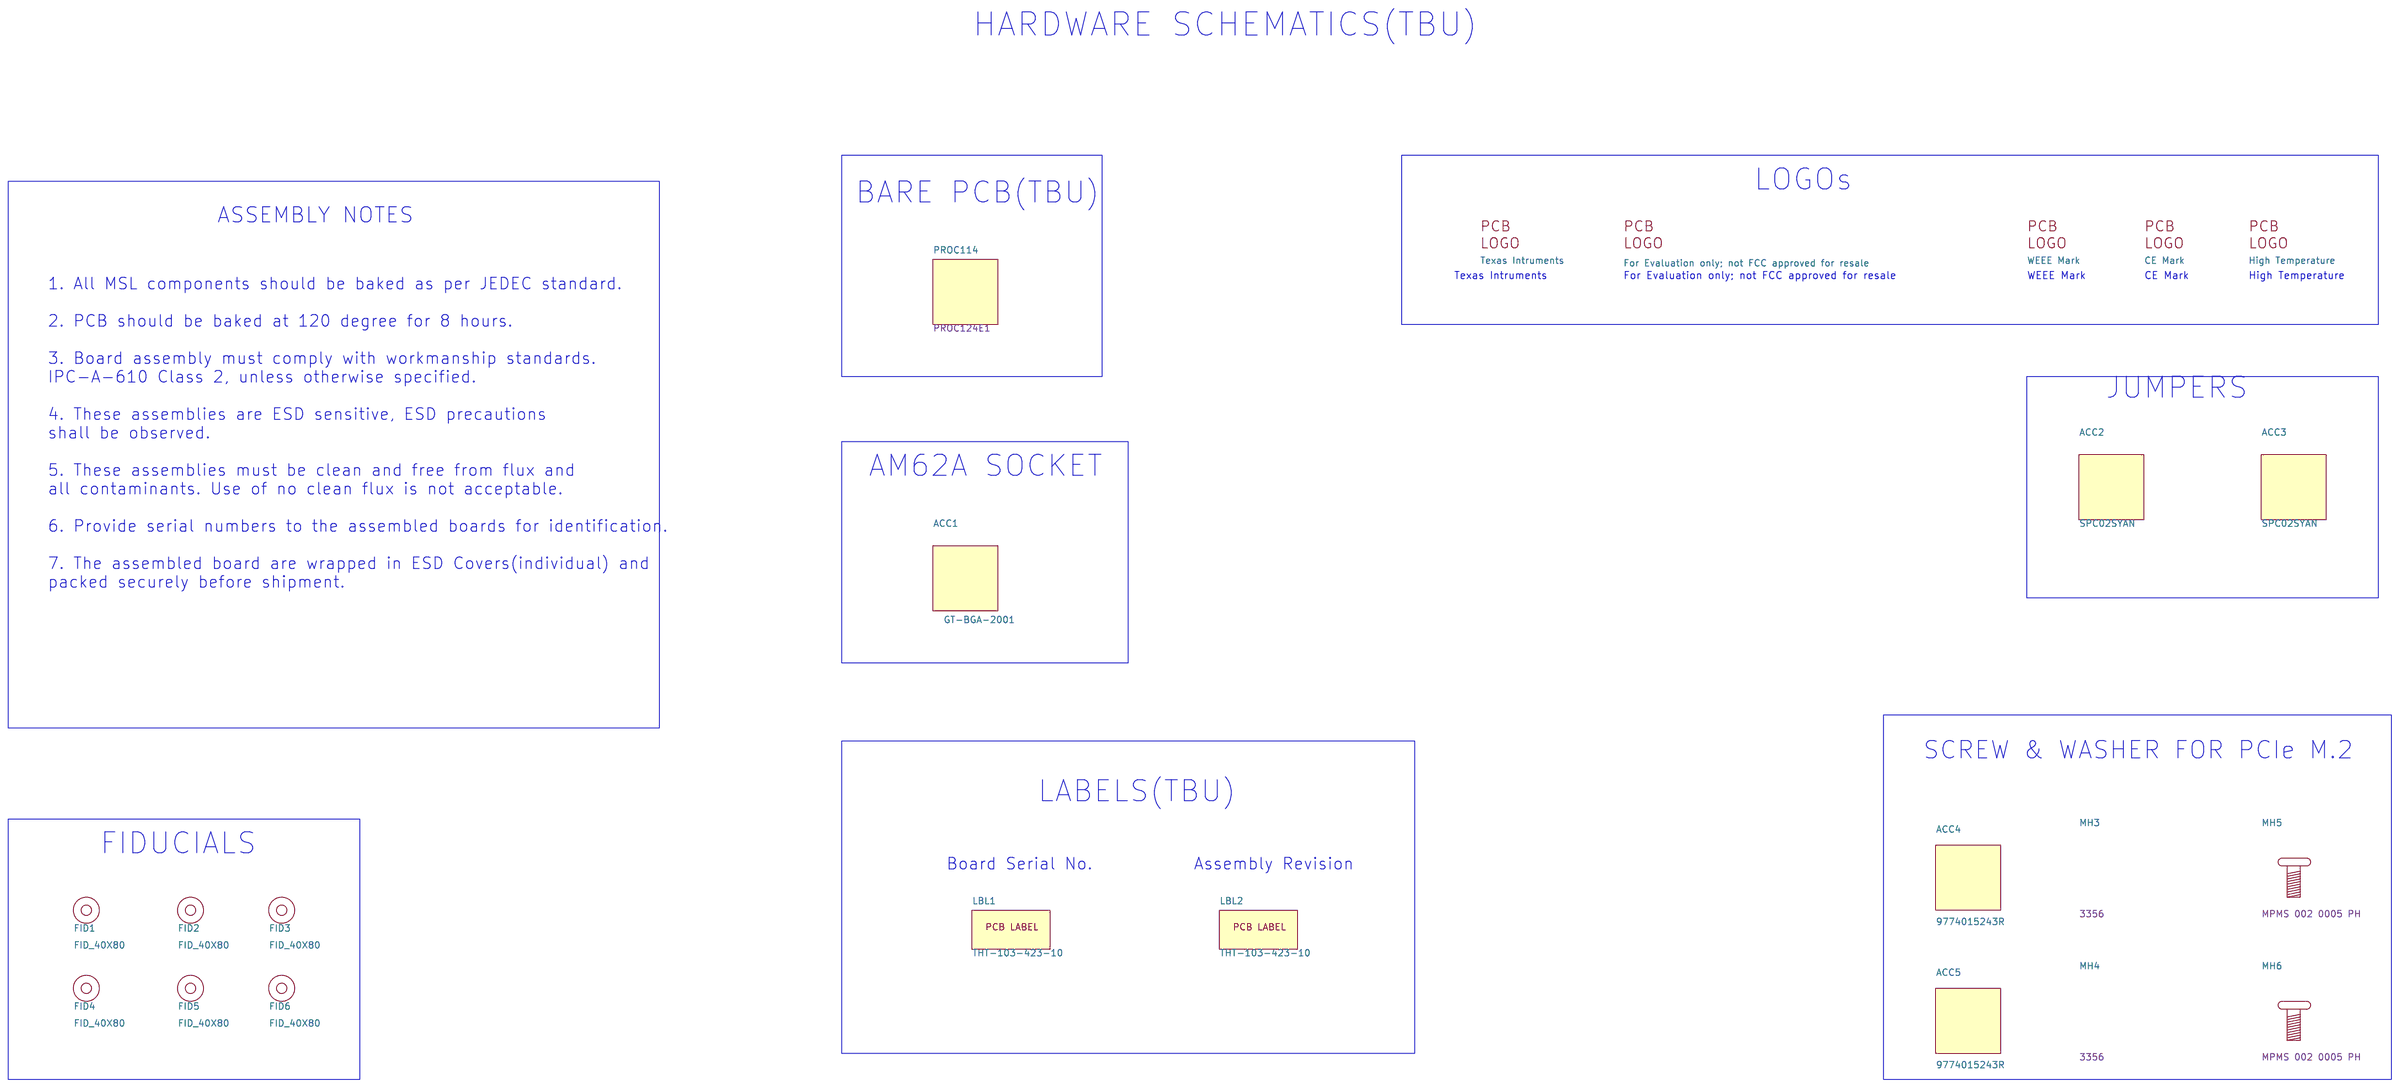
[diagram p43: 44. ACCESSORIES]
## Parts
sheet 32. USER EXPANSION CONNECTOR
U18  AM62A_EVM_SoC  [FBGA484_31-49_710X710_2-7]  (sections A,B,C,D,E,F,G,H,I,J,K,L,M,N,O,P,Q)
sheet 41. OSCILLATOR
C12  0.01uF  [CAP0201_0-5]
C183  0.1uF  [CAP0402_0-75]
C439  0.1uF  [CAP0201_0-5]
C487  0.1uF  [CAP0201_0-5]
R13  10K  [RES0201_0-5]
R14  10K  [RES0201_0-5]
R23  10K_1%  [RES0201_0-5]
R27  22E_1%  [RES0201_0-5]
R28  0E  [RES0201_0-5]
R53  0E  [RES0201_0-5]
R58  0E  [RES0201_0-5]
R59  22E_1%  [RES0201_0-5]
R60  0E  [RES0201_0-5]
R104  10K  [RES0201_0-5]
R184  4.7K  [RES0201_0-5]
R284  10K  [RES0201_0-5]
R307  10K  [RES0201_0-5]
R408  4.7K  [RES0201_0-5]
R409  4.7K  [RES0201_0-5]
R430  10K  [RES0201_0-5]
R433  4.7K  [RES0201_0-5]
R434  4.7K  [RES0201_0-5]
R454  10K  [RES0201_0-5]
R544  10K  [RES0201_0-5]
TP63  TP20_SMD  [TP20_SMD]
TP65  TP20_SMD  [TP20_SMD]
TP69  TP20_SMD  [TP20_SMD]
TP93  TP20_SMD  [TP20_SMD]
TP94  TP20_SMD  [TP20_SMD]
TP96  TP20_SMD  [TP20_SMD]
U6  25.000MHz  [OSC4_ECS-2520MV_100X80_SMD_0-9]
U55  SN74CB3Q3257PWR  [TSSOP16_25-59_205X180]
U96  SN74LVC1G11DRYR  [SON6_SN74LVC2G17_40X60_0-6]
U116  SN74LVC1G11DRYR  [SON6_SN74LVC2G17_40X60_0-6]
sheet 42. RESET
C134  0.1uF  [CAP0201_0-5]
C462  0.1uF  [CAP0201_0-5]
C484  0.1uF  [CAP0201_0-5]
C485  0.1uF  [CAP0201_0-5]
D12  TPD1E10B06DPYR  [DIO_DFN0402_0-5]
D13  TPD1E10B06DPYR  [DIO_DFN0402_0-5]
Q3  IRLML6401  [TO_SOT23-123]
Q13  IRLML6401  [TO_SOT23-123]
Q14  IRLML6401  [TO_SOT23-123]
R183  10K  [RES0201_0-5]
R505  10K  [RES0201_0-5]
R512  4.7K  [RES0201_0-5]
R534  10K  [RES0201_0-5]
R538  10K  [RES0201_0-5]
R539  10K  [RES0201_0-5]
R572  4.7K  [RES0201_0-5]
SW4  7914G-1-000E  [SW4_100X216_200X200_SMD_4-2]
SW5  7914G-1-000E  [SW4_100X216_200X200_SMD_4-2]
TP70  TP20_SMD  [TP20_SMD]
TP80  TP20_SMD  [TP20_SMD]
TP87  TP20_SMD  [TP20_SMD]
U108  SN74LVC3G17DCUR  [VSSOP8_19-68_85X95_0-9]
sheet 43. CAN_FD_WKUP_SW
C104  0.1uF  [CAP0201_0-5]
C110  0.1uF  [CAP0201_0-5]
D3  TPD1E10B06DPYR  [DIO_DFN0402_0-5]
R149  10K  [RES0201_0-5]
SW1  7914G-1-000E  [SW4_100X216_200X200_SMD_4-2]
U35  SN74LVC3G17DCUR  [VSSOP8_19-68_85X95_0-9]
sheet 44. ACCESSORIES
ACC1  GT-BGA-2001  [BGASKT484_GT-BGA-2001_910X910_10-7]
ACC2  SPC02SYAN  [NA]
ACC3  SPC02SYAN  [NA]
ACC4  9774015243R  [NA]
ACC5  9774015243R  [NA]
FID1  FID_40X80  [FID_40X80]
FID2  FID_40X80  [FID_40X80]
FID3  FID_40X80  [FID_40X80]
FID4  FID_40X80  [FID_40X80]
FID5  FID_40X80  [FID_40X80]
FID6  FID_40X80  [FID_40X80]
LBL1  THT-103-423-10  [NA]
LBL2  THT-103-423-10  [NA]
LOGO1  Texas Intruments  [TI_Stacked_Overlay_Small]
LOGO2  For Evaluation only; not FCC approved for resale  [FCC_disclaimer]
LOGO3  WEEE Mark  [TI_Stacked_Overlay_Small]
LOGO4  CE Mark  [TI_Stacked_Overlay_Small]
LOGO5  High Temperature  [TI_Stacked_Overlay_Small]
MH3  FLAT WASHER_M2  [NA]
MH4  FLAT WASHER_M2  [NA]
MH5  PAN HEAD_M2 X 5  [NA]
MH6  PAN HEAD_M2 X 5  [NA]
PCB1  PROC114

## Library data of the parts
U18 = AM62A-EVM_SOC_FCBGA484: IC AM62A SK EVM SoC MICROPROCESSOR FCBGA484; Chkd/date: ALVY/060422; Crtd /date: ALVY/060422; Custom_Duty: 15%; Customs_HS_Code: 85423100; Distributor_name: NA; Distributor_part_number: NA; Footprint Path: Y:\MIS_DATABASE\Library\ALTIUM_TOOL\PCB_FOOTPRINTS\Altium_Footprint_Lib.PcbLib; Height: 2.65MM; Library Ref: AM62A-EVM_SoC_FCBGA484; Mfr_name: TEXAS INSTRUMENTS; Mfr_part_number: AM62A_SK_EVM_SoC; Mistral Part No: 141222040002; Package: FCBGA484; Part_type: ICS\DIGITAL\MICROPROCESSOR; Project: TI_AM62A_SK_EVM; RoHS: NA; Temperature: NA; Tolerance: NA; Voltage: NA; Wattage: NA; Weight: NA; Datasheet: Y:\MIS_DATABASE\DATASHEETS\ICS\DIGITAL\MICROCONTROLLER\AM62A_SK_EVM.PDF
C12 = CAP: CAP CERAMIC 0.01uF 25V 10% X5R 0201; Chkd/date: MANIRAJA/230118; Crtd /date: MANIRAJA/230118; Custom_Duty: 15%; Customs_HS_Code: 85322990; Distributor_name: DIGIKEY; Distributor_part_number: GRM033R61E103KA12J-ND; Footprint Path: Y:\MIS_DATABASE\Library\ALTIUM_TOOL\PCB_FOOTPRINTS\Altium_Footprint_Lib.PcbLib; Height: 0.33MM; Library Path: Y:\MIS_DATABASE\Library\ALTIUM_TOOL\SCHEMATICS_PARTS\MS_DISCRETE_Library.schlib; Mfr_name: MURATA; Mfr_part_number: GRM033R61E103KA12J; Mistral Part No: 120018010007-R; Package: 0201; Part_type: CAPACITORS\CERAMIC; Project: TI_MAXIE_CPB; RoHS: RoHS; Temperature: -55°C+85°C; Tolerance: 10%; Voltage: 25V; Wattage: NA; Weight: 0.33mg; Datasheet: Y:\MIS_DATABASE\DATASHEETS\CAPACITORS\GRM033R61E103KA12.PDF
C183 = CAP: CAP CERAMIC 0.1uF 50V 10% X7R 0402; Alt_Mfr_name: YAGEO AMERICA; Alt_Mfr_part_number: CC0402KRX5R8BB104; Chkd/date: MANIRAJA/261020; Crtd /date: ALVY/211020; Custom_Duty: 15%; Customs_HS_Code: 85322990; Distributor_name: DIGIKEY; Distributor_part_number: 490-10700-1-ND; Footprint Path: Y:\MIS_DATABASE\Library\ALTIUM_TOOL\PCB_FOOTPRINTS\Altium_Footprint_Lib.PcbLib; Height: 0.55MM; Library Path: Y:\MIS_DATABASE\Library\ALTIUM_TOOL\SCHEMATICS_PARTS\MS_DISCRETE_Library.schlib; Mfr_name: MURATA; Mfr_part_number: GRM155R71H104KE14D; Mistral Part No: 120011100014-R; Package: 0402; Part_type: CAPACITORS\CERAMIC; Project: J7_CP; RoHS: RoHS; Temperature: -55°C+125°C; Tolerance: 10%; Voltage: 50V; Wattage: NA; Weight: 3.1mg; Datasheet: Y:\MIS_DATABASE\DATASHEETS\CAPACITORS\GRM155R71H104KE14.PDF
C104 C110 C134 C439 C462 C484 C485 C487 = CAP: CAP CERAMIC 0.1uF 16V 10% X5R 0201; Alt_Mfr_name: YAGEO AMERICA; Alt_Mfr_part_number: CC0402KRX5R8BB104; Chkd/date: MANIRAJA/230118; Crtd /date: MANIRAJA/230118; Custom_Duty: 15%; Customs_HS_Code: 85322990; Distributor_name: DIGIKEY; Distributor_part_number: 490-14305-1-ND; Footprint Path: Y:\MIS_DATABASE\Library\ALTIUM_TOOL\PCB_FOOTPRINTS\Altium_Footprint_Lib.PcbLib; Height: 0.33MM; Library Path: Y:\MIS_DATABASE\Library\ALTIUM_TOOL\SCHEMATICS_PARTS\MS_DISCRETE_Library.schlib; Mfr_name: MURATA; Mfr_part_number: GRM033R61C104KE14D; Mistral Part No: 120009030072-R; Package: 0201; Part_type: CAPACITORS\CERAMIC; Project: TI_MAXIE_CPB; RoHS: RoHS; Temperature: -55°C+85°C; Tolerance: 10%; Voltage: 16V; Wattage: NA; Weight: 0.33mg; Datasheet: Y:\MIS_DATABASE\DATASHEETS\CAPACITORS\GRM033R61C104KE14.PDF
R13 R14 R104 R149 R183 R284 R307 R430 R454 R505 R534 R538 R539 R544 = RESISTOR: RES 10K 1/20W 5% 0201; Chkd/date: MANIRAJA/050517; Crtd /date: MANIRAJA/050517; Custom_Duty: 15%; Customs_HS_Code: 85332119; Distributor_name: DIGIKEY; Distributor_part_number: 311-10KNCT-ND; Footprint Path: Y:\MIS_DATABASE\Library\ALTIUM_TOOL\PCB_FOOTPRINTS\Altium_Footprint_Lib.PcbLib; Height: 0.26MM; Library Path: Y:\MIS_DATABASE\Library\ALTIUM_TOOL\SCHEMATICS_PARTS\MS_DISCRETE_Library.schlib; Mfr_name: YAGEO AMERICA; Mfr_part_number: RC0201JR-0710KL; Mistral Part No: 110010070051-R; Package: 0201; Part_type: RESISTORS\FIXED; Project: GOLDEN-I LITE; RoHS: RoHS; Temperature: -55°C+125°C; Tolerance: 5%; Voltage: NA; Wattage: 1/20W; Weight: 0.17mg; Datasheet: Y:\MIS_DATABASE\DATASHEETS\RESISTORS\RCXXXXL-SER_MAR18.PDF
R23 = RESISTOR: RES 10K 1/20W 1% 0201; Chkd/date: VASANTHA/270117; Crtd /date: MANIRAJA/270117; Custom_Duty: 15%; Customs_HS_Code: 85332119; Distributor_name: DIGIKEY; Distributor_part_number: 311-10.0KMCT-ND; Footprint Path: Y:\MIS_DATABASE\Library\ALTIUM_TOOL\PCB_FOOTPRINTS\Altium_Footprint_Lib.PcbLib; Height: 0.26MM; Library Path: Y:\MIS_DATABASE\Library\ALTIUM_TOOL\SCHEMATICS_PARTS\MS_DISCRETE_Library.schlib; Mfr_name: YAGEO AMERICA; Mfr_part_number: RC0201FR-0710KL; Mistral Part No: 110011040018-R; Package: 0201; Part_type: RESISTORS\FIXED; Project: GOLDEN-I LITE; RoHS: RoHS; Temperature: -55°C+125°C; Tolerance: 1%; Voltage: NA; Wattage: 1/20W; Weight: 0.17mg; Datasheet: Y:\MIS_DATABASE\DATASHEETS\RESISTORS\RCXXXXL-SER_MAR18.PDF
R27 R59 = RESISTOR: RES 22E 1/20W 1% 0201; Chkd/date: MAZHAR/140709; Crtd /date: MAZHAR/220807; Custom_Duty: 15%; Customs_HS_Code: 85332119; Distributor_name: DIGIKEY; Distributor_part_number: P22.0ABCT-ND; Footprint Path: Y:\MIS_DATABASE\Library\ALTIUM_TOOL\PCB_FOOTPRINTS\Altium_Footprint_Lib.PcbLib; Height: 0.26MM; Library Path: Y:\MIS_DATABASE\Library\ALTIUM_TOOL\SCHEMATICS_PARTS\MS_DISCRETE_Library.schlib; Mfr_name: PANASONIC-ECG; Mfr_part_number: ERJ-1GEF22R0C; Mistral Part No: 110009030522-R; Package: 0201; Part_type: RESISTORS\FIXED; Project: V8TS; RoHS: RoHS; Temperature: -55°C+125°C; Tolerance: 1%; Voltage: NA; Wattage: 1/20W; Weight: 0.15mg; Datasheet: Y:\MIS_DATABASE\DATASHEETS\RESISTORS\PAN-ERJSER_NOV17.PDF
R28 R53 R58 R60 = RESISTOR: RES 0E 1/20W 5% 0201; Chkd/date: NAVEED/301214; Crtd /date: MUDDU/120710; Custom_Duty: 15%; Customs_HS_Code: 85332119; Distributor_name: DIGIKEY; Distributor_part_number: 311-0.0NCT-ND; Footprint Path: Y:\MIS_DATABASE\Library\ALTIUM_TOOL\PCB_FOOTPRINTS\Altium_Footprint_Lib.PcbLib; Height: 0.26MM; Library Path: Y:\MIS_DATABASE\Library\ALTIUM_TOOL\SCHEMATICS_PARTS\MS_DISCRETE_Library.schlib; Mfr_name: YAGEO AMERICA; Mfr_part_number: RC0201JR-070RL; Mistral Part No: 110010070067-R; Package: 0201; Part_type: RESISTORS\FIXED; Project: PB_BUGBASE; RoHS: RoHS; Temperature: -55°C+125°C; Tolerance: 5%; Voltage: NA; Wattage: 1/20W; Weight: 0.17mg; Datasheet: Y:\MIS_DATABASE\DATASHEETS\RESISTORS\RCXXXXL-SER_MAR18.PDF
R184 R408 R409 R433 R434 = RESISTOR: RES 4.7K 1/20W 5% 0201; Chkd/date: MANIRAJA/200921; Crtd /date: ALVY/200921; Custom_Duty: 15%; Customs_HS_Code: 85332119; Distributor_name: DIGIKEY; Distributor_part_number: 311-4.7KNCT-ND; Footprint Path: Y:\MIS_DATABASE\Library\ALTIUM_TOOL\PCB_FOOTPRINTS\Altium_Footprint_Lib.PcbLib; Height: 0.26MM; Library Path: Y:\MIS_DATABASE\Library\ALTIUM_TOOL\SCHEMATICS_PARTS\MS_DISCRETE_Library.schlib; Mfr_name: YAGEO AMERICA; Mfr_part_number: RC0201JR-074K7L; Mistral Part No: 110021090007-R; Package: 0201; Part_type: RESISTORS\FIXED; Project: TI_AM62x SKEVM_BRD; RoHS: RoHS; Temperature: -55°C+125°C; Tolerance: 5%; Voltage: NA; Wattage: 1/20W; Weight: 0.17mg; Datasheet: Y:\MIS_DATABASE\DATASHEETS\RESISTORS\RCXXXXL-SER_MAR18.PDF
TP63 TP65 TP69 TP70 TP80 TP87 TP93 TP94 TP96 = TESTPOINT: TESTPOINT CIR 20 SMD; Chkd/date: SHREESHAIL/171006; Crtd /date: MAZHAR/171006; Custom_Duty: NA; Customs_HS_Code: NA; Distributor_name: NA; Distributor_part_number: NA; Footprint Path: Y:\MIS_DATABASE\Library\ALTIUM_TOOL\PCB_FOOTPRINTS\Altium_Footprint_Lib.PcbLib; Height: NA; Library Path: Y:\MIS_DATABASE\Library\ALTIUM_TOOL\SCHEMATICS_PARTS\MS_DISCRETE_Library.schlib; MECHANICAL 3D STEP FILE: NA; Mfr_name: LOCAL; Mistral Part No: NA; Package: SMD; Project: BT MODULE_CSRBC04; RoHS: NA; Temperature: NA; Tolerance: NA; Voltage: NA; Wattage: NA; Weight: NA; Datasheet: NA
U6 = OSC4_ASFL3: OSC 25.000MHz CMOS SMD; Chkd/date: MANIRAJA/181120; Crtd /date: ALVY/181120; Custom_Duty: 24%; Customs_HS_Code: 85437099; Distributor_name: DIGIKEY; Distributor_part_number: XC2752CT-ND; Footprint Path: Y:\MIS_DATABASE\Library\ALTIUM_TOOL\PCB_FOOTPRINTS\Altium_Footprint_Lib.PcbLib; Height: 0.90MM; Library Path: Y:\MIS_DATABASE\Library\ALTIUM_TOOL\SCHEMATICS_PARTS\MS_DISCRETE_Library.schlib; Mfr_name: ECS INC; Mfr_part_number: ECS-2520MV-250-CN-TR; Mistral Part No: 130020110041-R; Package: SMD; Part_type: OSCILLATORS; Project: AM64X_SKEVM; RoHS: RoHS; Temperature: -40°C+85°C; Tolerance: NA; Voltage: NA; Wattage: NA; Weight: 311mg; Datasheet: Y:\MIS_DATABASE\DATASHEETS\MISC\CRY_OSC\ECS-2520MV.PDF
U55 = SN74CB3Q3257PWR_TSSOP16: IC 4BIT 1-OF-2 FET MULTIPLEXER/DEMULTIPLEXER TSSOP16; Chkd/date: SUHAS/251010; Crtd /date: USMAN/060109; Custom_Duty: 15%; Customs_HS_Code: 85423100; Distributor_name: DIGIKEY; Distributor_part_number: 296-19138-1-ND; Height: 1.20MM; Mfr_name: TEXAS INSTRUMENTS; Mistral Part No: 141009030117-R; Package: TSSOP16; Part_type: ICS\DIGITAL\COMBINATIONAL; Project: OMAP_EVM; RoHS: Sb/ Br FREE; Temperature: -40°C+85°C; Datasheet: Y:\MIS_DATABASE\DATASHEETS\ICS\DIGITAL\COMBINATIONAL\SN74CB3Q3257.PDF
U96 U116 = SN74LVC1G11DCKR_SC70-6: IC SINGLE 3-INPUT POSITIVE-AND GATE SON6; Chkd/date: MANIRAJA/270121; Crtd /date: ALVY/270121; Custom_Duty: 15%; Customs_HS_Code: 85423100; Distributor_name: DIGIKEY; Distributor_part_number: 296-30120-1-ND; Footprint Path: Y:\MIS_DATABASE\Library\ALTIUM_TOOL\PCB_FOOTPRINTS\Altium_Footprint_Lib.PcbLib; Height: 0.60MM; Library Path: Y:\MIS_DATABASE\Library\ALTIUM_TOOL\SCHEMATICS_PARTS\MS_GATE_Library.schlib; Mfr_name: TEXAS INSTRUMENTS; Mistral Part No: 141021010013-R; Package: SON6; Part_type: ICS\DIGITAL\GATES; Project: AM64X_SKEVM; RoHS: RoHS; Temperature: -40°C+125°C; Tolerance: NA; Voltage: NA; Wattage: NA; Weight: 33mg; Datasheet: Y:\MIS_DATABASE\DATASHEETS\ICS\DIGITAL\GATES\SN74LVC1G_NOV16.PDF
D3 D12 D13 = DIODE_SOD323: DIODE 1CH ESD PROTECTION X1SON2; Chkd/date: MANIRAJA/040420; Crtd /date: VASANTHA/181114; Custom_Duty: 15%; Customs_HS_Code: 85423100; Distributor_name: DIGIKEY; Distributor_part_number: 296-30406-1-ND; Footprint Path: Y:\MIS_DATABASE\Library\ALTIUM_TOOL\PCB_FOOTPRINTS\Altium_Footprint_Lib.PcbLib; Height: 0.45MM; Library Path: Y:\MIS_DATABASE\Library\ALTIUM_TOOL\SCHEMATICS_PARTS\MS_DISCRETE_Library.schlib; Mfr_name: TEXAS INSTRUMENTS; Mistral Part No: 130014110022-R; Package: X1SON2; Part_type: DIODE; Project: GALILEO_EVM; RoHS: RoHS; Temperature: -40°C+125°C; Tolerance: NA; Voltage: NA; Wattage: NA; Weight: 1mg; Datasheet: Y:\MIS_DATABASE\DATASHEETS\ICS\INTERFACE\TPD1E10B06-SER.PDF
Q3 Q13 Q14 = MOSFET_IRLML6401TR: TRANSISTOR MOSFET P-CHANNEL SOT23-3; Chkd/date: SHREESHAIL/020206; Crtd /date: MAZHAR/040505; Custom_Duty: 15%; Customs_HS_Code: 85412900; Distributor_name: DIGIKEY; Distributor_part_number: IRLML6401PBFCT-ND; Height: 1.11MM; Mfr_name: IRF; Mfr_part_number: IRLML6401TRPBF; Mistral Part No: 130009031213-P; Package: SOT23-3; Part_type: TRANSISTOR\MOSFET; Project: G4_SVGA; RoHS: Pb-Free; Temperature: -55°C+150°C; Tolerance: NA; Voltage: NA; Wattage: NA; Weight: NA; Datasheet: Y:\MIS_DATABASE\DATASHEETS\DISCRETES\TRANSISTORS_FETS\IRLML6401.PDF
R512 R572 = RESISTOR: RES 4.7K 1/20W 5% 0201; Chkd/date: MANIRAJA/200921; Crtd /date: ALVY/200921; Custom_Duty: 15%; Customs_HS_Code: 85332119; Distributor_name: DIGIKEY; Distributor_part_number: 311-4.7KNCT-ND; Footprint Path: Y:\MIS_DATABASE\Library\ALTIUM_TOOL\PCB_FOOTPRINTS\Altium_Footprint_Lib.PcbLib; Height: 0.26MM; Library Path: Y:\MIS_DATABASE\Library\ALTIUM_TOOL\SCHEMATICS_PARTS\MS_DISCRETE_Library.schlib; Manufacturer: YAGEO AMERICA; Mfr_name: YAGEO AMERICA; Mfr_part_number: RC0201JR-074K7L; Mistral Part No: 110021090007-R; Package: 0201; Part_type: RESISTORS\FIXED; Project: TI_AM62x SKEVM_BRD; RoHS: RoHS; Temperature: -55°C+125°C; Tolerance: 5%; Voltage: NA; Wattage: 1/20W; Weight: 0.17mg; Datasheet: Y:\MIS_DATABASE\DATASHEETS\RESISTORS\RCXXXXL-SER_MAR18.PDF
SW1 SW4 SW5 = 7914G-1-000E__7914G: SWITCH SPST-NO 4MM SQ SMD 7914G; Chkd/date: VASANTHA/271216; Crtd /date: BAVISH/051010; Custom_Duty: 24%; Customs_HS_Code: 85369090; Distributor_name: DIGIKEY; Distributor_part_number: 7914G-000ECT-ND; Height: 4.19MM; Library Ref: 7914G-1-000E _7914G; Mfr_name: BOURNS; Mistral Part No: 130015110004-R; Package: 7914G; Part_type: ELECTRO-MECHANICAL\SWITCH; Project: AAAUC; RoHS: RoHS; Temperature: -55°C+125°C; Tolerance: NA; Voltage: NA; Wattage: NA; Weight: NA; Datasheet: Y:\MIS_DATABASE\DATASHEETS\ICS\DIGITAL\COMBINATIONAL\7914G-1-000E.PDF
U35 U108 = SN74LVC3G17DCUR_VSSOP8: IC TRIPLE SCHMITT-TRIGGER BUFFER VSSOP8; Chkd/date: MANIRAJA/280917; Crtd /date: MANIRAJA/280917; Custom_Duty: 15%; Customs_HS_Code: 85423100; Distributor_name: DIGIKEY; Distributor_part_number: 296-18818-1-ND; Height: 0.90MM; Mfr_name: TEXAS INSTRUMENTS; Mistral Part No: 141017090019-R; Package: VSSOP8; Part_type: ICS\DIGITAL\COMBINATIONAL; Project: TI_MAXIE_CPB; RoHS: RoHS; Temperature: -40°C+125°C; Tolerance: NA; Voltage: NA; Wattage: NA; Weight: 9.6mg; Datasheet: Y:\MIS_DATABASE\DATASHEETS\ICS\DIGITAL\COMBINATIONAL\SN74LVC3G17.PDF
ACC1 = ACCESSORY: ACCESSORIE BGA SOCKET AM62A SVB SoC MICROPROCESSOR FCBGA484; Chkd/date: ALVY/180422; Crtd /date: ALVY/180422; Custom_Duty: NA; Customs_HS_Code: NA; Distributor_name: NA; Distributor_part_number: NA; Footprint Path: NA; Height: 10.69MM; Library Path: NA; Mfr_name: IRONWOOD ELECTRONICS; Mistral Part No: 160022040013; Package: FCBGA484; Part_type: ACCESSORIES; Project: TI_AM62A_SVB_BRD; RoHS: NA; Temperature: NA; Tolerance: NA; Voltage: NA; Wattage: NA; Weight: NA; Datasheet: Y:\MIS_DATABASE\DATASHEETS\MISC\ACCESSORIES\GT-BGA-2001.PDF
ACC2 ACC3 = ACCESSORY: ACCESSORIE JUMPER SHORTING GOLD FLASH; Chkd/date: SUHAS\211010; Crtd /date: USMAN/301208; Distributor_name: DIGIKEY; Distributor_part_number: S9001-ND; Footprint Path: Y:\MIS_DATABASE\Library\ALTIUM_TOOL\PCB_FOOTPRINTS\Altium_Footprint_Lib.PcbLib; Library Path: Y:\MIS_DATABASE\Library\ALTIUM_TOOL\SCHEMATICS_PARTS\MS_MECHANICAL_Library.schlib; Mfr_name: SULLINS CONNECTOR; Mistral Part No: 160009030153-R; Part_type: ACCESSORIES; Project: SMART VIEW_NVR; RoHS: RoHS; Temperature: -55°C+105°C; Datasheet: Y:\MIS_DATABASE\DATASHEETS\MISC\MODULES\SPC02SYAN.PDF
ACC4 ACC5 = ACCESSORY: STANDOFF BOARD TO BOARD 1.50MM LENGTH FEMALE M2 THREADED SS; Chkd/date: MANIRAJA/280219; Crtd /date: ALVY/280219; Distributor_name: DIGIKEY; Distributor_part_number: 732-7069-1-ND; Mfr_name: WURTH ELECTRONICS; Mistral Part No: 160019020049-R; Package: SS; Part_type: MECHANICAL\STANDOFF; Project: TI_J7ES_EVM_CP; RoHS: RoHS; Weight: 178mg; Datasheet: Y:\MIS_DATABASE\DATASHEETS\MISC\MECHANICAL\9774015243R.PDF
FID1-FID6 = Fiducial
LBL1 LBL2 = ACCESSORY_THT-3-423-10: ACCESSORIE 1 WORKHORSE POLYSTER LABLE 0.25" X 1"; Chkd/date: MANIRAJA/270218; Crtd /date: ALVY/260218; Footprint Path: Y:\MIS_DATABASE\Library\ALTIUM_TOOL\PCB_FOOTPRINTS\Altium_Footprint_Lib.PcbLib; Library Path: Y:\MIS_DATABASE\Library\ALTIUM_TOOL\SCHEMATICS_PARTS\MS_MECHANICAL_Library.schlib; Mfr_name: BRADY; Mistral Part No: 160018020185; Part_type: ACCESSORIES; Project: TI_MAXIE_CPB
LOGO1 LOGO3-LOGO5 = TI_Logo
LOGO2 = FCC_disclaimer
MH3 MH4 = WASHER_FLAT: FLAT WASHER FOR M2 NYLON; Chkd/date: MANIRAJA/110319; Crtd /date: ALVY/110319; Distributor_name: DIGIKEY; Distributor_part_number: 36-3356-ND; Mfr_name: KEYSTONE; Mfr_part_number: 3356; Mistral Part No: 160019030017-R; Package: NYLON; Part_type: MECHANICAL\WASHERS; Project: TI_J7ES_EVM_CP; RoHS: RoHS; Datasheet: Y:\MIS_DATABASE\DATASHEETS\MISC\MECHANICAL\3356.PDF
MH5 MH6 = SCREW_PAN: PHILLIPS PAN HEAD SCREW - M2 X 5; Chkd/date: MANIRAJA/150319; Crtd /date: MANIRAJA/150319; Distributor_name: DIGIKEY; Distributor_part_number: H738-ND; Height: 5.00MM; Mfr_name: B AND F FASTENER; Mfr_part_number: MPMS 002 0005 PH; Mistral Part No: 160019030026-R; Part_type: MECHANICAL\SCREWS; Project: TI_J7ES_EVM_CP; RoHS: RoHS; Datasheet: Y:\MIS_DATABASE\DATASHEETS\MISC\MECHANICAL\SCREW_MPMSXXX.PDF
PCB1 = PCB_0: AM62x LOW POWER SKEVM; Mfr_part_number: PROC124E1

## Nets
DGND: C12.1 C104.2 C110.1 C134.1 C183.1 C439.1 C462.1 C484.1 C485.1 C487.1 D3.1 D12.1 D13.1 Q3.3(D) Q13.3(D) Q14.3(D) R14.1 R104.2 R184.2 R284.1 R307.1 R430.2 SW1.1 SW1.4 SW4.1 SW4.4 SW5.1 SW5.4 U6.2(GND) U35.4(GND) U55.8(GND) U96.2(GND) U108.4(GND) U116.2(GND) ; also on sheet 9 10 11 12 13 14 15 16 17 18 19 20 21 22 23 24 25 26 27 28 29 30 31 32 33 34 35 36 37 38 39 40
VCC1V8_CLKBUF: C12.2 R23.2 U6.4(VDD) ; also on sheet 24
VCC1V8_SYS: C439.2 R454.1 U96.5(VCC) ; also on sheet 12 13 17 18 20 24 33 36 38 39
VCC_3V3_SYS: C183.2 C462.2 C487.2 R13.2 R183.1 R408.1 R409.1 R433.1 R434.1 R505.1 R534.2 R538.1 R539.1 R544.1 U55.16(VCC) U108.8(VCC) U116.5(VCC) ; also on sheet 9 10 12 13 17 18 19 21 22 23 25 26 28 29 30 32 33 34 35 36 37 38 39 40
VCC_5V0_PG: U116.3(B) ; also on sheet 10
CAN_FD_WKUP_SW_INH: U35.7(1Y) ; also on sheet 33
CAN_IO_3V3: C104.1 R149.1 U35.8(VCC) ; also on sheet 12 14 30 33
CLKOUT0: R27.2 R28.2 ; also on sheet 24
CLKOUT_OSC: R27.1 U6.3(OUTPUT)
CONN_MCU_PORz: U96.1(A) ; also on sheet 33
CONN_MCU_RESETz: Q3.1(G) ; also on sheet 33
CPSW_ETH_INTn: R53.1 ; also on sheet 22
CSI_GPIO2: U55.6(2B2) ; also on sheet 36
CSI_GPIO3: U55.3(1B2) ; also on sheet 36
CSI_GPIO4: U55.10(3B2) ; also on sheet 36
DEBOUNCE_CAN_FD_WKUP: C110.2 D3.2 R149.2 SW1.2 SW1.3 U35.1(1A)
DEBOUNCE_GPIO_INT_MCU_SoC: C484.2 D12.2 Q13.2(S) R538.2 SW5.2 SW5.3 U108.3(2A)
Debounce_MCU_RESETz: C134.2 Q3.2(S) R183.2 TP70.1(TP) U108.1(1A)
DEBOUNCE_SOC_WARMRESETn: C485.2 D13.2 Q14.2(S) R539.2 SW4.2 SW4.3 U108.6(3A)
EXP_CLKOUT0: R59.1 ; also on sheet 32
EXP_GPIO1_22: U18.F14(UART0_CTSN) ; also on sheet 32
EXP_SPI0_CLK: U55.2(1B1) ; also on sheet 32
EXP_SPI0_CS0: U55.11(3B1) ; also on sheet 32
EXP_SPI0_CS1: U18.C16(SPI0_CS1) ; also on sheet 32
EXP_SPI0_D0: U55.5(2B1) ; also on sheet 32
EXP_SPI0_D1: U18.E15(SPI0_D1) ; also on sheet 32
EXP_UART5_RXD: U18.B17(MCAN0_TX) ; also on sheet 32
EXP_UART5_TXD: U18.C18(MCAN0_RX) ; also on sheet 32
EXT_CLKOUT0: R28.1 R60.1
EXT_CLKOUT0_R: R58.2 R59.2 R60.2 U18.B16(EXT_REFCLK1)
GPIO1_23_INTn: R512.2 U18.C15(UART0_RTSN) ; also on sheet 39
GPIO_MCU_SoC: R512.1 R572.1 U108.5(2Y)
GPIO_MCU_SoC_INTn: R572.2 ; also on sheet 33
JTAG_EMU_RSTn: U116.6(C) ; also on sheet 29
MCU_PORz: R184.1 R454.2 TP69.1(TP) U18.A7(MCU_PORZ) U96.4(Y)
MCU_RESETSTATz: U18.D14(MCU_RESETSTATZ) ; also on sheet 33
MCU_RESETz: R505.2 TP80.1(TP) U18.C12(MCU_RESETZ) U108.7(1Y)
MCU_SAFETY_ERRORz_1V8: U18.B8(MCU_ERRORN) ; also on sheet 33
PMIC_INTn: R53.2 U18.F17(EXTINTN) ; also on sheet 12
PMIC_POWERGOOD: U116.1(A) ; also on sheet 12
PORz_OUT: R104.1 TP63.1(TP) U18.F18(PORZ_OUT) ; also on sheet 19 22 23 26
RESETSTATz: R430.1 TP65.1(TP) U18.F19(RESETSTATZ) ; also on sheet 18 19 20 22 23 26 37 38 39 40
RMII_CLOCK: R58.1 R307.2 ; also on sheet 23
SoC_I2C0_SCL: R408.2 U18.D17(I2C0_SCL) ; also on sheet 9 12 21 23 32
SoC_I2C0_SDA: R409.2 U18.E16(I2C0_SDA) ; also on sheet 9 12 21 23 32
SOC_I2C1_SCL: R433.2 U18.C17(I2C1_SCL) ; also on sheet 13 21 25 38 39 40
SOC_I2C1_SDA: R434.2 U18.E17(I2C1_SDA) ; also on sheet 13 21 25 38 39 40
SoC_PORz: R544.2 U96.3(B) U116.4(Y)
SoC_SPI0_CLK: U18.A17(SPI0_CLK) U55.4(1A)
SoC_SPI0_CS0: U18.D16(SPI0_CS0) U55.9(3A)
SoC_SPI0_D0: U18.B15(SPI0_D0) U55.7(2A)
SOC_UART0_RX_3V3: U18.E14(UART0_RXD) ; also on sheet 30
SOC_UART0_TX_3V3: U18.D15(UART0_TXD) ; also on sheet 30
SoC_WARM_RESETZ: R534.1 TP87.1(TP) U18.E19(RESET_REQZ) U108.2(3Y)
SPI0_FET_OE: R284.2 U55.15(~{OE}) ; also on sheet 39
SPI0_FET_SEL: R13.1 R14.2 U55.1(S) ; also on sheet 39
TEST_GPIO1: Q13.1(G) ; also on sheet 25 27
TEST_PORZn: U96.6(C) ; also on sheet 25 27
TEST_WARMRESETn: Q14.1(G) ; also on sheet 25 27
N16947096: R23.1 U6.1(TRI-STATE)
N23178675: TP96.1(TP) U55.14(4B1)
N23178691: TP94.1(TP) U55.13(4B2)
N23178707: TP93.1(TP) U55.12(4A)

Not connected (* = marked no-connect by the designer): U18 C6(IFORCE)* D6(VSENSE)* E7(ATEST0)*; U35 2(3Y)* 3(2A)* 5(2Y)* 6(3A)*

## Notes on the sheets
sheet 41
- OSCILLATOR
- SOC - GENERAL
- GPIO1_24
- GPIO1_26
- GPIO1_25
- GPIO1_27
- GPIO_22
- GPIO1_28
- GPIO1_29
- GPIO_23
- GPIO1_17
- [SCLK/GPO]
- GPIO1_18
- [MOSI/GPIO]
- GPIO1_19
- GPIO1_15
- [CS/GPIO]
- RESERVED PINS
- GPIO1_16
- RESERVED PINS
- ECS-2520MV-250-CN-TR
- SoC SPI0 FET SWITCH
- DNI
- 25Mhz XTAL
- MCU_OSC0_XI
- EXT_REFCLK1
- DNI
- CLK
- CLK
- ETH1
- [SCLK/GPO]
- 1:4 CLK BUFF
- ETH2
- MOSI
- MOSI
- [MOSI/GPIO]
- CSI
- CS
- CS
- 25Mhz Osc
- [CS/GPIO]
- SOC - RESET
- INPUT/OUTPUT
- OEn
- SEL
- An
- L
- L(DEFAULT)
- An=nB1
- EXP HDR
- L
- H
- An=nB2
- MIPI CSI
- Pull-down resistor on PORz_OUT is provided to keep the signal
  low until the processor is released from reset during the
  power-up seqence
- MCU POWER ON RESET
sheet 42
- RESET
- DEBOUNCE CIRCUIT
- MCU WARM RESET
- SOC WARM RESET
- Silk: RST
- USER INTERRUPT
- Silk: INT
sheet 43
- CAN-FD FAST WAKE UP SW
- Silk: RST
sheet 44
- HARDWARE SCHEMATICS(TBU)
- LOGOs
- BARE PCB(TBU)
- ASSEMBLY NOTES
- 1. All MSL components should be baked as per JEDEC standard.
  2. PCB should be baked at 120 degree for 8 hours.
  3. Board assembly must comply with workmanship standards.
  IPC-A-610 Class 2, unless otherwise specified.
  4. These assemblies are ESD sensitive, ESD precautions
  shall be observed.
  5. These assemblies must be clean and free from flux and
  all contaminants. Use of no clean flux is not acceptable.
  6. Provide serial numbers to the assembled boards for identification.
  7. The assembled board are wrapped in ESD Covers(individual) and
  packed securely before shipment.
- Texas Intruments
- For Evaluation only; not FCC approved for resale
- WEEE Mark
- CE Mark
- High Temperature
- JUMPERS
- AM62A SOCKET
- SCREW & WASHER FOR PCIe M.2
- LABELS(TBU)
- FIDUCIALS
- Board Serial No.
- Assembly Revision
